VERSION 5.8 ;
BUSBITCHARS "[]" ;
DIVIDERCHAR "/" ;
UNITS
    DATABASE MICRONS 1000 ;
END UNITS

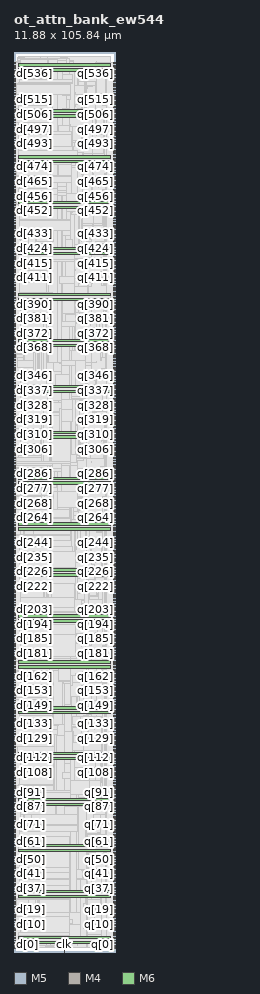
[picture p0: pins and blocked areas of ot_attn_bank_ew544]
MACRO ot_attn_bank_ew544
  FOREIGN ot_attn_bank_ew544 0 0 ;
  CLASS BLOCK ;
  SIZE 11.88 BY 105.84 ;
  PIN clk
    DIRECTION INPUT ;
    USE SIGNAL ;
    PORT
      LAYER M5 ;
        RECT  5.904 0 5.928 0.192 ;
    END
  END clk
  PIN d[0]
    DIRECTION INPUT ;
    USE SIGNAL ;
    PORT
      LAYER M4 ;
        RECT  0 0.384 0.192 0.408 ;
    END
  END d[0]
  PIN d[100]
    DIRECTION INPUT ;
    USE SIGNAL ;
    PORT
      LAYER M4 ;
        RECT  0 19.584 0.192 19.608 ;
    END
  END d[100]
  PIN d[101]
    DIRECTION INPUT ;
    USE SIGNAL ;
    PORT
      LAYER M4 ;
        RECT  0 19.776 0.192 19.8 ;
    END
  END d[101]
  PIN d[102]
    DIRECTION INPUT ;
    USE SIGNAL ;
    PORT
      LAYER M4 ;
        RECT  0 19.968 0.192 19.992 ;
    END
  END d[102]
  PIN d[103]
    DIRECTION INPUT ;
    USE SIGNAL ;
    PORT
      LAYER M4 ;
        RECT  0 20.16 0.192 20.184 ;
    END
  END d[103]
  PIN d[104]
    DIRECTION INPUT ;
    USE SIGNAL ;
    PORT
      LAYER M4 ;
        RECT  0 20.352 0.192 20.376 ;
    END
  END d[104]
  PIN d[105]
    DIRECTION INPUT ;
    USE SIGNAL ;
    PORT
      LAYER M4 ;
        RECT  0 20.544 0.192 20.568 ;
    END
  END d[105]
  PIN d[106]
    DIRECTION INPUT ;
    USE SIGNAL ;
    PORT
      LAYER M4 ;
        RECT  0 20.736 0.192 20.76 ;
    END
  END d[106]
  PIN d[107]
    DIRECTION INPUT ;
    USE SIGNAL ;
    PORT
      LAYER M4 ;
        RECT  0 20.928 0.192 20.952 ;
    END
  END d[107]
  PIN d[108]
    DIRECTION INPUT ;
    USE SIGNAL ;
    PORT
      LAYER M4 ;
        RECT  0 21.12 0.192 21.144 ;
    END
  END d[108]
  PIN d[109]
    DIRECTION INPUT ;
    USE SIGNAL ;
    PORT
      LAYER M4 ;
        RECT  0 21.312 0.192 21.336 ;
    END
  END d[109]
  PIN d[10]
    DIRECTION INPUT ;
    USE SIGNAL ;
    PORT
      LAYER M4 ;
        RECT  0 2.304 0.192 2.328 ;
    END
  END d[10]
  PIN d[110]
    DIRECTION INPUT ;
    USE SIGNAL ;
    PORT
      LAYER M4 ;
        RECT  0 21.504 0.192 21.528 ;
    END
  END d[110]
  PIN d[111]
    DIRECTION INPUT ;
    USE SIGNAL ;
    PORT
      LAYER M4 ;
        RECT  0 21.696 0.192 21.72 ;
    END
  END d[111]
  PIN d[112]
    DIRECTION INPUT ;
    USE SIGNAL ;
    PORT
      LAYER M4 ;
        RECT  0 21.888 0.192 21.912 ;
    END
  END d[112]
  PIN d[113]
    DIRECTION INPUT ;
    USE SIGNAL ;
    PORT
      LAYER M4 ;
        RECT  0 22.08 0.192 22.104 ;
    END
  END d[113]
  PIN d[114]
    DIRECTION INPUT ;
    USE SIGNAL ;
    PORT
      LAYER M4 ;
        RECT  0 22.272 0.192 22.296 ;
    END
  END d[114]
  PIN d[115]
    DIRECTION INPUT ;
    USE SIGNAL ;
    PORT
      LAYER M4 ;
        RECT  0 22.464 0.192 22.488 ;
    END
  END d[115]
  PIN d[116]
    DIRECTION INPUT ;
    USE SIGNAL ;
    PORT
      LAYER M4 ;
        RECT  0 22.656 0.192 22.68 ;
    END
  END d[116]
  PIN d[117]
    DIRECTION INPUT ;
    USE SIGNAL ;
    PORT
      LAYER M4 ;
        RECT  0 22.848 0.192 22.872 ;
    END
  END d[117]
  PIN d[118]
    DIRECTION INPUT ;
    USE SIGNAL ;
    PORT
      LAYER M4 ;
        RECT  0 23.04 0.192 23.064 ;
    END
  END d[118]
  PIN d[119]
    DIRECTION INPUT ;
    USE SIGNAL ;
    PORT
      LAYER M4 ;
        RECT  0 23.232 0.192 23.256 ;
    END
  END d[119]
  PIN d[11]
    DIRECTION INPUT ;
    USE SIGNAL ;
    PORT
      LAYER M4 ;
        RECT  0 2.496 0.192 2.52 ;
    END
  END d[11]
  PIN d[120]
    DIRECTION INPUT ;
    USE SIGNAL ;
    PORT
      LAYER M4 ;
        RECT  0 23.424 0.192 23.448 ;
    END
  END d[120]
  PIN d[121]
    DIRECTION INPUT ;
    USE SIGNAL ;
    PORT
      LAYER M4 ;
        RECT  0 23.616 0.192 23.64 ;
    END
  END d[121]
  PIN d[122]
    DIRECTION INPUT ;
    USE SIGNAL ;
    PORT
      LAYER M4 ;
        RECT  0 23.808 0.192 23.832 ;
    END
  END d[122]
  PIN d[123]
    DIRECTION INPUT ;
    USE SIGNAL ;
    PORT
      LAYER M4 ;
        RECT  0 24 0.192 24.024 ;
    END
  END d[123]
  PIN d[124]
    DIRECTION INPUT ;
    USE SIGNAL ;
    PORT
      LAYER M4 ;
        RECT  0 24.192 0.192 24.216 ;
    END
  END d[124]
  PIN d[125]
    DIRECTION INPUT ;
    USE SIGNAL ;
    PORT
      LAYER M4 ;
        RECT  0 24.384 0.192 24.408 ;
    END
  END d[125]
  PIN d[126]
    DIRECTION INPUT ;
    USE SIGNAL ;
    PORT
      LAYER M4 ;
        RECT  0 24.576 0.192 24.6 ;
    END
  END d[126]
  PIN d[127]
    DIRECTION INPUT ;
    USE SIGNAL ;
    PORT
      LAYER M4 ;
        RECT  0 24.768 0.192 24.792 ;
    END
  END d[127]
  PIN d[128]
    DIRECTION INPUT ;
    USE SIGNAL ;
    PORT
      LAYER M4 ;
        RECT  0 24.96 0.192 24.984 ;
    END
  END d[128]
  PIN d[129]
    DIRECTION INPUT ;
    USE SIGNAL ;
    PORT
      LAYER M4 ;
        RECT  0 25.152 0.192 25.176 ;
    END
  END d[129]
  PIN d[12]
    DIRECTION INPUT ;
    USE SIGNAL ;
    PORT
      LAYER M4 ;
        RECT  0 2.688 0.192 2.712 ;
    END
  END d[12]
  PIN d[130]
    DIRECTION INPUT ;
    USE SIGNAL ;
    PORT
      LAYER M4 ;
        RECT  0 25.344 0.192 25.368 ;
    END
  END d[130]
  PIN d[131]
    DIRECTION INPUT ;
    USE SIGNAL ;
    PORT
      LAYER M4 ;
        RECT  0 25.536 0.192 25.56 ;
    END
  END d[131]
  PIN d[132]
    DIRECTION INPUT ;
    USE SIGNAL ;
    PORT
      LAYER M4 ;
        RECT  0 25.728 0.192 25.752 ;
    END
  END d[132]
  PIN d[133]
    DIRECTION INPUT ;
    USE SIGNAL ;
    PORT
      LAYER M4 ;
        RECT  0 25.92 0.192 25.944 ;
    END
  END d[133]
  PIN d[134]
    DIRECTION INPUT ;
    USE SIGNAL ;
    PORT
      LAYER M4 ;
        RECT  0 26.112 0.192 26.136 ;
    END
  END d[134]
  PIN d[135]
    DIRECTION INPUT ;
    USE SIGNAL ;
    PORT
      LAYER M4 ;
        RECT  0 26.304 0.192 26.328 ;
    END
  END d[135]
  PIN d[136]
    DIRECTION INPUT ;
    USE SIGNAL ;
    PORT
      LAYER M4 ;
        RECT  0 26.496 0.192 26.52 ;
    END
  END d[136]
  PIN d[137]
    DIRECTION INPUT ;
    USE SIGNAL ;
    PORT
      LAYER M4 ;
        RECT  0 26.688 0.192 26.712 ;
    END
  END d[137]
  PIN d[138]
    DIRECTION INPUT ;
    USE SIGNAL ;
    PORT
      LAYER M4 ;
        RECT  0 26.88 0.192 26.904 ;
    END
  END d[138]
  PIN d[139]
    DIRECTION INPUT ;
    USE SIGNAL ;
    PORT
      LAYER M4 ;
        RECT  0 27.072 0.192 27.096 ;
    END
  END d[139]
  PIN d[13]
    DIRECTION INPUT ;
    USE SIGNAL ;
    PORT
      LAYER M4 ;
        RECT  0 2.88 0.192 2.904 ;
    END
  END d[13]
  PIN d[140]
    DIRECTION INPUT ;
    USE SIGNAL ;
    PORT
      LAYER M4 ;
        RECT  0 27.264 0.192 27.288 ;
    END
  END d[140]
  PIN d[141]
    DIRECTION INPUT ;
    USE SIGNAL ;
    PORT
      LAYER M4 ;
        RECT  0 27.456 0.192 27.48 ;
    END
  END d[141]
  PIN d[142]
    DIRECTION INPUT ;
    USE SIGNAL ;
    PORT
      LAYER M4 ;
        RECT  0 27.648 0.192 27.672 ;
    END
  END d[142]
  PIN d[143]
    DIRECTION INPUT ;
    USE SIGNAL ;
    PORT
      LAYER M4 ;
        RECT  0 27.84 0.192 27.864 ;
    END
  END d[143]
  PIN d[144]
    DIRECTION INPUT ;
    USE SIGNAL ;
    PORT
      LAYER M4 ;
        RECT  0 28.032 0.192 28.056 ;
    END
  END d[144]
  PIN d[145]
    DIRECTION INPUT ;
    USE SIGNAL ;
    PORT
      LAYER M4 ;
        RECT  0 28.224 0.192 28.248 ;
    END
  END d[145]
  PIN d[146]
    DIRECTION INPUT ;
    USE SIGNAL ;
    PORT
      LAYER M4 ;
        RECT  0 28.416 0.192 28.44 ;
    END
  END d[146]
  PIN d[147]
    DIRECTION INPUT ;
    USE SIGNAL ;
    PORT
      LAYER M4 ;
        RECT  0 28.608 0.192 28.632 ;
    END
  END d[147]
  PIN d[148]
    DIRECTION INPUT ;
    USE SIGNAL ;
    PORT
      LAYER M4 ;
        RECT  0 28.8 0.192 28.824 ;
    END
  END d[148]
  PIN d[149]
    DIRECTION INPUT ;
    USE SIGNAL ;
    PORT
      LAYER M4 ;
        RECT  0 28.992 0.192 29.016 ;
    END
  END d[149]
  PIN d[14]
    DIRECTION INPUT ;
    USE SIGNAL ;
    PORT
      LAYER M4 ;
        RECT  0 3.072 0.192 3.096 ;
    END
  END d[14]
  PIN d[150]
    DIRECTION INPUT ;
    USE SIGNAL ;
    PORT
      LAYER M4 ;
        RECT  0 29.184 0.192 29.208 ;
    END
  END d[150]
  PIN d[151]
    DIRECTION INPUT ;
    USE SIGNAL ;
    PORT
      LAYER M4 ;
        RECT  0 29.376 0.192 29.4 ;
    END
  END d[151]
  PIN d[152]
    DIRECTION INPUT ;
    USE SIGNAL ;
    PORT
      LAYER M4 ;
        RECT  0 29.568 0.192 29.592 ;
    END
  END d[152]
  PIN d[153]
    DIRECTION INPUT ;
    USE SIGNAL ;
    PORT
      LAYER M4 ;
        RECT  0 29.76 0.192 29.784 ;
    END
  END d[153]
  PIN d[154]
    DIRECTION INPUT ;
    USE SIGNAL ;
    PORT
      LAYER M4 ;
        RECT  0 29.952 0.192 29.976 ;
    END
  END d[154]
  PIN d[155]
    DIRECTION INPUT ;
    USE SIGNAL ;
    PORT
      LAYER M4 ;
        RECT  0 30.144 0.192 30.168 ;
    END
  END d[155]
  PIN d[156]
    DIRECTION INPUT ;
    USE SIGNAL ;
    PORT
      LAYER M4 ;
        RECT  0 30.336 0.192 30.36 ;
    END
  END d[156]
  PIN d[157]
    DIRECTION INPUT ;
    USE SIGNAL ;
    PORT
      LAYER M4 ;
        RECT  0 30.528 0.192 30.552 ;
    END
  END d[157]
  PIN d[158]
    DIRECTION INPUT ;
    USE SIGNAL ;
    PORT
      LAYER M4 ;
        RECT  0 30.72 0.192 30.744 ;
    END
  END d[158]
  PIN d[159]
    DIRECTION INPUT ;
    USE SIGNAL ;
    PORT
      LAYER M4 ;
        RECT  0 30.912 0.192 30.936 ;
    END
  END d[159]
  PIN d[15]
    DIRECTION INPUT ;
    USE SIGNAL ;
    PORT
      LAYER M4 ;
        RECT  0 3.264 0.192 3.288 ;
    END
  END d[15]
  PIN d[160]
    DIRECTION INPUT ;
    USE SIGNAL ;
    PORT
      LAYER M4 ;
        RECT  0 31.104 0.192 31.128 ;
    END
  END d[160]
  PIN d[161]
    DIRECTION INPUT ;
    USE SIGNAL ;
    PORT
      LAYER M4 ;
        RECT  0 31.296 0.192 31.32 ;
    END
  END d[161]
  PIN d[162]
    DIRECTION INPUT ;
    USE SIGNAL ;
    PORT
      LAYER M4 ;
        RECT  0 31.488 0.192 31.512 ;
    END
  END d[162]
  PIN d[163]
    DIRECTION INPUT ;
    USE SIGNAL ;
    PORT
      LAYER M4 ;
        RECT  0 31.68 0.192 31.704 ;
    END
  END d[163]
  PIN d[164]
    DIRECTION INPUT ;
    USE SIGNAL ;
    PORT
      LAYER M4 ;
        RECT  0 31.872 0.192 31.896 ;
    END
  END d[164]
  PIN d[165]
    DIRECTION INPUT ;
    USE SIGNAL ;
    PORT
      LAYER M4 ;
        RECT  0 32.064 0.192 32.088 ;
    END
  END d[165]
  PIN d[166]
    DIRECTION INPUT ;
    USE SIGNAL ;
    PORT
      LAYER M4 ;
        RECT  0 32.256 0.192 32.28 ;
    END
  END d[166]
  PIN d[167]
    DIRECTION INPUT ;
    USE SIGNAL ;
    PORT
      LAYER M4 ;
        RECT  0 32.448 0.192 32.472 ;
    END
  END d[167]
  PIN d[168]
    DIRECTION INPUT ;
    USE SIGNAL ;
    PORT
      LAYER M4 ;
        RECT  0 32.64 0.192 32.664 ;
    END
  END d[168]
  PIN d[169]
    DIRECTION INPUT ;
    USE SIGNAL ;
    PORT
      LAYER M4 ;
        RECT  0 32.832 0.192 32.856 ;
    END
  END d[169]
  PIN d[16]
    DIRECTION INPUT ;
    USE SIGNAL ;
    PORT
      LAYER M4 ;
        RECT  0 3.456 0.192 3.48 ;
    END
  END d[16]
  PIN d[170]
    DIRECTION INPUT ;
    USE SIGNAL ;
    PORT
      LAYER M4 ;
        RECT  0 33.024 0.192 33.048 ;
    END
  END d[170]
  PIN d[171]
    DIRECTION INPUT ;
    USE SIGNAL ;
    PORT
      LAYER M4 ;
        RECT  0 33.216 0.192 33.24 ;
    END
  END d[171]
  PIN d[172]
    DIRECTION INPUT ;
    USE SIGNAL ;
    PORT
      LAYER M4 ;
        RECT  0 33.408 0.192 33.432 ;
    END
  END d[172]
  PIN d[173]
    DIRECTION INPUT ;
    USE SIGNAL ;
    PORT
      LAYER M4 ;
        RECT  0 33.6 0.192 33.624 ;
    END
  END d[173]
  PIN d[174]
    DIRECTION INPUT ;
    USE SIGNAL ;
    PORT
      LAYER M4 ;
        RECT  0 33.792 0.192 33.816 ;
    END
  END d[174]
  PIN d[175]
    DIRECTION INPUT ;
    USE SIGNAL ;
    PORT
      LAYER M4 ;
        RECT  0 33.984 0.192 34.008 ;
    END
  END d[175]
  PIN d[176]
    DIRECTION INPUT ;
    USE SIGNAL ;
    PORT
      LAYER M4 ;
        RECT  0 34.176 0.192 34.2 ;
    END
  END d[176]
  PIN d[177]
    DIRECTION INPUT ;
    USE SIGNAL ;
    PORT
      LAYER M4 ;
        RECT  0 34.368 0.192 34.392 ;
    END
  END d[177]
  PIN d[178]
    DIRECTION INPUT ;
    USE SIGNAL ;
    PORT
      LAYER M4 ;
        RECT  0 34.56 0.192 34.584 ;
    END
  END d[178]
  PIN d[179]
    DIRECTION INPUT ;
    USE SIGNAL ;
    PORT
      LAYER M4 ;
        RECT  0 34.752 0.192 34.776 ;
    END
  END d[179]
  PIN d[17]
    DIRECTION INPUT ;
    USE SIGNAL ;
    PORT
      LAYER M4 ;
        RECT  0 3.648 0.192 3.672 ;
    END
  END d[17]
  PIN d[180]
    DIRECTION INPUT ;
    USE SIGNAL ;
    PORT
      LAYER M4 ;
        RECT  0 34.944 0.192 34.968 ;
    END
  END d[180]
  PIN d[181]
    DIRECTION INPUT ;
    USE SIGNAL ;
    PORT
      LAYER M4 ;
        RECT  0 35.136 0.192 35.16 ;
    END
  END d[181]
  PIN d[182]
    DIRECTION INPUT ;
    USE SIGNAL ;
    PORT
      LAYER M4 ;
        RECT  0 35.328 0.192 35.352 ;
    END
  END d[182]
  PIN d[183]
    DIRECTION INPUT ;
    USE SIGNAL ;
    PORT
      LAYER M4 ;
        RECT  0 35.52 0.192 35.544 ;
    END
  END d[183]
  PIN d[184]
    DIRECTION INPUT ;
    USE SIGNAL ;
    PORT
      LAYER M4 ;
        RECT  0 35.712 0.192 35.736 ;
    END
  END d[184]
  PIN d[185]
    DIRECTION INPUT ;
    USE SIGNAL ;
    PORT
      LAYER M4 ;
        RECT  0 35.904 0.192 35.928 ;
    END
  END d[185]
  PIN d[186]
    DIRECTION INPUT ;
    USE SIGNAL ;
    PORT
      LAYER M4 ;
        RECT  0 36.096 0.192 36.12 ;
    END
  END d[186]
  PIN d[187]
    DIRECTION INPUT ;
    USE SIGNAL ;
    PORT
      LAYER M4 ;
        RECT  0 36.288 0.192 36.312 ;
    END
  END d[187]
  PIN d[188]
    DIRECTION INPUT ;
    USE SIGNAL ;
    PORT
      LAYER M4 ;
        RECT  0 36.48 0.192 36.504 ;
    END
  END d[188]
  PIN d[189]
    DIRECTION INPUT ;
    USE SIGNAL ;
    PORT
      LAYER M4 ;
        RECT  0 36.672 0.192 36.696 ;
    END
  END d[189]
  PIN d[18]
    DIRECTION INPUT ;
    USE SIGNAL ;
    PORT
      LAYER M4 ;
        RECT  0 3.84 0.192 3.864 ;
    END
  END d[18]
  PIN d[190]
    DIRECTION INPUT ;
    USE SIGNAL ;
    PORT
      LAYER M4 ;
        RECT  0 36.864 0.192 36.888 ;
    END
  END d[190]
  PIN d[191]
    DIRECTION INPUT ;
    USE SIGNAL ;
    PORT
      LAYER M4 ;
        RECT  0 37.056 0.192 37.08 ;
    END
  END d[191]
  PIN d[192]
    DIRECTION INPUT ;
    USE SIGNAL ;
    PORT
      LAYER M4 ;
        RECT  0 37.248 0.192 37.272 ;
    END
  END d[192]
  PIN d[193]
    DIRECTION INPUT ;
    USE SIGNAL ;
    PORT
      LAYER M4 ;
        RECT  0 37.44 0.192 37.464 ;
    END
  END d[193]
  PIN d[194]
    DIRECTION INPUT ;
    USE SIGNAL ;
    PORT
      LAYER M4 ;
        RECT  0 37.632 0.192 37.656 ;
    END
  END d[194]
  PIN d[195]
    DIRECTION INPUT ;
    USE SIGNAL ;
    PORT
      LAYER M4 ;
        RECT  0 37.824 0.192 37.848 ;
    END
  END d[195]
  PIN d[196]
    DIRECTION INPUT ;
    USE SIGNAL ;
    PORT
      LAYER M4 ;
        RECT  0 38.016 0.192 38.04 ;
    END
  END d[196]
  PIN d[197]
    DIRECTION INPUT ;
    USE SIGNAL ;
    PORT
      LAYER M4 ;
        RECT  0 38.208 0.192 38.232 ;
    END
  END d[197]
  PIN d[198]
    DIRECTION INPUT ;
    USE SIGNAL ;
    PORT
      LAYER M4 ;
        RECT  0 38.4 0.192 38.424 ;
    END
  END d[198]
  PIN d[199]
    DIRECTION INPUT ;
    USE SIGNAL ;
    PORT
      LAYER M4 ;
        RECT  0 38.592 0.192 38.616 ;
    END
  END d[199]
  PIN d[19]
    DIRECTION INPUT ;
    USE SIGNAL ;
    PORT
      LAYER M4 ;
        RECT  0 4.032 0.192 4.056 ;
    END
  END d[19]
  PIN d[1]
    DIRECTION INPUT ;
    USE SIGNAL ;
    PORT
      LAYER M4 ;
        RECT  0 0.576 0.192 0.6 ;
    END
  END d[1]
  PIN d[200]
    DIRECTION INPUT ;
    USE SIGNAL ;
    PORT
      LAYER M4 ;
        RECT  0 38.784 0.192 38.808 ;
    END
  END d[200]
  PIN d[201]
    DIRECTION INPUT ;
    USE SIGNAL ;
    PORT
      LAYER M4 ;
        RECT  0 38.976 0.192 39 ;
    END
  END d[201]
  PIN d[202]
    DIRECTION INPUT ;
    USE SIGNAL ;
    PORT
      LAYER M4 ;
        RECT  0 39.168 0.192 39.192 ;
    END
  END d[202]
  PIN d[203]
    DIRECTION INPUT ;
    USE SIGNAL ;
    PORT
      LAYER M4 ;
        RECT  0 39.36 0.192 39.384 ;
    END
  END d[203]
  PIN d[204]
    DIRECTION INPUT ;
    USE SIGNAL ;
    PORT
      LAYER M4 ;
        RECT  0 39.552 0.192 39.576 ;
    END
  END d[204]
  PIN d[205]
    DIRECTION INPUT ;
    USE SIGNAL ;
    PORT
      LAYER M4 ;
        RECT  0 39.744 0.192 39.768 ;
    END
  END d[205]
  PIN d[206]
    DIRECTION INPUT ;
    USE SIGNAL ;
    PORT
      LAYER M4 ;
        RECT  0 39.936 0.192 39.96 ;
    END
  END d[206]
  PIN d[207]
    DIRECTION INPUT ;
    USE SIGNAL ;
    PORT
      LAYER M4 ;
        RECT  0 40.128 0.192 40.152 ;
    END
  END d[207]
  PIN d[208]
    DIRECTION INPUT ;
    USE SIGNAL ;
    PORT
      LAYER M4 ;
        RECT  0 40.32 0.192 40.344 ;
    END
  END d[208]
  PIN d[209]
    DIRECTION INPUT ;
    USE SIGNAL ;
    PORT
      LAYER M4 ;
        RECT  0 40.512 0.192 40.536 ;
    END
  END d[209]
  PIN d[20]
    DIRECTION INPUT ;
    USE SIGNAL ;
    PORT
      LAYER M4 ;
        RECT  0 4.224 0.192 4.248 ;
    END
  END d[20]
  PIN d[210]
    DIRECTION INPUT ;
    USE SIGNAL ;
    PORT
      LAYER M4 ;
        RECT  0 40.704 0.192 40.728 ;
    END
  END d[210]
  PIN d[211]
    DIRECTION INPUT ;
    USE SIGNAL ;
    PORT
      LAYER M4 ;
        RECT  0 40.896 0.192 40.92 ;
    END
  END d[211]
  PIN d[212]
    DIRECTION INPUT ;
    USE SIGNAL ;
    PORT
      LAYER M4 ;
        RECT  0 41.088 0.192 41.112 ;
    END
  END d[212]
  PIN d[213]
    DIRECTION INPUT ;
    USE SIGNAL ;
    PORT
      LAYER M4 ;
        RECT  0 41.28 0.192 41.304 ;
    END
  END d[213]
  PIN d[214]
    DIRECTION INPUT ;
    USE SIGNAL ;
    PORT
      LAYER M4 ;
        RECT  0 41.472 0.192 41.496 ;
    END
  END d[214]
  PIN d[215]
    DIRECTION INPUT ;
    USE SIGNAL ;
    PORT
      LAYER M4 ;
        RECT  0 41.664 0.192 41.688 ;
    END
  END d[215]
  PIN d[216]
    DIRECTION INPUT ;
    USE SIGNAL ;
    PORT
      LAYER M4 ;
        RECT  0 41.856 0.192 41.88 ;
    END
  END d[216]
  PIN d[217]
    DIRECTION INPUT ;
    USE SIGNAL ;
    PORT
      LAYER M4 ;
        RECT  0 42.048 0.192 42.072 ;
    END
  END d[217]
  PIN d[218]
    DIRECTION INPUT ;
    USE SIGNAL ;
    PORT
      LAYER M4 ;
        RECT  0 42.24 0.192 42.264 ;
    END
  END d[218]
  PIN d[219]
    DIRECTION INPUT ;
    USE SIGNAL ;
    PORT
      LAYER M4 ;
        RECT  0 42.432 0.192 42.456 ;
    END
  END d[219]
  PIN d[21]
    DIRECTION INPUT ;
    USE SIGNAL ;
    PORT
      LAYER M4 ;
        RECT  0 4.416 0.192 4.44 ;
    END
  END d[21]
  PIN d[220]
    DIRECTION INPUT ;
    USE SIGNAL ;
    PORT
      LAYER M4 ;
        RECT  0 42.624 0.192 42.648 ;
    END
  END d[220]
  PIN d[221]
    DIRECTION INPUT ;
    USE SIGNAL ;
    PORT
      LAYER M4 ;
        RECT  0 42.816 0.192 42.84 ;
    END
  END d[221]
  PIN d[222]
    DIRECTION INPUT ;
    USE SIGNAL ;
    PORT
      LAYER M4 ;
        RECT  0 43.008 0.192 43.032 ;
    END
  END d[222]
  PIN d[223]
    DIRECTION INPUT ;
    USE SIGNAL ;
    PORT
      LAYER M4 ;
        RECT  0 43.2 0.192 43.224 ;
    END
  END d[223]
  PIN d[224]
    DIRECTION INPUT ;
    USE SIGNAL ;
    PORT
      LAYER M4 ;
        RECT  0 43.392 0.192 43.416 ;
    END
  END d[224]
  PIN d[225]
    DIRECTION INPUT ;
    USE SIGNAL ;
    PORT
      LAYER M4 ;
        RECT  0 43.584 0.192 43.608 ;
    END
  END d[225]
  PIN d[226]
    DIRECTION INPUT ;
    USE SIGNAL ;
    PORT
      LAYER M4 ;
        RECT  0 43.776 0.192 43.8 ;
    END
  END d[226]
  PIN d[227]
    DIRECTION INPUT ;
    USE SIGNAL ;
    PORT
      LAYER M4 ;
        RECT  0 43.968 0.192 43.992 ;
    END
  END d[227]
  PIN d[228]
    DIRECTION INPUT ;
    USE SIGNAL ;
    PORT
      LAYER M4 ;
        RECT  0 44.16 0.192 44.184 ;
    END
  END d[228]
  PIN d[229]
    DIRECTION INPUT ;
    USE SIGNAL ;
    PORT
      LAYER M4 ;
        RECT  0 44.352 0.192 44.376 ;
    END
  END d[229]
  PIN d[22]
    DIRECTION INPUT ;
    USE SIGNAL ;
    PORT
      LAYER M4 ;
        RECT  0 4.608 0.192 4.632 ;
    END
  END d[22]
  PIN d[230]
    DIRECTION INPUT ;
    USE SIGNAL ;
    PORT
      LAYER M4 ;
        RECT  0 44.544 0.192 44.568 ;
    END
  END d[230]
  PIN d[231]
    DIRECTION INPUT ;
    USE SIGNAL ;
    PORT
      LAYER M4 ;
        RECT  0 44.736 0.192 44.76 ;
    END
  END d[231]
  PIN d[232]
    DIRECTION INPUT ;
    USE SIGNAL ;
    PORT
      LAYER M4 ;
        RECT  0 44.928 0.192 44.952 ;
    END
  END d[232]
  PIN d[233]
    DIRECTION INPUT ;
    USE SIGNAL ;
    PORT
      LAYER M4 ;
        RECT  0 45.12 0.192 45.144 ;
    END
  END d[233]
  PIN d[234]
    DIRECTION INPUT ;
    USE SIGNAL ;
    PORT
      LAYER M4 ;
        RECT  0 45.312 0.192 45.336 ;
    END
  END d[234]
  PIN d[235]
    DIRECTION INPUT ;
    USE SIGNAL ;
    PORT
      LAYER M4 ;
        RECT  0 45.504 0.192 45.528 ;
    END
  END d[235]
  PIN d[236]
    DIRECTION INPUT ;
    USE SIGNAL ;
    PORT
      LAYER M4 ;
        RECT  0 45.696 0.192 45.72 ;
    END
  END d[236]
  PIN d[237]
    DIRECTION INPUT ;
    USE SIGNAL ;
    PORT
      LAYER M4 ;
        RECT  0 45.888 0.192 45.912 ;
    END
  END d[237]
  PIN d[238]
    DIRECTION INPUT ;
    USE SIGNAL ;
    PORT
      LAYER M4 ;
        RECT  0 46.08 0.192 46.104 ;
    END
  END d[238]
  PIN d[239]
    DIRECTION INPUT ;
    USE SIGNAL ;
    PORT
      LAYER M4 ;
        RECT  0 46.272 0.192 46.296 ;
    END
  END d[239]
  PIN d[23]
    DIRECTION INPUT ;
    USE SIGNAL ;
    PORT
      LAYER M4 ;
        RECT  0 4.8 0.192 4.824 ;
    END
  END d[23]
  PIN d[240]
    DIRECTION INPUT ;
    USE SIGNAL ;
    PORT
      LAYER M4 ;
        RECT  0 46.464 0.192 46.488 ;
    END
  END d[240]
  PIN d[241]
    DIRECTION INPUT ;
    USE SIGNAL ;
    PORT
      LAYER M4 ;
        RECT  0 46.656 0.192 46.68 ;
    END
  END d[241]
  PIN d[242]
    DIRECTION INPUT ;
    USE SIGNAL ;
    PORT
      LAYER M4 ;
        RECT  0 46.848 0.192 46.872 ;
    END
  END d[242]
  PIN d[243]
    DIRECTION INPUT ;
    USE SIGNAL ;
    PORT
      LAYER M4 ;
        RECT  0 47.04 0.192 47.064 ;
    END
  END d[243]
  PIN d[244]
    DIRECTION INPUT ;
    USE SIGNAL ;
    PORT
      LAYER M4 ;
        RECT  0 47.232 0.192 47.256 ;
    END
  END d[244]
  PIN d[245]
    DIRECTION INPUT ;
    USE SIGNAL ;
    PORT
      LAYER M4 ;
        RECT  0 47.424 0.192 47.448 ;
    END
  END d[245]
  PIN d[246]
    DIRECTION INPUT ;
    USE SIGNAL ;
    PORT
      LAYER M4 ;
        RECT  0 47.616 0.192 47.64 ;
    END
  END d[246]
  PIN d[247]
    DIRECTION INPUT ;
    USE SIGNAL ;
    PORT
      LAYER M4 ;
        RECT  0 47.808 0.192 47.832 ;
    END
  END d[247]
  PIN d[248]
    DIRECTION INPUT ;
    USE SIGNAL ;
    PORT
      LAYER M4 ;
        RECT  0 48 0.192 48.024 ;
    END
  END d[248]
  PIN d[249]
    DIRECTION INPUT ;
    USE SIGNAL ;
    PORT
      LAYER M4 ;
        RECT  0 48.192 0.192 48.216 ;
    END
  END d[249]
  PIN d[24]
    DIRECTION INPUT ;
    USE SIGNAL ;
    PORT
      LAYER M4 ;
        RECT  0 4.992 0.192 5.016 ;
    END
  END d[24]
  PIN d[250]
    DIRECTION INPUT ;
    USE SIGNAL ;
    PORT
      LAYER M4 ;
        RECT  0 48.384 0.192 48.408 ;
    END
  END d[250]
  PIN d[251]
    DIRECTION INPUT ;
    USE SIGNAL ;
    PORT
      LAYER M4 ;
        RECT  0 48.576 0.192 48.6 ;
    END
  END d[251]
  PIN d[252]
    DIRECTION INPUT ;
    USE SIGNAL ;
    PORT
      LAYER M4 ;
        RECT  0 48.768 0.192 48.792 ;
    END
  END d[252]
  PIN d[253]
    DIRECTION INPUT ;
    USE SIGNAL ;
    PORT
      LAYER M4 ;
        RECT  0 48.96 0.192 48.984 ;
    END
  END d[253]
  PIN d[254]
    DIRECTION INPUT ;
    USE SIGNAL ;
    PORT
      LAYER M4 ;
        RECT  0 49.152 0.192 49.176 ;
    END
  END d[254]
  PIN d[255]
    DIRECTION INPUT ;
    USE SIGNAL ;
    PORT
      LAYER M4 ;
        RECT  0 49.344 0.192 49.368 ;
    END
  END d[255]
  PIN d[256]
    DIRECTION INPUT ;
    USE SIGNAL ;
    PORT
      LAYER M4 ;
        RECT  0 49.536 0.192 49.56 ;
    END
  END d[256]
  PIN d[257]
    DIRECTION INPUT ;
    USE SIGNAL ;
    PORT
      LAYER M4 ;
        RECT  0 49.728 0.192 49.752 ;
    END
  END d[257]
  PIN d[258]
    DIRECTION INPUT ;
    USE SIGNAL ;
    PORT
      LAYER M4 ;
        RECT  0 49.92 0.192 49.944 ;
    END
  END d[258]
  PIN d[259]
    DIRECTION INPUT ;
    USE SIGNAL ;
    PORT
      LAYER M4 ;
        RECT  0 50.112 0.192 50.136 ;
    END
  END d[259]
  PIN d[25]
    DIRECTION INPUT ;
    USE SIGNAL ;
    PORT
      LAYER M4 ;
        RECT  0 5.184 0.192 5.208 ;
    END
  END d[25]
  PIN d[260]
    DIRECTION INPUT ;
    USE SIGNAL ;
    PORT
      LAYER M4 ;
        RECT  0 50.304 0.192 50.328 ;
    END
  END d[260]
  PIN d[261]
    DIRECTION INPUT ;
    USE SIGNAL ;
    PORT
      LAYER M4 ;
        RECT  0 50.496 0.192 50.52 ;
    END
  END d[261]
  PIN d[262]
    DIRECTION INPUT ;
    USE SIGNAL ;
    PORT
      LAYER M4 ;
        RECT  0 50.688 0.192 50.712 ;
    END
  END d[262]
  PIN d[263]
    DIRECTION INPUT ;
    USE SIGNAL ;
    PORT
      LAYER M4 ;
        RECT  0 50.88 0.192 50.904 ;
    END
  END d[263]
  PIN d[264]
    DIRECTION INPUT ;
    USE SIGNAL ;
    PORT
      LAYER M4 ;
        RECT  0 51.072 0.192 51.096 ;
    END
  END d[264]
  PIN d[265]
    DIRECTION INPUT ;
    USE SIGNAL ;
    PORT
      LAYER M4 ;
        RECT  0 51.264 0.192 51.288 ;
    END
  END d[265]
  PIN d[266]
    DIRECTION INPUT ;
    USE SIGNAL ;
    PORT
      LAYER M4 ;
        RECT  0 51.456 0.192 51.48 ;
    END
  END d[266]
  PIN d[267]
    DIRECTION INPUT ;
    USE SIGNAL ;
    PORT
      LAYER M4 ;
        RECT  0 51.648 0.192 51.672 ;
    END
  END d[267]
  PIN d[268]
    DIRECTION INPUT ;
    USE SIGNAL ;
    PORT
      LAYER M4 ;
        RECT  0 51.84 0.192 51.864 ;
    END
  END d[268]
  PIN d[269]
    DIRECTION INPUT ;
    USE SIGNAL ;
    PORT
      LAYER M4 ;
        RECT  0 52.032 0.192 52.056 ;
    END
  END d[269]
  PIN d[26]
    DIRECTION INPUT ;
    USE SIGNAL ;
    PORT
      LAYER M4 ;
        RECT  0 5.376 0.192 5.4 ;
    END
  END d[26]
  PIN d[270]
    DIRECTION INPUT ;
    USE SIGNAL ;
    PORT
      LAYER M4 ;
        RECT  0 52.224 0.192 52.248 ;
    END
  END d[270]
  PIN d[271]
    DIRECTION INPUT ;
    USE SIGNAL ;
    PORT
      LAYER M4 ;
        RECT  0 52.416 0.192 52.44 ;
    END
  END d[271]
  PIN d[272]
    DIRECTION INPUT ;
    USE SIGNAL ;
    PORT
      LAYER M4 ;
        RECT  0 52.608 0.192 52.632 ;
    END
  END d[272]
  PIN d[273]
    DIRECTION INPUT ;
    USE SIGNAL ;
    PORT
      LAYER M4 ;
        RECT  0 52.8 0.192 52.824 ;
    END
  END d[273]
  PIN d[274]
    DIRECTION INPUT ;
    USE SIGNAL ;
    PORT
      LAYER M4 ;
        RECT  0 52.992 0.192 53.016 ;
    END
  END d[274]
  PIN d[275]
    DIRECTION INPUT ;
    USE SIGNAL ;
    PORT
      LAYER M4 ;
        RECT  0 53.184 0.192 53.208 ;
    END
  END d[275]
  PIN d[276]
    DIRECTION INPUT ;
    USE SIGNAL ;
    PORT
      LAYER M4 ;
        RECT  0 53.376 0.192 53.4 ;
    END
  END d[276]
  PIN d[277]
    DIRECTION INPUT ;
    USE SIGNAL ;
    PORT
      LAYER M4 ;
        RECT  0 53.568 0.192 53.592 ;
    END
  END d[277]
  PIN d[278]
    DIRECTION INPUT ;
    USE SIGNAL ;
    PORT
      LAYER M4 ;
        RECT  0 53.76 0.192 53.784 ;
    END
  END d[278]
  PIN d[279]
    DIRECTION INPUT ;
    USE SIGNAL ;
    PORT
      LAYER M4 ;
        RECT  0 53.952 0.192 53.976 ;
    END
  END d[279]
  PIN d[27]
    DIRECTION INPUT ;
    USE SIGNAL ;
    PORT
      LAYER M4 ;
        RECT  0 5.568 0.192 5.592 ;
    END
  END d[27]
  PIN d[280]
    DIRECTION INPUT ;
    USE SIGNAL ;
    PORT
      LAYER M4 ;
        RECT  0 54.144 0.192 54.168 ;
    END
  END d[280]
  PIN d[281]
    DIRECTION INPUT ;
    USE SIGNAL ;
    PORT
      LAYER M4 ;
        RECT  0 54.336 0.192 54.36 ;
    END
  END d[281]
  PIN d[282]
    DIRECTION INPUT ;
    USE SIGNAL ;
    PORT
      LAYER M4 ;
        RECT  0 54.528 0.192 54.552 ;
    END
  END d[282]
  PIN d[283]
    DIRECTION INPUT ;
    USE SIGNAL ;
    PORT
      LAYER M4 ;
        RECT  0 54.72 0.192 54.744 ;
    END
  END d[283]
  PIN d[284]
    DIRECTION INPUT ;
    USE SIGNAL ;
    PORT
      LAYER M4 ;
        RECT  0 54.912 0.192 54.936 ;
    END
  END d[284]
  PIN d[285]
    DIRECTION INPUT ;
    USE SIGNAL ;
    PORT
      LAYER M4 ;
        RECT  0 55.104 0.192 55.128 ;
    END
  END d[285]
  PIN d[286]
    DIRECTION INPUT ;
    USE SIGNAL ;
    PORT
      LAYER M4 ;
        RECT  0 55.296 0.192 55.32 ;
    END
  END d[286]
  PIN d[287]
    DIRECTION INPUT ;
    USE SIGNAL ;
    PORT
      LAYER M4 ;
        RECT  0 55.488 0.192 55.512 ;
    END
  END d[287]
  PIN d[288]
    DIRECTION INPUT ;
    USE SIGNAL ;
    PORT
      LAYER M4 ;
        RECT  0 55.68 0.192 55.704 ;
    END
  END d[288]
  PIN d[289]
    DIRECTION INPUT ;
    USE SIGNAL ;
    PORT
      LAYER M4 ;
        RECT  0 55.872 0.192 55.896 ;
    END
  END d[289]
  PIN d[28]
    DIRECTION INPUT ;
    USE SIGNAL ;
    PORT
      LAYER M4 ;
        RECT  0 5.76 0.192 5.784 ;
    END
  END d[28]
  PIN d[290]
    DIRECTION INPUT ;
    USE SIGNAL ;
    PORT
      LAYER M4 ;
        RECT  0 56.064 0.192 56.088 ;
    END
  END d[290]
  PIN d[291]
    DIRECTION INPUT ;
    USE SIGNAL ;
    PORT
      LAYER M4 ;
        RECT  0 56.256 0.192 56.28 ;
    END
  END d[291]
  PIN d[292]
    DIRECTION INPUT ;
    USE SIGNAL ;
    PORT
      LAYER M4 ;
        RECT  0 56.448 0.192 56.472 ;
    END
  END d[292]
  PIN d[293]
    DIRECTION INPUT ;
    USE SIGNAL ;
    PORT
      LAYER M4 ;
        RECT  0 56.64 0.192 56.664 ;
    END
  END d[293]
  PIN d[294]
    DIRECTION INPUT ;
    USE SIGNAL ;
    PORT
      LAYER M4 ;
        RECT  0 56.832 0.192 56.856 ;
    END
  END d[294]
  PIN d[295]
    DIRECTION INPUT ;
    USE SIGNAL ;
    PORT
      LAYER M4 ;
        RECT  0 57.024 0.192 57.048 ;
    END
  END d[295]
  PIN d[296]
    DIRECTION INPUT ;
    USE SIGNAL ;
    PORT
      LAYER M4 ;
        RECT  0 57.216 0.192 57.24 ;
    END
  END d[296]
  PIN d[297]
    DIRECTION INPUT ;
    USE SIGNAL ;
    PORT
      LAYER M4 ;
        RECT  0 57.408 0.192 57.432 ;
    END
  END d[297]
  PIN d[298]
    DIRECTION INPUT ;
    USE SIGNAL ;
    PORT
      LAYER M4 ;
        RECT  0 57.6 0.192 57.624 ;
    END
  END d[298]
  PIN d[299]
    DIRECTION INPUT ;
    USE SIGNAL ;
    PORT
      LAYER M4 ;
        RECT  0 57.792 0.192 57.816 ;
    END
  END d[299]
  PIN d[29]
    DIRECTION INPUT ;
    USE SIGNAL ;
    PORT
      LAYER M4 ;
        RECT  0 5.952 0.192 5.976 ;
    END
  END d[29]
  PIN d[2]
    DIRECTION INPUT ;
    USE SIGNAL ;
    PORT
      LAYER M4 ;
        RECT  0 0.768 0.192 0.792 ;
    END
  END d[2]
  PIN d[300]
    DIRECTION INPUT ;
    USE SIGNAL ;
    PORT
      LAYER M4 ;
        RECT  0 57.984 0.192 58.008 ;
    END
  END d[300]
  PIN d[301]
    DIRECTION INPUT ;
    USE SIGNAL ;
    PORT
      LAYER M4 ;
        RECT  0 58.176 0.192 58.2 ;
    END
  END d[301]
  PIN d[302]
    DIRECTION INPUT ;
    USE SIGNAL ;
    PORT
      LAYER M4 ;
        RECT  0 58.368 0.192 58.392 ;
    END
  END d[302]
  PIN d[303]
    DIRECTION INPUT ;
    USE SIGNAL ;
    PORT
      LAYER M4 ;
        RECT  0 58.56 0.192 58.584 ;
    END
  END d[303]
  PIN d[304]
    DIRECTION INPUT ;
    USE SIGNAL ;
    PORT
      LAYER M4 ;
        RECT  0 58.752 0.192 58.776 ;
    END
  END d[304]
  PIN d[305]
    DIRECTION INPUT ;
    USE SIGNAL ;
    PORT
      LAYER M4 ;
        RECT  0 58.944 0.192 58.968 ;
    END
  END d[305]
  PIN d[306]
    DIRECTION INPUT ;
    USE SIGNAL ;
    PORT
      LAYER M4 ;
        RECT  0 59.136 0.192 59.16 ;
    END
  END d[306]
  PIN d[307]
    DIRECTION INPUT ;
    USE SIGNAL ;
    PORT
      LAYER M4 ;
        RECT  0 59.328 0.192 59.352 ;
    END
  END d[307]
  PIN d[308]
    DIRECTION INPUT ;
    USE SIGNAL ;
    PORT
      LAYER M4 ;
        RECT  0 59.52 0.192 59.544 ;
    END
  END d[308]
  PIN d[309]
    DIRECTION INPUT ;
    USE SIGNAL ;
    PORT
      LAYER M4 ;
        RECT  0 59.712 0.192 59.736 ;
    END
  END d[309]
  PIN d[30]
    DIRECTION INPUT ;
    USE SIGNAL ;
    PORT
      LAYER M4 ;
        RECT  0 6.144 0.192 6.168 ;
    END
  END d[30]
  PIN d[310]
    DIRECTION INPUT ;
    USE SIGNAL ;
    PORT
      LAYER M4 ;
        RECT  0 59.904 0.192 59.928 ;
    END
  END d[310]
  PIN d[311]
    DIRECTION INPUT ;
    USE SIGNAL ;
    PORT
      LAYER M4 ;
        RECT  0 60.096 0.192 60.12 ;
    END
  END d[311]
  PIN d[312]
    DIRECTION INPUT ;
    USE SIGNAL ;
    PORT
      LAYER M4 ;
        RECT  0 60.288 0.192 60.312 ;
    END
  END d[312]
  PIN d[313]
    DIRECTION INPUT ;
    USE SIGNAL ;
    PORT
      LAYER M4 ;
        RECT  0 60.48 0.192 60.504 ;
    END
  END d[313]
  PIN d[314]
    DIRECTION INPUT ;
    USE SIGNAL ;
    PORT
      LAYER M4 ;
        RECT  0 60.672 0.192 60.696 ;
    END
  END d[314]
  PIN d[315]
    DIRECTION INPUT ;
    USE SIGNAL ;
    PORT
      LAYER M4 ;
        RECT  0 60.864 0.192 60.888 ;
    END
  END d[315]
  PIN d[316]
    DIRECTION INPUT ;
    USE SIGNAL ;
    PORT
      LAYER M4 ;
        RECT  0 61.056 0.192 61.08 ;
    END
  END d[316]
  PIN d[317]
    DIRECTION INPUT ;
    USE SIGNAL ;
    PORT
      LAYER M4 ;
        RECT  0 61.248 0.192 61.272 ;
    END
  END d[317]
  PIN d[318]
    DIRECTION INPUT ;
    USE SIGNAL ;
    PORT
      LAYER M4 ;
        RECT  0 61.44 0.192 61.464 ;
    END
  END d[318]
  PIN d[319]
    DIRECTION INPUT ;
    USE SIGNAL ;
    PORT
      LAYER M4 ;
        RECT  0 61.632 0.192 61.656 ;
    END
  END d[319]
  PIN d[31]
    DIRECTION INPUT ;
    USE SIGNAL ;
    PORT
      LAYER M4 ;
        RECT  0 6.336 0.192 6.36 ;
    END
  END d[31]
  PIN d[320]
    DIRECTION INPUT ;
    USE SIGNAL ;
    PORT
      LAYER M4 ;
        RECT  0 61.824 0.192 61.848 ;
    END
  END d[320]
  PIN d[321]
    DIRECTION INPUT ;
    USE SIGNAL ;
    PORT
      LAYER M4 ;
        RECT  0 62.016 0.192 62.04 ;
    END
  END d[321]
  PIN d[322]
    DIRECTION INPUT ;
    USE SIGNAL ;
    PORT
      LAYER M4 ;
        RECT  0 62.208 0.192 62.232 ;
    END
  END d[322]
  PIN d[323]
    DIRECTION INPUT ;
    USE SIGNAL ;
    PORT
      LAYER M4 ;
        RECT  0 62.4 0.192 62.424 ;
    END
  END d[323]
  PIN d[324]
    DIRECTION INPUT ;
    USE SIGNAL ;
    PORT
      LAYER M4 ;
        RECT  0 62.592 0.192 62.616 ;
    END
  END d[324]
  PIN d[325]
    DIRECTION INPUT ;
    USE SIGNAL ;
    PORT
      LAYER M4 ;
        RECT  0 62.784 0.192 62.808 ;
    END
  END d[325]
  PIN d[326]
    DIRECTION INPUT ;
    USE SIGNAL ;
    PORT
      LAYER M4 ;
        RECT  0 62.976 0.192 63 ;
    END
  END d[326]
  PIN d[327]
    DIRECTION INPUT ;
    USE SIGNAL ;
    PORT
      LAYER M4 ;
        RECT  0 63.168 0.192 63.192 ;
    END
  END d[327]
  PIN d[328]
    DIRECTION INPUT ;
    USE SIGNAL ;
    PORT
      LAYER M4 ;
        RECT  0 63.36 0.192 63.384 ;
    END
  END d[328]
  PIN d[329]
    DIRECTION INPUT ;
    USE SIGNAL ;
    PORT
      LAYER M4 ;
        RECT  0 63.552 0.192 63.576 ;
    END
  END d[329]
  PIN d[32]
    DIRECTION INPUT ;
    USE SIGNAL ;
    PORT
      LAYER M4 ;
        RECT  0 6.528 0.192 6.552 ;
    END
  END d[32]
  PIN d[330]
    DIRECTION INPUT ;
    USE SIGNAL ;
    PORT
      LAYER M4 ;
        RECT  0 63.744 0.192 63.768 ;
    END
  END d[330]
  PIN d[331]
    DIRECTION INPUT ;
    USE SIGNAL ;
    PORT
      LAYER M4 ;
        RECT  0 63.936 0.192 63.96 ;
    END
  END d[331]
  PIN d[332]
    DIRECTION INPUT ;
    USE SIGNAL ;
    PORT
      LAYER M4 ;
        RECT  0 64.128 0.192 64.152 ;
    END
  END d[332]
  PIN d[333]
    DIRECTION INPUT ;
    USE SIGNAL ;
    PORT
      LAYER M4 ;
        RECT  0 64.32 0.192 64.344 ;
    END
  END d[333]
  PIN d[334]
    DIRECTION INPUT ;
    USE SIGNAL ;
    PORT
      LAYER M4 ;
        RECT  0 64.512 0.192 64.536 ;
    END
  END d[334]
  PIN d[335]
    DIRECTION INPUT ;
    USE SIGNAL ;
    PORT
      LAYER M4 ;
        RECT  0 64.704 0.192 64.728 ;
    END
  END d[335]
  PIN d[336]
    DIRECTION INPUT ;
    USE SIGNAL ;
    PORT
      LAYER M4 ;
        RECT  0 64.896 0.192 64.92 ;
    END
  END d[336]
  PIN d[337]
    DIRECTION INPUT ;
    USE SIGNAL ;
    PORT
      LAYER M4 ;
        RECT  0 65.088 0.192 65.112 ;
    END
  END d[337]
  PIN d[338]
    DIRECTION INPUT ;
    USE SIGNAL ;
    PORT
      LAYER M4 ;
        RECT  0 65.28 0.192 65.304 ;
    END
  END d[338]
  PIN d[339]
    DIRECTION INPUT ;
    USE SIGNAL ;
    PORT
      LAYER M4 ;
        RECT  0 65.472 0.192 65.496 ;
    END
  END d[339]
  PIN d[33]
    DIRECTION INPUT ;
    USE SIGNAL ;
    PORT
      LAYER M4 ;
        RECT  0 6.72 0.192 6.744 ;
    END
  END d[33]
  PIN d[340]
    DIRECTION INPUT ;
    USE SIGNAL ;
    PORT
      LAYER M4 ;
        RECT  0 65.664 0.192 65.688 ;
    END
  END d[340]
  PIN d[341]
    DIRECTION INPUT ;
    USE SIGNAL ;
    PORT
      LAYER M4 ;
        RECT  0 65.856 0.192 65.88 ;
    END
  END d[341]
  PIN d[342]
    DIRECTION INPUT ;
    USE SIGNAL ;
    PORT
      LAYER M4 ;
        RECT  0 66.048 0.192 66.072 ;
    END
  END d[342]
  PIN d[343]
    DIRECTION INPUT ;
    USE SIGNAL ;
    PORT
      LAYER M4 ;
        RECT  0 66.24 0.192 66.264 ;
    END
  END d[343]
  PIN d[344]
    DIRECTION INPUT ;
    USE SIGNAL ;
    PORT
      LAYER M4 ;
        RECT  0 66.432 0.192 66.456 ;
    END
  END d[344]
  PIN d[345]
    DIRECTION INPUT ;
    USE SIGNAL ;
    PORT
      LAYER M4 ;
        RECT  0 66.624 0.192 66.648 ;
    END
  END d[345]
  PIN d[346]
    DIRECTION INPUT ;
    USE SIGNAL ;
    PORT
      LAYER M4 ;
        RECT  0 66.816 0.192 66.84 ;
    END
  END d[346]
  PIN d[347]
    DIRECTION INPUT ;
    USE SIGNAL ;
    PORT
      LAYER M4 ;
        RECT  0 67.008 0.192 67.032 ;
    END
  END d[347]
  PIN d[348]
    DIRECTION INPUT ;
    USE SIGNAL ;
    PORT
      LAYER M4 ;
        RECT  0 67.2 0.192 67.224 ;
    END
  END d[348]
  PIN d[349]
    DIRECTION INPUT ;
    USE SIGNAL ;
    PORT
      LAYER M4 ;
        RECT  0 67.392 0.192 67.416 ;
    END
  END d[349]
  PIN d[34]
    DIRECTION INPUT ;
    USE SIGNAL ;
    PORT
      LAYER M4 ;
        RECT  0 6.912 0.192 6.936 ;
    END
  END d[34]
  PIN d[350]
    DIRECTION INPUT ;
    USE SIGNAL ;
    PORT
      LAYER M4 ;
        RECT  0 67.584 0.192 67.608 ;
    END
  END d[350]
  PIN d[351]
    DIRECTION INPUT ;
    USE SIGNAL ;
    PORT
      LAYER M4 ;
        RECT  0 67.776 0.192 67.8 ;
    END
  END d[351]
  PIN d[352]
    DIRECTION INPUT ;
    USE SIGNAL ;
    PORT
      LAYER M4 ;
        RECT  0 67.968 0.192 67.992 ;
    END
  END d[352]
  PIN d[353]
    DIRECTION INPUT ;
    USE SIGNAL ;
    PORT
      LAYER M4 ;
        RECT  0 68.16 0.192 68.184 ;
    END
  END d[353]
  PIN d[354]
    DIRECTION INPUT ;
    USE SIGNAL ;
    PORT
      LAYER M4 ;
        RECT  0 68.352 0.192 68.376 ;
    END
  END d[354]
  PIN d[355]
    DIRECTION INPUT ;
    USE SIGNAL ;
    PORT
      LAYER M4 ;
        RECT  0 68.544 0.192 68.568 ;
    END
  END d[355]
  PIN d[356]
    DIRECTION INPUT ;
    USE SIGNAL ;
    PORT
      LAYER M4 ;
        RECT  0 68.736 0.192 68.76 ;
    END
  END d[356]
  PIN d[357]
    DIRECTION INPUT ;
    USE SIGNAL ;
    PORT
      LAYER M4 ;
        RECT  0 68.928 0.192 68.952 ;
    END
  END d[357]
  PIN d[358]
    DIRECTION INPUT ;
    USE SIGNAL ;
    PORT
      LAYER M4 ;
        RECT  0 69.12 0.192 69.144 ;
    END
  END d[358]
  PIN d[359]
    DIRECTION INPUT ;
    USE SIGNAL ;
    PORT
      LAYER M4 ;
        RECT  0 69.312 0.192 69.336 ;
    END
  END d[359]
  PIN d[35]
    DIRECTION INPUT ;
    USE SIGNAL ;
    PORT
      LAYER M4 ;
        RECT  0 7.104 0.192 7.128 ;
    END
  END d[35]
  PIN d[360]
    DIRECTION INPUT ;
    USE SIGNAL ;
    PORT
      LAYER M4 ;
        RECT  0 69.504 0.192 69.528 ;
    END
  END d[360]
  PIN d[361]
    DIRECTION INPUT ;
    USE SIGNAL ;
    PORT
      LAYER M4 ;
        RECT  0 69.696 0.192 69.72 ;
    END
  END d[361]
  PIN d[362]
    DIRECTION INPUT ;
    USE SIGNAL ;
    PORT
      LAYER M4 ;
        RECT  0 69.888 0.192 69.912 ;
    END
  END d[362]
  PIN d[363]
    DIRECTION INPUT ;
    USE SIGNAL ;
    PORT
      LAYER M4 ;
        RECT  0 70.08 0.192 70.104 ;
    END
  END d[363]
  PIN d[364]
    DIRECTION INPUT ;
    USE SIGNAL ;
    PORT
      LAYER M4 ;
        RECT  0 70.272 0.192 70.296 ;
    END
  END d[364]
  PIN d[365]
    DIRECTION INPUT ;
    USE SIGNAL ;
    PORT
      LAYER M4 ;
        RECT  0 70.464 0.192 70.488 ;
    END
  END d[365]
  PIN d[366]
    DIRECTION INPUT ;
    USE SIGNAL ;
    PORT
      LAYER M4 ;
        RECT  0 70.656 0.192 70.68 ;
    END
  END d[366]
  PIN d[367]
    DIRECTION INPUT ;
    USE SIGNAL ;
    PORT
      LAYER M4 ;
        RECT  0 70.848 0.192 70.872 ;
    END
  END d[367]
  PIN d[368]
    DIRECTION INPUT ;
    USE SIGNAL ;
    PORT
      LAYER M4 ;
        RECT  0 71.04 0.192 71.064 ;
    END
  END d[368]
  PIN d[369]
    DIRECTION INPUT ;
    USE SIGNAL ;
    PORT
      LAYER M4 ;
        RECT  0 71.232 0.192 71.256 ;
    END
  END d[369]
  PIN d[36]
    DIRECTION INPUT ;
    USE SIGNAL ;
    PORT
      LAYER M4 ;
        RECT  0 7.296 0.192 7.32 ;
    END
  END d[36]
  PIN d[370]
    DIRECTION INPUT ;
    USE SIGNAL ;
    PORT
      LAYER M4 ;
        RECT  0 71.424 0.192 71.448 ;
    END
  END d[370]
  PIN d[371]
    DIRECTION INPUT ;
    USE SIGNAL ;
    PORT
      LAYER M4 ;
        RECT  0 71.616 0.192 71.64 ;
    END
  END d[371]
  PIN d[372]
    DIRECTION INPUT ;
    USE SIGNAL ;
    PORT
      LAYER M4 ;
        RECT  0 71.808 0.192 71.832 ;
    END
  END d[372]
  PIN d[373]
    DIRECTION INPUT ;
    USE SIGNAL ;
    PORT
      LAYER M4 ;
        RECT  0 72 0.192 72.024 ;
    END
  END d[373]
  PIN d[374]
    DIRECTION INPUT ;
    USE SIGNAL ;
    PORT
      LAYER M4 ;
        RECT  0 72.192 0.192 72.216 ;
    END
  END d[374]
  PIN d[375]
    DIRECTION INPUT ;
    USE SIGNAL ;
    PORT
      LAYER M4 ;
        RECT  0 72.384 0.192 72.408 ;
    END
  END d[375]
  PIN d[376]
    DIRECTION INPUT ;
    USE SIGNAL ;
    PORT
      LAYER M4 ;
        RECT  0 72.576 0.192 72.6 ;
    END
  END d[376]
  PIN d[377]
    DIRECTION INPUT ;
    USE SIGNAL ;
    PORT
      LAYER M4 ;
        RECT  0 72.768 0.192 72.792 ;
    END
  END d[377]
  PIN d[378]
    DIRECTION INPUT ;
    USE SIGNAL ;
    PORT
      LAYER M4 ;
        RECT  0 72.96 0.192 72.984 ;
    END
  END d[378]
  PIN d[379]
    DIRECTION INPUT ;
    USE SIGNAL ;
    PORT
      LAYER M4 ;
        RECT  0 73.152 0.192 73.176 ;
    END
  END d[379]
  PIN d[37]
    DIRECTION INPUT ;
    USE SIGNAL ;
    PORT
      LAYER M4 ;
        RECT  0 7.488 0.192 7.512 ;
    END
  END d[37]
  PIN d[380]
    DIRECTION INPUT ;
    USE SIGNAL ;
    PORT
      LAYER M4 ;
        RECT  0 73.344 0.192 73.368 ;
    END
  END d[380]
  PIN d[381]
    DIRECTION INPUT ;
    USE SIGNAL ;
    PORT
      LAYER M4 ;
        RECT  0 73.536 0.192 73.56 ;
    END
  END d[381]
  PIN d[382]
    DIRECTION INPUT ;
    USE SIGNAL ;
    PORT
      LAYER M4 ;
        RECT  0 73.728 0.192 73.752 ;
    END
  END d[382]
  PIN d[383]
    DIRECTION INPUT ;
    USE SIGNAL ;
    PORT
      LAYER M4 ;
        RECT  0 73.92 0.192 73.944 ;
    END
  END d[383]
  PIN d[384]
    DIRECTION INPUT ;
    USE SIGNAL ;
    PORT
      LAYER M4 ;
        RECT  0 74.112 0.192 74.136 ;
    END
  END d[384]
  PIN d[385]
    DIRECTION INPUT ;
    USE SIGNAL ;
    PORT
      LAYER M4 ;
        RECT  0 74.304 0.192 74.328 ;
    END
  END d[385]
  PIN d[386]
    DIRECTION INPUT ;
    USE SIGNAL ;
    PORT
      LAYER M4 ;
        RECT  0 74.496 0.192 74.52 ;
    END
  END d[386]
  PIN d[387]
    DIRECTION INPUT ;
    USE SIGNAL ;
    PORT
      LAYER M4 ;
        RECT  0 74.688 0.192 74.712 ;
    END
  END d[387]
  PIN d[388]
    DIRECTION INPUT ;
    USE SIGNAL ;
    PORT
      LAYER M4 ;
        RECT  0 74.88 0.192 74.904 ;
    END
  END d[388]
  PIN d[389]
    DIRECTION INPUT ;
    USE SIGNAL ;
    PORT
      LAYER M4 ;
        RECT  0 75.072 0.192 75.096 ;
    END
  END d[389]
  PIN d[38]
    DIRECTION INPUT ;
    USE SIGNAL ;
    PORT
      LAYER M4 ;
        RECT  0 7.68 0.192 7.704 ;
    END
  END d[38]
  PIN d[390]
    DIRECTION INPUT ;
    USE SIGNAL ;
    PORT
      LAYER M4 ;
        RECT  0 75.264 0.192 75.288 ;
    END
  END d[390]
  PIN d[391]
    DIRECTION INPUT ;
    USE SIGNAL ;
    PORT
      LAYER M4 ;
        RECT  0 75.456 0.192 75.48 ;
    END
  END d[391]
  PIN d[392]
    DIRECTION INPUT ;
    USE SIGNAL ;
    PORT
      LAYER M4 ;
        RECT  0 75.648 0.192 75.672 ;
    END
  END d[392]
  PIN d[393]
    DIRECTION INPUT ;
    USE SIGNAL ;
    PORT
      LAYER M4 ;
        RECT  0 75.84 0.192 75.864 ;
    END
  END d[393]
  PIN d[394]
    DIRECTION INPUT ;
    USE SIGNAL ;
    PORT
      LAYER M4 ;
        RECT  0 76.032 0.192 76.056 ;
    END
  END d[394]
  PIN d[395]
    DIRECTION INPUT ;
    USE SIGNAL ;
    PORT
      LAYER M4 ;
        RECT  0 76.224 0.192 76.248 ;
    END
  END d[395]
  PIN d[396]
    DIRECTION INPUT ;
    USE SIGNAL ;
    PORT
      LAYER M4 ;
        RECT  0 76.416 0.192 76.44 ;
    END
  END d[396]
  PIN d[397]
    DIRECTION INPUT ;
    USE SIGNAL ;
    PORT
      LAYER M4 ;
        RECT  0 76.608 0.192 76.632 ;
    END
  END d[397]
  PIN d[398]
    DIRECTION INPUT ;
    USE SIGNAL ;
    PORT
      LAYER M4 ;
        RECT  0 76.8 0.192 76.824 ;
    END
  END d[398]
  PIN d[399]
    DIRECTION INPUT ;
    USE SIGNAL ;
    PORT
      LAYER M4 ;
        RECT  0 76.992 0.192 77.016 ;
    END
  END d[399]
  PIN d[39]
    DIRECTION INPUT ;
    USE SIGNAL ;
    PORT
      LAYER M4 ;
        RECT  0 7.872 0.192 7.896 ;
    END
  END d[39]
  PIN d[3]
    DIRECTION INPUT ;
    USE SIGNAL ;
    PORT
      LAYER M4 ;
        RECT  0 0.96 0.192 0.984 ;
    END
  END d[3]
  PIN d[400]
    DIRECTION INPUT ;
    USE SIGNAL ;
    PORT
      LAYER M4 ;
        RECT  0 77.184 0.192 77.208 ;
    END
  END d[400]
  PIN d[401]
    DIRECTION INPUT ;
    USE SIGNAL ;
    PORT
      LAYER M4 ;
        RECT  0 77.376 0.192 77.4 ;
    END
  END d[401]
  PIN d[402]
    DIRECTION INPUT ;
    USE SIGNAL ;
    PORT
      LAYER M4 ;
        RECT  0 77.568 0.192 77.592 ;
    END
  END d[402]
  PIN d[403]
    DIRECTION INPUT ;
    USE SIGNAL ;
    PORT
      LAYER M4 ;
        RECT  0 77.76 0.192 77.784 ;
    END
  END d[403]
  PIN d[404]
    DIRECTION INPUT ;
    USE SIGNAL ;
    PORT
      LAYER M4 ;
        RECT  0 77.952 0.192 77.976 ;
    END
  END d[404]
  PIN d[405]
    DIRECTION INPUT ;
    USE SIGNAL ;
    PORT
      LAYER M4 ;
        RECT  0 78.144 0.192 78.168 ;
    END
  END d[405]
  PIN d[406]
    DIRECTION INPUT ;
    USE SIGNAL ;
    PORT
      LAYER M4 ;
        RECT  0 78.336 0.192 78.36 ;
    END
  END d[406]
  PIN d[407]
    DIRECTION INPUT ;
    USE SIGNAL ;
    PORT
      LAYER M4 ;
        RECT  0 78.528 0.192 78.552 ;
    END
  END d[407]
  PIN d[408]
    DIRECTION INPUT ;
    USE SIGNAL ;
    PORT
      LAYER M4 ;
        RECT  0 78.72 0.192 78.744 ;
    END
  END d[408]
  PIN d[409]
    DIRECTION INPUT ;
    USE SIGNAL ;
    PORT
      LAYER M4 ;
        RECT  0 78.912 0.192 78.936 ;
    END
  END d[409]
  PIN d[40]
    DIRECTION INPUT ;
    USE SIGNAL ;
    PORT
      LAYER M4 ;
        RECT  0 8.064 0.192 8.088 ;
    END
  END d[40]
  PIN d[410]
    DIRECTION INPUT ;
    USE SIGNAL ;
    PORT
      LAYER M4 ;
        RECT  0 79.104 0.192 79.128 ;
    END
  END d[410]
  PIN d[411]
    DIRECTION INPUT ;
    USE SIGNAL ;
    PORT
      LAYER M4 ;
        RECT  0 79.296 0.192 79.32 ;
    END
  END d[411]
  PIN d[412]
    DIRECTION INPUT ;
    USE SIGNAL ;
    PORT
      LAYER M4 ;
        RECT  0 79.488 0.192 79.512 ;
    END
  END d[412]
  PIN d[413]
    DIRECTION INPUT ;
    USE SIGNAL ;
    PORT
      LAYER M4 ;
        RECT  0 79.68 0.192 79.704 ;
    END
  END d[413]
  PIN d[414]
    DIRECTION INPUT ;
    USE SIGNAL ;
    PORT
      LAYER M4 ;
        RECT  0 79.872 0.192 79.896 ;
    END
  END d[414]
  PIN d[415]
    DIRECTION INPUT ;
    USE SIGNAL ;
    PORT
      LAYER M4 ;
        RECT  0 80.064 0.192 80.088 ;
    END
  END d[415]
  PIN d[416]
    DIRECTION INPUT ;
    USE SIGNAL ;
    PORT
      LAYER M4 ;
        RECT  0 80.256 0.192 80.28 ;
    END
  END d[416]
  PIN d[417]
    DIRECTION INPUT ;
    USE SIGNAL ;
    PORT
      LAYER M4 ;
        RECT  0 80.448 0.192 80.472 ;
    END
  END d[417]
  PIN d[418]
    DIRECTION INPUT ;
    USE SIGNAL ;
    PORT
      LAYER M4 ;
        RECT  0 80.64 0.192 80.664 ;
    END
  END d[418]
  PIN d[419]
    DIRECTION INPUT ;
    USE SIGNAL ;
    PORT
      LAYER M4 ;
        RECT  0 80.832 0.192 80.856 ;
    END
  END d[419]
  PIN d[41]
    DIRECTION INPUT ;
    USE SIGNAL ;
    PORT
      LAYER M4 ;
        RECT  0 8.256 0.192 8.28 ;
    END
  END d[41]
  PIN d[420]
    DIRECTION INPUT ;
    USE SIGNAL ;
    PORT
      LAYER M4 ;
        RECT  0 81.024 0.192 81.048 ;
    END
  END d[420]
  PIN d[421]
    DIRECTION INPUT ;
    USE SIGNAL ;
    PORT
      LAYER M4 ;
        RECT  0 81.216 0.192 81.24 ;
    END
  END d[421]
  PIN d[422]
    DIRECTION INPUT ;
    USE SIGNAL ;
    PORT
      LAYER M4 ;
        RECT  0 81.408 0.192 81.432 ;
    END
  END d[422]
  PIN d[423]
    DIRECTION INPUT ;
    USE SIGNAL ;
    PORT
      LAYER M4 ;
        RECT  0 81.6 0.192 81.624 ;
    END
  END d[423]
  PIN d[424]
    DIRECTION INPUT ;
    USE SIGNAL ;
    PORT
      LAYER M4 ;
        RECT  0 81.792 0.192 81.816 ;
    END
  END d[424]
  PIN d[425]
    DIRECTION INPUT ;
    USE SIGNAL ;
    PORT
      LAYER M4 ;
        RECT  0 81.984 0.192 82.008 ;
    END
  END d[425]
  PIN d[426]
    DIRECTION INPUT ;
    USE SIGNAL ;
    PORT
      LAYER M4 ;
        RECT  0 82.176 0.192 82.2 ;
    END
  END d[426]
  PIN d[427]
    DIRECTION INPUT ;
    USE SIGNAL ;
    PORT
      LAYER M4 ;
        RECT  0 82.368 0.192 82.392 ;
    END
  END d[427]
  PIN d[428]
    DIRECTION INPUT ;
    USE SIGNAL ;
    PORT
      LAYER M4 ;
        RECT  0 82.56 0.192 82.584 ;
    END
  END d[428]
  PIN d[429]
    DIRECTION INPUT ;
    USE SIGNAL ;
    PORT
      LAYER M4 ;
        RECT  0 82.752 0.192 82.776 ;
    END
  END d[429]
  PIN d[42]
    DIRECTION INPUT ;
    USE SIGNAL ;
    PORT
      LAYER M4 ;
        RECT  0 8.448 0.192 8.472 ;
    END
  END d[42]
  PIN d[430]
    DIRECTION INPUT ;
    USE SIGNAL ;
    PORT
      LAYER M4 ;
        RECT  0 82.944 0.192 82.968 ;
    END
  END d[430]
  PIN d[431]
    DIRECTION INPUT ;
    USE SIGNAL ;
    PORT
      LAYER M4 ;
        RECT  0 83.136 0.192 83.16 ;
    END
  END d[431]
  PIN d[432]
    DIRECTION INPUT ;
    USE SIGNAL ;
    PORT
      LAYER M4 ;
        RECT  0 83.328 0.192 83.352 ;
    END
  END d[432]
  PIN d[433]
    DIRECTION INPUT ;
    USE SIGNAL ;
    PORT
      LAYER M4 ;
        RECT  0 83.52 0.192 83.544 ;
    END
  END d[433]
  PIN d[434]
    DIRECTION INPUT ;
    USE SIGNAL ;
    PORT
      LAYER M4 ;
        RECT  0 83.712 0.192 83.736 ;
    END
  END d[434]
  PIN d[435]
    DIRECTION INPUT ;
    USE SIGNAL ;
    PORT
      LAYER M4 ;
        RECT  0 83.904 0.192 83.928 ;
    END
  END d[435]
  PIN d[436]
    DIRECTION INPUT ;
    USE SIGNAL ;
    PORT
      LAYER M4 ;
        RECT  0 84.096 0.192 84.12 ;
    END
  END d[436]
  PIN d[437]
    DIRECTION INPUT ;
    USE SIGNAL ;
    PORT
      LAYER M4 ;
        RECT  0 84.288 0.192 84.312 ;
    END
  END d[437]
  PIN d[438]
    DIRECTION INPUT ;
    USE SIGNAL ;
    PORT
      LAYER M4 ;
        RECT  0 84.48 0.192 84.504 ;
    END
  END d[438]
  PIN d[439]
    DIRECTION INPUT ;
    USE SIGNAL ;
    PORT
      LAYER M4 ;
        RECT  0 84.672 0.192 84.696 ;
    END
  END d[439]
  PIN d[43]
    DIRECTION INPUT ;
    USE SIGNAL ;
    PORT
      LAYER M4 ;
        RECT  0 8.64 0.192 8.664 ;
    END
  END d[43]
  PIN d[440]
    DIRECTION INPUT ;
    USE SIGNAL ;
    PORT
      LAYER M4 ;
        RECT  0 84.864 0.192 84.888 ;
    END
  END d[440]
  PIN d[441]
    DIRECTION INPUT ;
    USE SIGNAL ;
    PORT
      LAYER M4 ;
        RECT  0 85.056 0.192 85.08 ;
    END
  END d[441]
  PIN d[442]
    DIRECTION INPUT ;
    USE SIGNAL ;
    PORT
      LAYER M4 ;
        RECT  0 85.248 0.192 85.272 ;
    END
  END d[442]
  PIN d[443]
    DIRECTION INPUT ;
    USE SIGNAL ;
    PORT
      LAYER M4 ;
        RECT  0 85.44 0.192 85.464 ;
    END
  END d[443]
  PIN d[444]
    DIRECTION INPUT ;
    USE SIGNAL ;
    PORT
      LAYER M4 ;
        RECT  0 85.632 0.192 85.656 ;
    END
  END d[444]
  PIN d[445]
    DIRECTION INPUT ;
    USE SIGNAL ;
    PORT
      LAYER M4 ;
        RECT  0 85.824 0.192 85.848 ;
    END
  END d[445]
  PIN d[446]
    DIRECTION INPUT ;
    USE SIGNAL ;
    PORT
      LAYER M4 ;
        RECT  0 86.016 0.192 86.04 ;
    END
  END d[446]
  PIN d[447]
    DIRECTION INPUT ;
    USE SIGNAL ;
    PORT
      LAYER M4 ;
        RECT  0 86.208 0.192 86.232 ;
    END
  END d[447]
  PIN d[448]
    DIRECTION INPUT ;
    USE SIGNAL ;
    PORT
      LAYER M4 ;
        RECT  0 86.4 0.192 86.424 ;
    END
  END d[448]
  PIN d[449]
    DIRECTION INPUT ;
    USE SIGNAL ;
    PORT
      LAYER M4 ;
        RECT  0 86.592 0.192 86.616 ;
    END
  END d[449]
  PIN d[44]
    DIRECTION INPUT ;
    USE SIGNAL ;
    PORT
      LAYER M4 ;
        RECT  0 8.832 0.192 8.856 ;
    END
  END d[44]
  PIN d[450]
    DIRECTION INPUT ;
    USE SIGNAL ;
    PORT
      LAYER M4 ;
        RECT  0 86.784 0.192 86.808 ;
    END
  END d[450]
  PIN d[451]
    DIRECTION INPUT ;
    USE SIGNAL ;
    PORT
      LAYER M4 ;
        RECT  0 86.976 0.192 87 ;
    END
  END d[451]
  PIN d[452]
    DIRECTION INPUT ;
    USE SIGNAL ;
    PORT
      LAYER M4 ;
        RECT  0 87.168 0.192 87.192 ;
    END
  END d[452]
  PIN d[453]
    DIRECTION INPUT ;
    USE SIGNAL ;
    PORT
      LAYER M4 ;
        RECT  0 87.36 0.192 87.384 ;
    END
  END d[453]
  PIN d[454]
    DIRECTION INPUT ;
    USE SIGNAL ;
    PORT
      LAYER M4 ;
        RECT  0 87.552 0.192 87.576 ;
    END
  END d[454]
  PIN d[455]
    DIRECTION INPUT ;
    USE SIGNAL ;
    PORT
      LAYER M4 ;
        RECT  0 87.744 0.192 87.768 ;
    END
  END d[455]
  PIN d[456]
    DIRECTION INPUT ;
    USE SIGNAL ;
    PORT
      LAYER M4 ;
        RECT  0 87.936 0.192 87.96 ;
    END
  END d[456]
  PIN d[457]
    DIRECTION INPUT ;
    USE SIGNAL ;
    PORT
      LAYER M4 ;
        RECT  0 88.128 0.192 88.152 ;
    END
  END d[457]
  PIN d[458]
    DIRECTION INPUT ;
    USE SIGNAL ;
    PORT
      LAYER M4 ;
        RECT  0 88.32 0.192 88.344 ;
    END
  END d[458]
  PIN d[459]
    DIRECTION INPUT ;
    USE SIGNAL ;
    PORT
      LAYER M4 ;
        RECT  0 88.512 0.192 88.536 ;
    END
  END d[459]
  PIN d[45]
    DIRECTION INPUT ;
    USE SIGNAL ;
    PORT
      LAYER M4 ;
        RECT  0 9.024 0.192 9.048 ;
    END
  END d[45]
  PIN d[460]
    DIRECTION INPUT ;
    USE SIGNAL ;
    PORT
      LAYER M4 ;
        RECT  0 88.704 0.192 88.728 ;
    END
  END d[460]
  PIN d[461]
    DIRECTION INPUT ;
    USE SIGNAL ;
    PORT
      LAYER M4 ;
        RECT  0 88.896 0.192 88.92 ;
    END
  END d[461]
  PIN d[462]
    DIRECTION INPUT ;
    USE SIGNAL ;
    PORT
      LAYER M4 ;
        RECT  0 89.088 0.192 89.112 ;
    END
  END d[462]
  PIN d[463]
    DIRECTION INPUT ;
    USE SIGNAL ;
    PORT
      LAYER M4 ;
        RECT  0 89.28 0.192 89.304 ;
    END
  END d[463]
  PIN d[464]
    DIRECTION INPUT ;
    USE SIGNAL ;
    PORT
      LAYER M4 ;
        RECT  0 89.472 0.192 89.496 ;
    END
  END d[464]
  PIN d[465]
    DIRECTION INPUT ;
    USE SIGNAL ;
    PORT
      LAYER M4 ;
        RECT  0 89.664 0.192 89.688 ;
    END
  END d[465]
  PIN d[466]
    DIRECTION INPUT ;
    USE SIGNAL ;
    PORT
      LAYER M4 ;
        RECT  0 89.856 0.192 89.88 ;
    END
  END d[466]
  PIN d[467]
    DIRECTION INPUT ;
    USE SIGNAL ;
    PORT
      LAYER M4 ;
        RECT  0 90.048 0.192 90.072 ;
    END
  END d[467]
  PIN d[468]
    DIRECTION INPUT ;
    USE SIGNAL ;
    PORT
      LAYER M4 ;
        RECT  0 90.24 0.192 90.264 ;
    END
  END d[468]
  PIN d[469]
    DIRECTION INPUT ;
    USE SIGNAL ;
    PORT
      LAYER M4 ;
        RECT  0 90.432 0.192 90.456 ;
    END
  END d[469]
  PIN d[46]
    DIRECTION INPUT ;
    USE SIGNAL ;
    PORT
      LAYER M4 ;
        RECT  0 9.216 0.192 9.24 ;
    END
  END d[46]
  PIN d[470]
    DIRECTION INPUT ;
    USE SIGNAL ;
    PORT
      LAYER M4 ;
        RECT  0 90.624 0.192 90.648 ;
    END
  END d[470]
  PIN d[471]
    DIRECTION INPUT ;
    USE SIGNAL ;
    PORT
      LAYER M4 ;
        RECT  0 90.816 0.192 90.84 ;
    END
  END d[471]
  PIN d[472]
    DIRECTION INPUT ;
    USE SIGNAL ;
    PORT
      LAYER M4 ;
        RECT  0 91.008 0.192 91.032 ;
    END
  END d[472]
  PIN d[473]
    DIRECTION INPUT ;
    USE SIGNAL ;
    PORT
      LAYER M4 ;
        RECT  0 91.2 0.192 91.224 ;
    END
  END d[473]
  PIN d[474]
    DIRECTION INPUT ;
    USE SIGNAL ;
    PORT
      LAYER M4 ;
        RECT  0 91.392 0.192 91.416 ;
    END
  END d[474]
  PIN d[475]
    DIRECTION INPUT ;
    USE SIGNAL ;
    PORT
      LAYER M4 ;
        RECT  0 91.584 0.192 91.608 ;
    END
  END d[475]
  PIN d[476]
    DIRECTION INPUT ;
    USE SIGNAL ;
    PORT
      LAYER M4 ;
        RECT  0 91.776 0.192 91.8 ;
    END
  END d[476]
  PIN d[477]
    DIRECTION INPUT ;
    USE SIGNAL ;
    PORT
      LAYER M4 ;
        RECT  0 91.968 0.192 91.992 ;
    END
  END d[477]
  PIN d[478]
    DIRECTION INPUT ;
    USE SIGNAL ;
    PORT
      LAYER M4 ;
        RECT  0 92.16 0.192 92.184 ;
    END
  END d[478]
  PIN d[479]
    DIRECTION INPUT ;
    USE SIGNAL ;
    PORT
      LAYER M4 ;
        RECT  0 92.352 0.192 92.376 ;
    END
  END d[479]
  PIN d[47]
    DIRECTION INPUT ;
    USE SIGNAL ;
    PORT
      LAYER M4 ;
        RECT  0 9.408 0.192 9.432 ;
    END
  END d[47]
  PIN d[480]
    DIRECTION INPUT ;
    USE SIGNAL ;
    PORT
      LAYER M4 ;
        RECT  0 92.544 0.192 92.568 ;
    END
  END d[480]
  PIN d[481]
    DIRECTION INPUT ;
    USE SIGNAL ;
    PORT
      LAYER M4 ;
        RECT  0 92.736 0.192 92.76 ;
    END
  END d[481]
  PIN d[482]
    DIRECTION INPUT ;
    USE SIGNAL ;
    PORT
      LAYER M4 ;
        RECT  0 92.928 0.192 92.952 ;
    END
  END d[482]
  PIN d[483]
    DIRECTION INPUT ;
    USE SIGNAL ;
    PORT
      LAYER M4 ;
        RECT  0 93.12 0.192 93.144 ;
    END
  END d[483]
  PIN d[484]
    DIRECTION INPUT ;
    USE SIGNAL ;
    PORT
      LAYER M4 ;
        RECT  0 93.312 0.192 93.336 ;
    END
  END d[484]
  PIN d[485]
    DIRECTION INPUT ;
    USE SIGNAL ;
    PORT
      LAYER M4 ;
        RECT  0 93.504 0.192 93.528 ;
    END
  END d[485]
  PIN d[486]
    DIRECTION INPUT ;
    USE SIGNAL ;
    PORT
      LAYER M4 ;
        RECT  0 93.696 0.192 93.72 ;
    END
  END d[486]
  PIN d[487]
    DIRECTION INPUT ;
    USE SIGNAL ;
    PORT
      LAYER M4 ;
        RECT  0 93.888 0.192 93.912 ;
    END
  END d[487]
  PIN d[488]
    DIRECTION INPUT ;
    USE SIGNAL ;
    PORT
      LAYER M4 ;
        RECT  0 94.08 0.192 94.104 ;
    END
  END d[488]
  PIN d[489]
    DIRECTION INPUT ;
    USE SIGNAL ;
    PORT
      LAYER M4 ;
        RECT  0 94.272 0.192 94.296 ;
    END
  END d[489]
  PIN d[48]
    DIRECTION INPUT ;
    USE SIGNAL ;
    PORT
      LAYER M4 ;
        RECT  0 9.6 0.192 9.624 ;
    END
  END d[48]
  PIN d[490]
    DIRECTION INPUT ;
    USE SIGNAL ;
    PORT
      LAYER M4 ;
        RECT  0 94.464 0.192 94.488 ;
    END
  END d[490]
  PIN d[491]
    DIRECTION INPUT ;
    USE SIGNAL ;
    PORT
      LAYER M4 ;
        RECT  0 94.656 0.192 94.68 ;
    END
  END d[491]
  PIN d[492]
    DIRECTION INPUT ;
    USE SIGNAL ;
    PORT
      LAYER M4 ;
        RECT  0 94.848 0.192 94.872 ;
    END
  END d[492]
  PIN d[493]
    DIRECTION INPUT ;
    USE SIGNAL ;
    PORT
      LAYER M4 ;
        RECT  0 95.04 0.192 95.064 ;
    END
  END d[493]
  PIN d[494]
    DIRECTION INPUT ;
    USE SIGNAL ;
    PORT
      LAYER M4 ;
        RECT  0 95.232 0.192 95.256 ;
    END
  END d[494]
  PIN d[495]
    DIRECTION INPUT ;
    USE SIGNAL ;
    PORT
      LAYER M4 ;
        RECT  0 95.424 0.192 95.448 ;
    END
  END d[495]
  PIN d[496]
    DIRECTION INPUT ;
    USE SIGNAL ;
    PORT
      LAYER M4 ;
        RECT  0 95.616 0.192 95.64 ;
    END
  END d[496]
  PIN d[497]
    DIRECTION INPUT ;
    USE SIGNAL ;
    PORT
      LAYER M4 ;
        RECT  0 95.808 0.192 95.832 ;
    END
  END d[497]
  PIN d[498]
    DIRECTION INPUT ;
    USE SIGNAL ;
    PORT
      LAYER M4 ;
        RECT  0 96 0.192 96.024 ;
    END
  END d[498]
  PIN d[499]
    DIRECTION INPUT ;
    USE SIGNAL ;
    PORT
      LAYER M4 ;
        RECT  0 96.192 0.192 96.216 ;
    END
  END d[499]
  PIN d[49]
    DIRECTION INPUT ;
    USE SIGNAL ;
    PORT
      LAYER M4 ;
        RECT  0 9.792 0.192 9.816 ;
    END
  END d[49]
  PIN d[4]
    DIRECTION INPUT ;
    USE SIGNAL ;
    PORT
      LAYER M4 ;
        RECT  0 1.152 0.192 1.176 ;
    END
  END d[4]
  PIN d[500]
    DIRECTION INPUT ;
    USE SIGNAL ;
    PORT
      LAYER M4 ;
        RECT  0 96.384 0.192 96.408 ;
    END
  END d[500]
  PIN d[501]
    DIRECTION INPUT ;
    USE SIGNAL ;
    PORT
      LAYER M4 ;
        RECT  0 96.576 0.192 96.6 ;
    END
  END d[501]
  PIN d[502]
    DIRECTION INPUT ;
    USE SIGNAL ;
    PORT
      LAYER M4 ;
        RECT  0 96.768 0.192 96.792 ;
    END
  END d[502]
  PIN d[503]
    DIRECTION INPUT ;
    USE SIGNAL ;
    PORT
      LAYER M4 ;
        RECT  0 96.96 0.192 96.984 ;
    END
  END d[503]
  PIN d[504]
    DIRECTION INPUT ;
    USE SIGNAL ;
    PORT
      LAYER M4 ;
        RECT  0 97.152 0.192 97.176 ;
    END
  END d[504]
  PIN d[505]
    DIRECTION INPUT ;
    USE SIGNAL ;
    PORT
      LAYER M4 ;
        RECT  0 97.344 0.192 97.368 ;
    END
  END d[505]
  PIN d[506]
    DIRECTION INPUT ;
    USE SIGNAL ;
    PORT
      LAYER M4 ;
        RECT  0 97.536 0.192 97.56 ;
    END
  END d[506]
  PIN d[507]
    DIRECTION INPUT ;
    USE SIGNAL ;
    PORT
      LAYER M4 ;
        RECT  0 97.728 0.192 97.752 ;
    END
  END d[507]
  PIN d[508]
    DIRECTION INPUT ;
    USE SIGNAL ;
    PORT
      LAYER M4 ;
        RECT  0 97.92 0.192 97.944 ;
    END
  END d[508]
  PIN d[509]
    DIRECTION INPUT ;
    USE SIGNAL ;
    PORT
      LAYER M4 ;
        RECT  0 98.112 0.192 98.136 ;
    END
  END d[509]
  PIN d[50]
    DIRECTION INPUT ;
    USE SIGNAL ;
    PORT
      LAYER M4 ;
        RECT  0 9.984 0.192 10.008 ;
    END
  END d[50]
  PIN d[510]
    DIRECTION INPUT ;
    USE SIGNAL ;
    PORT
      LAYER M4 ;
        RECT  0 98.304 0.192 98.328 ;
    END
  END d[510]
  PIN d[511]
    DIRECTION INPUT ;
    USE SIGNAL ;
    PORT
      LAYER M4 ;
        RECT  0 98.496 0.192 98.52 ;
    END
  END d[511]
  PIN d[512]
    DIRECTION INPUT ;
    USE SIGNAL ;
    PORT
      LAYER M4 ;
        RECT  0 98.688 0.192 98.712 ;
    END
  END d[512]
  PIN d[513]
    DIRECTION INPUT ;
    USE SIGNAL ;
    PORT
      LAYER M4 ;
        RECT  0 98.88 0.192 98.904 ;
    END
  END d[513]
  PIN d[514]
    DIRECTION INPUT ;
    USE SIGNAL ;
    PORT
      LAYER M4 ;
        RECT  0 99.072 0.192 99.096 ;
    END
  END d[514]
  PIN d[515]
    DIRECTION INPUT ;
    USE SIGNAL ;
    PORT
      LAYER M4 ;
        RECT  0 99.264 0.192 99.288 ;
    END
  END d[515]
  PIN d[516]
    DIRECTION INPUT ;
    USE SIGNAL ;
    PORT
      LAYER M4 ;
        RECT  0 99.456 0.192 99.48 ;
    END
  END d[516]
  PIN d[517]
    DIRECTION INPUT ;
    USE SIGNAL ;
    PORT
      LAYER M4 ;
        RECT  0 99.648 0.192 99.672 ;
    END
  END d[517]
  PIN d[518]
    DIRECTION INPUT ;
    USE SIGNAL ;
    PORT
      LAYER M4 ;
        RECT  0 99.84 0.192 99.864 ;
    END
  END d[518]
  PIN d[519]
    DIRECTION INPUT ;
    USE SIGNAL ;
    PORT
      LAYER M4 ;
        RECT  0 100.032 0.192 100.056 ;
    END
  END d[519]
  PIN d[51]
    DIRECTION INPUT ;
    USE SIGNAL ;
    PORT
      LAYER M4 ;
        RECT  0 10.176 0.192 10.2 ;
    END
  END d[51]
  PIN d[520]
    DIRECTION INPUT ;
    USE SIGNAL ;
    PORT
      LAYER M4 ;
        RECT  0 100.224 0.192 100.248 ;
    END
  END d[520]
  PIN d[521]
    DIRECTION INPUT ;
    USE SIGNAL ;
    PORT
      LAYER M4 ;
        RECT  0 100.416 0.192 100.44 ;
    END
  END d[521]
  PIN d[522]
    DIRECTION INPUT ;
    USE SIGNAL ;
    PORT
      LAYER M4 ;
        RECT  0 100.608 0.192 100.632 ;
    END
  END d[522]
  PIN d[523]
    DIRECTION INPUT ;
    USE SIGNAL ;
    PORT
      LAYER M4 ;
        RECT  0 100.8 0.192 100.824 ;
    END
  END d[523]
  PIN d[524]
    DIRECTION INPUT ;
    USE SIGNAL ;
    PORT
      LAYER M4 ;
        RECT  0 100.992 0.192 101.016 ;
    END
  END d[524]
  PIN d[525]
    DIRECTION INPUT ;
    USE SIGNAL ;
    PORT
      LAYER M4 ;
        RECT  0 101.184 0.192 101.208 ;
    END
  END d[525]
  PIN d[526]
    DIRECTION INPUT ;
    USE SIGNAL ;
    PORT
      LAYER M4 ;
        RECT  0 101.376 0.192 101.4 ;
    END
  END d[526]
  PIN d[527]
    DIRECTION INPUT ;
    USE SIGNAL ;
    PORT
      LAYER M4 ;
        RECT  0 101.568 0.192 101.592 ;
    END
  END d[527]
  PIN d[528]
    DIRECTION INPUT ;
    USE SIGNAL ;
    PORT
      LAYER M4 ;
        RECT  0 101.76 0.192 101.784 ;
    END
  END d[528]
  PIN d[529]
    DIRECTION INPUT ;
    USE SIGNAL ;
    PORT
      LAYER M4 ;
        RECT  0 101.952 0.192 101.976 ;
    END
  END d[529]
  PIN d[52]
    DIRECTION INPUT ;
    USE SIGNAL ;
    PORT
      LAYER M4 ;
        RECT  0 10.368 0.192 10.392 ;
    END
  END d[52]
  PIN d[530]
    DIRECTION INPUT ;
    USE SIGNAL ;
    PORT
      LAYER M4 ;
        RECT  0 102.144 0.192 102.168 ;
    END
  END d[530]
  PIN d[531]
    DIRECTION INPUT ;
    USE SIGNAL ;
    PORT
      LAYER M4 ;
        RECT  0 102.336 0.192 102.36 ;
    END
  END d[531]
  PIN d[532]
    DIRECTION INPUT ;
    USE SIGNAL ;
    PORT
      LAYER M4 ;
        RECT  0 102.528 0.192 102.552 ;
    END
  END d[532]
  PIN d[533]
    DIRECTION INPUT ;
    USE SIGNAL ;
    PORT
      LAYER M4 ;
        RECT  0 102.72 0.192 102.744 ;
    END
  END d[533]
  PIN d[534]
    DIRECTION INPUT ;
    USE SIGNAL ;
    PORT
      LAYER M4 ;
        RECT  0 102.912 0.192 102.936 ;
    END
  END d[534]
  PIN d[535]
    DIRECTION INPUT ;
    USE SIGNAL ;
    PORT
      LAYER M4 ;
        RECT  0 103.104 0.192 103.128 ;
    END
  END d[535]
  PIN d[536]
    DIRECTION INPUT ;
    USE SIGNAL ;
    PORT
      LAYER M4 ;
        RECT  0 103.296 0.192 103.32 ;
    END
  END d[536]
  PIN d[537]
    DIRECTION INPUT ;
    USE SIGNAL ;
    PORT
      LAYER M4 ;
        RECT  0 103.488 0.192 103.512 ;
    END
  END d[537]
  PIN d[538]
    DIRECTION INPUT ;
    USE SIGNAL ;
    PORT
      LAYER M4 ;
        RECT  0 103.68 0.192 103.704 ;
    END
  END d[538]
  PIN d[539]
    DIRECTION INPUT ;
    USE SIGNAL ;
    PORT
      LAYER M4 ;
        RECT  0 103.872 0.192 103.896 ;
    END
  END d[539]
  PIN d[53]
    DIRECTION INPUT ;
    USE SIGNAL ;
    PORT
      LAYER M4 ;
        RECT  0 10.56 0.192 10.584 ;
    END
  END d[53]
  PIN d[540]
    DIRECTION INPUT ;
    USE SIGNAL ;
    PORT
      LAYER M4 ;
        RECT  0 104.064 0.192 104.088 ;
    END
  END d[540]
  PIN d[541]
    DIRECTION INPUT ;
    USE SIGNAL ;
    PORT
      LAYER M4 ;
        RECT  0 104.256 0.192 104.28 ;
    END
  END d[541]
  PIN d[542]
    DIRECTION INPUT ;
    USE SIGNAL ;
    PORT
      LAYER M4 ;
        RECT  0 104.448 0.192 104.472 ;
    END
  END d[542]
  PIN d[543]
    DIRECTION INPUT ;
    USE SIGNAL ;
    PORT
      LAYER M4 ;
        RECT  0 104.64 0.192 104.664 ;
    END
  END d[543]
  PIN d[54]
    DIRECTION INPUT ;
    USE SIGNAL ;
    PORT
      LAYER M4 ;
        RECT  0 10.752 0.192 10.776 ;
    END
  END d[54]
  PIN d[55]
    DIRECTION INPUT ;
    USE SIGNAL ;
    PORT
      LAYER M4 ;
        RECT  0 10.944 0.192 10.968 ;
    END
  END d[55]
  PIN d[56]
    DIRECTION INPUT ;
    USE SIGNAL ;
    PORT
      LAYER M4 ;
        RECT  0 11.136 0.192 11.16 ;
    END
  END d[56]
  PIN d[57]
    DIRECTION INPUT ;
    USE SIGNAL ;
    PORT
      LAYER M4 ;
        RECT  0 11.328 0.192 11.352 ;
    END
  END d[57]
  PIN d[58]
    DIRECTION INPUT ;
    USE SIGNAL ;
    PORT
      LAYER M4 ;
        RECT  0 11.52 0.192 11.544 ;
    END
  END d[58]
  PIN d[59]
    DIRECTION INPUT ;
    USE SIGNAL ;
    PORT
      LAYER M4 ;
        RECT  0 11.712 0.192 11.736 ;
    END
  END d[59]
  PIN d[5]
    DIRECTION INPUT ;
    USE SIGNAL ;
    PORT
      LAYER M4 ;
        RECT  0 1.344 0.192 1.368 ;
    END
  END d[5]
  PIN d[60]
    DIRECTION INPUT ;
    USE SIGNAL ;
    PORT
      LAYER M4 ;
        RECT  0 11.904 0.192 11.928 ;
    END
  END d[60]
  PIN d[61]
    DIRECTION INPUT ;
    USE SIGNAL ;
    PORT
      LAYER M4 ;
        RECT  0 12.096 0.192 12.12 ;
    END
  END d[61]
  PIN d[62]
    DIRECTION INPUT ;
    USE SIGNAL ;
    PORT
      LAYER M4 ;
        RECT  0 12.288 0.192 12.312 ;
    END
  END d[62]
  PIN d[63]
    DIRECTION INPUT ;
    USE SIGNAL ;
    PORT
      LAYER M4 ;
        RECT  0 12.48 0.192 12.504 ;
    END
  END d[63]
  PIN d[64]
    DIRECTION INPUT ;
    USE SIGNAL ;
    PORT
      LAYER M4 ;
        RECT  0 12.672 0.192 12.696 ;
    END
  END d[64]
  PIN d[65]
    DIRECTION INPUT ;
    USE SIGNAL ;
    PORT
      LAYER M4 ;
        RECT  0 12.864 0.192 12.888 ;
    END
  END d[65]
  PIN d[66]
    DIRECTION INPUT ;
    USE SIGNAL ;
    PORT
      LAYER M4 ;
        RECT  0 13.056 0.192 13.08 ;
    END
  END d[66]
  PIN d[67]
    DIRECTION INPUT ;
    USE SIGNAL ;
    PORT
      LAYER M4 ;
        RECT  0 13.248 0.192 13.272 ;
    END
  END d[67]
  PIN d[68]
    DIRECTION INPUT ;
    USE SIGNAL ;
    PORT
      LAYER M4 ;
        RECT  0 13.44 0.192 13.464 ;
    END
  END d[68]
  PIN d[69]
    DIRECTION INPUT ;
    USE SIGNAL ;
    PORT
      LAYER M4 ;
        RECT  0 13.632 0.192 13.656 ;
    END
  END d[69]
  PIN d[6]
    DIRECTION INPUT ;
    USE SIGNAL ;
    PORT
      LAYER M4 ;
        RECT  0 1.536 0.192 1.56 ;
    END
  END d[6]
  PIN d[70]
    DIRECTION INPUT ;
    USE SIGNAL ;
    PORT
      LAYER M4 ;
        RECT  0 13.824 0.192 13.848 ;
    END
  END d[70]
  PIN d[71]
    DIRECTION INPUT ;
    USE SIGNAL ;
    PORT
      LAYER M4 ;
        RECT  0 14.016 0.192 14.04 ;
    END
  END d[71]
  PIN d[72]
    DIRECTION INPUT ;
    USE SIGNAL ;
    PORT
      LAYER M4 ;
        RECT  0 14.208 0.192 14.232 ;
    END
  END d[72]
  PIN d[73]
    DIRECTION INPUT ;
    USE SIGNAL ;
    PORT
      LAYER M4 ;
        RECT  0 14.4 0.192 14.424 ;
    END
  END d[73]
  PIN d[74]
    DIRECTION INPUT ;
    USE SIGNAL ;
    PORT
      LAYER M4 ;
        RECT  0 14.592 0.192 14.616 ;
    END
  END d[74]
  PIN d[75]
    DIRECTION INPUT ;
    USE SIGNAL ;
    PORT
      LAYER M4 ;
        RECT  0 14.784 0.192 14.808 ;
    END
  END d[75]
  PIN d[76]
    DIRECTION INPUT ;
    USE SIGNAL ;
    PORT
      LAYER M4 ;
        RECT  0 14.976 0.192 15 ;
    END
  END d[76]
  PIN d[77]
    DIRECTION INPUT ;
    USE SIGNAL ;
    PORT
      LAYER M4 ;
        RECT  0 15.168 0.192 15.192 ;
    END
  END d[77]
  PIN d[78]
    DIRECTION INPUT ;
    USE SIGNAL ;
    PORT
      LAYER M4 ;
        RECT  0 15.36 0.192 15.384 ;
    END
  END d[78]
  PIN d[79]
    DIRECTION INPUT ;
    USE SIGNAL ;
    PORT
      LAYER M4 ;
        RECT  0 15.552 0.192 15.576 ;
    END
  END d[79]
  PIN d[7]
    DIRECTION INPUT ;
    USE SIGNAL ;
    PORT
      LAYER M4 ;
        RECT  0 1.728 0.192 1.752 ;
    END
  END d[7]
  PIN d[80]
    DIRECTION INPUT ;
    USE SIGNAL ;
    PORT
      LAYER M4 ;
        RECT  0 15.744 0.192 15.768 ;
    END
  END d[80]
  PIN d[81]
    DIRECTION INPUT ;
    USE SIGNAL ;
    PORT
      LAYER M4 ;
        RECT  0 15.936 0.192 15.96 ;
    END
  END d[81]
  PIN d[82]
    DIRECTION INPUT ;
    USE SIGNAL ;
    PORT
      LAYER M4 ;
        RECT  0 16.128 0.192 16.152 ;
    END
  END d[82]
  PIN d[83]
    DIRECTION INPUT ;
    USE SIGNAL ;
    PORT
      LAYER M4 ;
        RECT  0 16.32 0.192 16.344 ;
    END
  END d[83]
  PIN d[84]
    DIRECTION INPUT ;
    USE SIGNAL ;
    PORT
      LAYER M4 ;
        RECT  0 16.512 0.192 16.536 ;
    END
  END d[84]
  PIN d[85]
    DIRECTION INPUT ;
    USE SIGNAL ;
    PORT
      LAYER M4 ;
        RECT  0 16.704 0.192 16.728 ;
    END
  END d[85]
  PIN d[86]
    DIRECTION INPUT ;
    USE SIGNAL ;
    PORT
      LAYER M4 ;
        RECT  0 16.896 0.192 16.92 ;
    END
  END d[86]
  PIN d[87]
    DIRECTION INPUT ;
    USE SIGNAL ;
    PORT
      LAYER M4 ;
        RECT  0 17.088 0.192 17.112 ;
    END
  END d[87]
  PIN d[88]
    DIRECTION INPUT ;
    USE SIGNAL ;
    PORT
      LAYER M4 ;
        RECT  0 17.28 0.192 17.304 ;
    END
  END d[88]
  PIN d[89]
    DIRECTION INPUT ;
    USE SIGNAL ;
    PORT
      LAYER M4 ;
        RECT  0 17.472 0.192 17.496 ;
    END
  END d[89]
  PIN d[8]
    DIRECTION INPUT ;
    USE SIGNAL ;
    PORT
      LAYER M4 ;
        RECT  0 1.92 0.192 1.944 ;
    END
  END d[8]
  PIN d[90]
    DIRECTION INPUT ;
    USE SIGNAL ;
    PORT
      LAYER M4 ;
        RECT  0 17.664 0.192 17.688 ;
    END
  END d[90]
  PIN d[91]
    DIRECTION INPUT ;
    USE SIGNAL ;
    PORT
      LAYER M4 ;
        RECT  0 17.856 0.192 17.88 ;
    END
  END d[91]
  PIN d[92]
    DIRECTION INPUT ;
    USE SIGNAL ;
    PORT
      LAYER M4 ;
        RECT  0 18.048 0.192 18.072 ;
    END
  END d[92]
  PIN d[93]
    DIRECTION INPUT ;
    USE SIGNAL ;
    PORT
      LAYER M4 ;
        RECT  0 18.24 0.192 18.264 ;
    END
  END d[93]
  PIN d[94]
    DIRECTION INPUT ;
    USE SIGNAL ;
    PORT
      LAYER M4 ;
        RECT  0 18.432 0.192 18.456 ;
    END
  END d[94]
  PIN d[95]
    DIRECTION INPUT ;
    USE SIGNAL ;
    PORT
      LAYER M4 ;
        RECT  0 18.624 0.192 18.648 ;
    END
  END d[95]
  PIN d[96]
    DIRECTION INPUT ;
    USE SIGNAL ;
    PORT
      LAYER M4 ;
        RECT  0 18.816 0.192 18.84 ;
    END
  END d[96]
  PIN d[97]
    DIRECTION INPUT ;
    USE SIGNAL ;
    PORT
      LAYER M4 ;
        RECT  0 19.008 0.192 19.032 ;
    END
  END d[97]
  PIN d[98]
    DIRECTION INPUT ;
    USE SIGNAL ;
    PORT
      LAYER M4 ;
        RECT  0 19.2 0.192 19.224 ;
    END
  END d[98]
  PIN d[99]
    DIRECTION INPUT ;
    USE SIGNAL ;
    PORT
      LAYER M4 ;
        RECT  0 19.392 0.192 19.416 ;
    END
  END d[99]
  PIN d[9]
    DIRECTION INPUT ;
    USE SIGNAL ;
    PORT
      LAYER M4 ;
        RECT  0 2.112 0.192 2.136 ;
    END
  END d[9]
  PIN q[0]
    DIRECTION OUTPUT ;
    USE SIGNAL ;
    PORT
      LAYER M4 ;
        RECT  11.688 0.384 11.88 0.408 ;
    END
  END q[0]
  PIN q[100]
    DIRECTION OUTPUT ;
    USE SIGNAL ;
    PORT
      LAYER M4 ;
        RECT  11.688 19.584 11.88 19.608 ;
    END
  END q[100]
  PIN q[101]
    DIRECTION OUTPUT ;
    USE SIGNAL ;
    PORT
      LAYER M4 ;
        RECT  11.688 19.776 11.88 19.8 ;
    END
  END q[101]
  PIN q[102]
    DIRECTION OUTPUT ;
    USE SIGNAL ;
    PORT
      LAYER M4 ;
        RECT  11.688 19.968 11.88 19.992 ;
    END
  END q[102]
  PIN q[103]
    DIRECTION OUTPUT ;
    USE SIGNAL ;
    PORT
      LAYER M4 ;
        RECT  11.688 20.16 11.88 20.184 ;
    END
  END q[103]
  PIN q[104]
    DIRECTION OUTPUT ;
    USE SIGNAL ;
    PORT
      LAYER M4 ;
        RECT  11.688 20.352 11.88 20.376 ;
    END
  END q[104]
  PIN q[105]
    DIRECTION OUTPUT ;
    USE SIGNAL ;
    PORT
      LAYER M4 ;
        RECT  11.688 20.544 11.88 20.568 ;
    END
  END q[105]
  PIN q[106]
    DIRECTION OUTPUT ;
    USE SIGNAL ;
    PORT
      LAYER M4 ;
        RECT  11.688 20.736 11.88 20.76 ;
    END
  END q[106]
  PIN q[107]
    DIRECTION OUTPUT ;
    USE SIGNAL ;
    PORT
      LAYER M4 ;
        RECT  11.688 20.928 11.88 20.952 ;
    END
  END q[107]
  PIN q[108]
    DIRECTION OUTPUT ;
    USE SIGNAL ;
    PORT
      LAYER M4 ;
        RECT  11.688 21.12 11.88 21.144 ;
    END
  END q[108]
  PIN q[109]
    DIRECTION OUTPUT ;
    USE SIGNAL ;
    PORT
      LAYER M4 ;
        RECT  11.688 21.312 11.88 21.336 ;
    END
  END q[109]
  PIN q[10]
    DIRECTION OUTPUT ;
    USE SIGNAL ;
    PORT
      LAYER M4 ;
        RECT  11.688 2.304 11.88 2.328 ;
    END
  END q[10]
  PIN q[110]
    DIRECTION OUTPUT ;
    USE SIGNAL ;
    PORT
      LAYER M4 ;
        RECT  11.688 21.504 11.88 21.528 ;
    END
  END q[110]
  PIN q[111]
    DIRECTION OUTPUT ;
    USE SIGNAL ;
    PORT
      LAYER M4 ;
        RECT  11.688 21.696 11.88 21.72 ;
    END
  END q[111]
  PIN q[112]
    DIRECTION OUTPUT ;
    USE SIGNAL ;
    PORT
      LAYER M4 ;
        RECT  11.688 21.888 11.88 21.912 ;
    END
  END q[112]
  PIN q[113]
    DIRECTION OUTPUT ;
    USE SIGNAL ;
    PORT
      LAYER M4 ;
        RECT  11.688 22.08 11.88 22.104 ;
    END
  END q[113]
  PIN q[114]
    DIRECTION OUTPUT ;
    USE SIGNAL ;
    PORT
      LAYER M4 ;
        RECT  11.688 22.272 11.88 22.296 ;
    END
  END q[114]
  PIN q[115]
    DIRECTION OUTPUT ;
    USE SIGNAL ;
    PORT
      LAYER M4 ;
        RECT  11.688 22.464 11.88 22.488 ;
    END
  END q[115]
  PIN q[116]
    DIRECTION OUTPUT ;
    USE SIGNAL ;
    PORT
      LAYER M4 ;
        RECT  11.688 22.656 11.88 22.68 ;
    END
  END q[116]
  PIN q[117]
    DIRECTION OUTPUT ;
    USE SIGNAL ;
    PORT
      LAYER M4 ;
        RECT  11.688 22.848 11.88 22.872 ;
    END
  END q[117]
  PIN q[118]
    DIRECTION OUTPUT ;
    USE SIGNAL ;
    PORT
      LAYER M4 ;
        RECT  11.688 23.04 11.88 23.064 ;
    END
  END q[118]
  PIN q[119]
    DIRECTION OUTPUT ;
    USE SIGNAL ;
    PORT
      LAYER M4 ;
        RECT  11.688 23.232 11.88 23.256 ;
    END
  END q[119]
  PIN q[11]
    DIRECTION OUTPUT ;
    USE SIGNAL ;
    PORT
      LAYER M4 ;
        RECT  11.688 2.496 11.88 2.52 ;
    END
  END q[11]
  PIN q[120]
    DIRECTION OUTPUT ;
    USE SIGNAL ;
    PORT
      LAYER M4 ;
        RECT  11.688 23.424 11.88 23.448 ;
    END
  END q[120]
  PIN q[121]
    DIRECTION OUTPUT ;
    USE SIGNAL ;
    PORT
      LAYER M4 ;
        RECT  11.688 23.616 11.88 23.64 ;
    END
  END q[121]
  PIN q[122]
    DIRECTION OUTPUT ;
    USE SIGNAL ;
    PORT
      LAYER M4 ;
        RECT  11.688 23.808 11.88 23.832 ;
    END
  END q[122]
  PIN q[123]
    DIRECTION OUTPUT ;
    USE SIGNAL ;
    PORT
      LAYER M4 ;
        RECT  11.688 24 11.88 24.024 ;
    END
  END q[123]
  PIN q[124]
    DIRECTION OUTPUT ;
    USE SIGNAL ;
    PORT
      LAYER M4 ;
        RECT  11.688 24.192 11.88 24.216 ;
    END
  END q[124]
  PIN q[125]
    DIRECTION OUTPUT ;
    USE SIGNAL ;
    PORT
      LAYER M4 ;
        RECT  11.688 24.384 11.88 24.408 ;
    END
  END q[125]
  PIN q[126]
    DIRECTION OUTPUT ;
    USE SIGNAL ;
    PORT
      LAYER M4 ;
        RECT  11.688 24.576 11.88 24.6 ;
    END
  END q[126]
  PIN q[127]
    DIRECTION OUTPUT ;
    USE SIGNAL ;
    PORT
      LAYER M4 ;
        RECT  11.688 24.768 11.88 24.792 ;
    END
  END q[127]
  PIN q[128]
    DIRECTION OUTPUT ;
    USE SIGNAL ;
    PORT
      LAYER M4 ;
        RECT  11.688 24.96 11.88 24.984 ;
    END
  END q[128]
  PIN q[129]
    DIRECTION OUTPUT ;
    USE SIGNAL ;
    PORT
      LAYER M4 ;
        RECT  11.688 25.152 11.88 25.176 ;
    END
  END q[129]
  PIN q[12]
    DIRECTION OUTPUT ;
    USE SIGNAL ;
    PORT
      LAYER M4 ;
        RECT  11.688 2.688 11.88 2.712 ;
    END
  END q[12]
  PIN q[130]
    DIRECTION OUTPUT ;
    USE SIGNAL ;
    PORT
      LAYER M4 ;
        RECT  11.688 25.344 11.88 25.368 ;
    END
  END q[130]
  PIN q[131]
    DIRECTION OUTPUT ;
    USE SIGNAL ;
    PORT
      LAYER M4 ;
        RECT  11.688 25.536 11.88 25.56 ;
    END
  END q[131]
  PIN q[132]
    DIRECTION OUTPUT ;
    USE SIGNAL ;
    PORT
      LAYER M4 ;
        RECT  11.688 25.728 11.88 25.752 ;
    END
  END q[132]
  PIN q[133]
    DIRECTION OUTPUT ;
    USE SIGNAL ;
    PORT
      LAYER M4 ;
        RECT  11.688 25.92 11.88 25.944 ;
    END
  END q[133]
  PIN q[134]
    DIRECTION OUTPUT ;
    USE SIGNAL ;
    PORT
      LAYER M4 ;
        RECT  11.688 26.112 11.88 26.136 ;
    END
  END q[134]
  PIN q[135]
    DIRECTION OUTPUT ;
    USE SIGNAL ;
    PORT
      LAYER M4 ;
        RECT  11.688 26.304 11.88 26.328 ;
    END
  END q[135]
  PIN q[136]
    DIRECTION OUTPUT ;
    USE SIGNAL ;
    PORT
      LAYER M4 ;
        RECT  11.688 26.496 11.88 26.52 ;
    END
  END q[136]
  PIN q[137]
    DIRECTION OUTPUT ;
    USE SIGNAL ;
    PORT
      LAYER M4 ;
        RECT  11.688 26.688 11.88 26.712 ;
    END
  END q[137]
  PIN q[138]
    DIRECTION OUTPUT ;
    USE SIGNAL ;
    PORT
      LAYER M4 ;
        RECT  11.688 26.88 11.88 26.904 ;
    END
  END q[138]
  PIN q[139]
    DIRECTION OUTPUT ;
    USE SIGNAL ;
    PORT
      LAYER M4 ;
        RECT  11.688 27.072 11.88 27.096 ;
    END
  END q[139]
  PIN q[13]
    DIRECTION OUTPUT ;
    USE SIGNAL ;
    PORT
      LAYER M4 ;
        RECT  11.688 2.88 11.88 2.904 ;
    END
  END q[13]
  PIN q[140]
    DIRECTION OUTPUT ;
    USE SIGNAL ;
    PORT
      LAYER M4 ;
        RECT  11.688 27.264 11.88 27.288 ;
    END
  END q[140]
  PIN q[141]
    DIRECTION OUTPUT ;
    USE SIGNAL ;
    PORT
      LAYER M4 ;
        RECT  11.688 27.456 11.88 27.48 ;
    END
  END q[141]
  PIN q[142]
    DIRECTION OUTPUT ;
    USE SIGNAL ;
    PORT
      LAYER M4 ;
        RECT  11.688 27.648 11.88 27.672 ;
    END
  END q[142]
  PIN q[143]
    DIRECTION OUTPUT ;
    USE SIGNAL ;
    PORT
      LAYER M4 ;
        RECT  11.688 27.84 11.88 27.864 ;
    END
  END q[143]
  PIN q[144]
    DIRECTION OUTPUT ;
    USE SIGNAL ;
    PORT
      LAYER M4 ;
        RECT  11.688 28.032 11.88 28.056 ;
    END
  END q[144]
  PIN q[145]
    DIRECTION OUTPUT ;
    USE SIGNAL ;
    PORT
      LAYER M4 ;
        RECT  11.688 28.224 11.88 28.248 ;
    END
  END q[145]
  PIN q[146]
    DIRECTION OUTPUT ;
    USE SIGNAL ;
    PORT
      LAYER M4 ;
        RECT  11.688 28.416 11.88 28.44 ;
    END
  END q[146]
  PIN q[147]
    DIRECTION OUTPUT ;
    USE SIGNAL ;
    PORT
      LAYER M4 ;
        RECT  11.688 28.608 11.88 28.632 ;
    END
  END q[147]
  PIN q[148]
    DIRECTION OUTPUT ;
    USE SIGNAL ;
    PORT
      LAYER M4 ;
        RECT  11.688 28.8 11.88 28.824 ;
    END
  END q[148]
  PIN q[149]
    DIRECTION OUTPUT ;
    USE SIGNAL ;
    PORT
      LAYER M4 ;
        RECT  11.688 28.992 11.88 29.016 ;
    END
  END q[149]
  PIN q[14]
    DIRECTION OUTPUT ;
    USE SIGNAL ;
    PORT
      LAYER M4 ;
        RECT  11.688 3.072 11.88 3.096 ;
    END
  END q[14]
  PIN q[150]
    DIRECTION OUTPUT ;
    USE SIGNAL ;
    PORT
      LAYER M4 ;
        RECT  11.688 29.184 11.88 29.208 ;
    END
  END q[150]
  PIN q[151]
    DIRECTION OUTPUT ;
    USE SIGNAL ;
    PORT
      LAYER M4 ;
        RECT  11.688 29.376 11.88 29.4 ;
    END
  END q[151]
  PIN q[152]
    DIRECTION OUTPUT ;
    USE SIGNAL ;
    PORT
      LAYER M4 ;
        RECT  11.688 29.568 11.88 29.592 ;
    END
  END q[152]
  PIN q[153]
    DIRECTION OUTPUT ;
    USE SIGNAL ;
    PORT
      LAYER M4 ;
        RECT  11.688 29.76 11.88 29.784 ;
    END
  END q[153]
  PIN q[154]
    DIRECTION OUTPUT ;
    USE SIGNAL ;
    PORT
      LAYER M4 ;
        RECT  11.688 29.952 11.88 29.976 ;
    END
  END q[154]
  PIN q[155]
    DIRECTION OUTPUT ;
    USE SIGNAL ;
    PORT
      LAYER M4 ;
        RECT  11.688 30.144 11.88 30.168 ;
    END
  END q[155]
  PIN q[156]
    DIRECTION OUTPUT ;
    USE SIGNAL ;
    PORT
      LAYER M4 ;
        RECT  11.688 30.336 11.88 30.36 ;
    END
  END q[156]
  PIN q[157]
    DIRECTION OUTPUT ;
    USE SIGNAL ;
    PORT
      LAYER M4 ;
        RECT  11.688 30.528 11.88 30.552 ;
    END
  END q[157]
  PIN q[158]
    DIRECTION OUTPUT ;
    USE SIGNAL ;
    PORT
      LAYER M4 ;
        RECT  11.688 30.72 11.88 30.744 ;
    END
  END q[158]
  PIN q[159]
    DIRECTION OUTPUT ;
    USE SIGNAL ;
    PORT
      LAYER M4 ;
        RECT  11.688 30.912 11.88 30.936 ;
    END
  END q[159]
  PIN q[15]
    DIRECTION OUTPUT ;
    USE SIGNAL ;
    PORT
      LAYER M4 ;
        RECT  11.688 3.264 11.88 3.288 ;
    END
  END q[15]
  PIN q[160]
    DIRECTION OUTPUT ;
    USE SIGNAL ;
    PORT
      LAYER M4 ;
        RECT  11.688 31.104 11.88 31.128 ;
    END
  END q[160]
  PIN q[161]
    DIRECTION OUTPUT ;
    USE SIGNAL ;
    PORT
      LAYER M4 ;
        RECT  11.688 31.296 11.88 31.32 ;
    END
  END q[161]
  PIN q[162]
    DIRECTION OUTPUT ;
    USE SIGNAL ;
    PORT
      LAYER M4 ;
        RECT  11.688 31.488 11.88 31.512 ;
    END
  END q[162]
  PIN q[163]
    DIRECTION OUTPUT ;
    USE SIGNAL ;
    PORT
      LAYER M4 ;
        RECT  11.688 31.68 11.88 31.704 ;
    END
  END q[163]
  PIN q[164]
    DIRECTION OUTPUT ;
    USE SIGNAL ;
    PORT
      LAYER M4 ;
        RECT  11.688 31.872 11.88 31.896 ;
    END
  END q[164]
  PIN q[165]
    DIRECTION OUTPUT ;
    USE SIGNAL ;
    PORT
      LAYER M4 ;
        RECT  11.688 32.064 11.88 32.088 ;
    END
  END q[165]
  PIN q[166]
    DIRECTION OUTPUT ;
    USE SIGNAL ;
    PORT
      LAYER M4 ;
        RECT  11.688 32.256 11.88 32.28 ;
    END
  END q[166]
  PIN q[167]
    DIRECTION OUTPUT ;
    USE SIGNAL ;
    PORT
      LAYER M4 ;
        RECT  11.688 32.448 11.88 32.472 ;
    END
  END q[167]
  PIN q[168]
    DIRECTION OUTPUT ;
    USE SIGNAL ;
    PORT
      LAYER M4 ;
        RECT  11.688 32.64 11.88 32.664 ;
    END
  END q[168]
  PIN q[169]
    DIRECTION OUTPUT ;
    USE SIGNAL ;
    PORT
      LAYER M4 ;
        RECT  11.688 32.832 11.88 32.856 ;
    END
  END q[169]
  PIN q[16]
    DIRECTION OUTPUT ;
    USE SIGNAL ;
    PORT
      LAYER M4 ;
        RECT  11.688 3.456 11.88 3.48 ;
    END
  END q[16]
  PIN q[170]
    DIRECTION OUTPUT ;
    USE SIGNAL ;
    PORT
      LAYER M4 ;
        RECT  11.688 33.024 11.88 33.048 ;
    END
  END q[170]
  PIN q[171]
    DIRECTION OUTPUT ;
    USE SIGNAL ;
    PORT
      LAYER M4 ;
        RECT  11.688 33.216 11.88 33.24 ;
    END
  END q[171]
  PIN q[172]
    DIRECTION OUTPUT ;
    USE SIGNAL ;
    PORT
      LAYER M4 ;
        RECT  11.688 33.408 11.88 33.432 ;
    END
  END q[172]
  PIN q[173]
    DIRECTION OUTPUT ;
    USE SIGNAL ;
    PORT
      LAYER M4 ;
        RECT  11.688 33.6 11.88 33.624 ;
    END
  END q[173]
  PIN q[174]
    DIRECTION OUTPUT ;
    USE SIGNAL ;
    PORT
      LAYER M4 ;
        RECT  11.688 33.792 11.88 33.816 ;
    END
  END q[174]
  PIN q[175]
    DIRECTION OUTPUT ;
    USE SIGNAL ;
    PORT
      LAYER M4 ;
        RECT  11.688 33.984 11.88 34.008 ;
    END
  END q[175]
  PIN q[176]
    DIRECTION OUTPUT ;
    USE SIGNAL ;
    PORT
      LAYER M4 ;
        RECT  11.688 34.176 11.88 34.2 ;
    END
  END q[176]
  PIN q[177]
    DIRECTION OUTPUT ;
    USE SIGNAL ;
    PORT
      LAYER M4 ;
        RECT  11.688 34.368 11.88 34.392 ;
    END
  END q[177]
  PIN q[178]
    DIRECTION OUTPUT ;
    USE SIGNAL ;
    PORT
      LAYER M4 ;
        RECT  11.688 34.56 11.88 34.584 ;
    END
  END q[178]
  PIN q[179]
    DIRECTION OUTPUT ;
    USE SIGNAL ;
    PORT
      LAYER M4 ;
        RECT  11.688 34.752 11.88 34.776 ;
    END
  END q[179]
  PIN q[17]
    DIRECTION OUTPUT ;
    USE SIGNAL ;
    PORT
      LAYER M4 ;
        RECT  11.688 3.648 11.88 3.672 ;
    END
  END q[17]
  PIN q[180]
    DIRECTION OUTPUT ;
    USE SIGNAL ;
    PORT
      LAYER M4 ;
        RECT  11.688 34.944 11.88 34.968 ;
    END
  END q[180]
  PIN q[181]
    DIRECTION OUTPUT ;
    USE SIGNAL ;
    PORT
      LAYER M4 ;
        RECT  11.688 35.136 11.88 35.16 ;
    END
  END q[181]
  PIN q[182]
    DIRECTION OUTPUT ;
    USE SIGNAL ;
    PORT
      LAYER M4 ;
        RECT  11.688 35.328 11.88 35.352 ;
    END
  END q[182]
  PIN q[183]
    DIRECTION OUTPUT ;
    USE SIGNAL ;
    PORT
      LAYER M4 ;
        RECT  11.688 35.52 11.88 35.544 ;
    END
  END q[183]
  PIN q[184]
    DIRECTION OUTPUT ;
    USE SIGNAL ;
    PORT
      LAYER M4 ;
        RECT  11.688 35.712 11.88 35.736 ;
    END
  END q[184]
  PIN q[185]
    DIRECTION OUTPUT ;
    USE SIGNAL ;
    PORT
      LAYER M4 ;
        RECT  11.688 35.904 11.88 35.928 ;
    END
  END q[185]
  PIN q[186]
    DIRECTION OUTPUT ;
    USE SIGNAL ;
    PORT
      LAYER M4 ;
        RECT  11.688 36.096 11.88 36.12 ;
    END
  END q[186]
  PIN q[187]
    DIRECTION OUTPUT ;
    USE SIGNAL ;
    PORT
      LAYER M4 ;
        RECT  11.688 36.288 11.88 36.312 ;
    END
  END q[187]
  PIN q[188]
    DIRECTION OUTPUT ;
    USE SIGNAL ;
    PORT
      LAYER M4 ;
        RECT  11.688 36.48 11.88 36.504 ;
    END
  END q[188]
  PIN q[189]
    DIRECTION OUTPUT ;
    USE SIGNAL ;
    PORT
      LAYER M4 ;
        RECT  11.688 36.672 11.88 36.696 ;
    END
  END q[189]
  PIN q[18]
    DIRECTION OUTPUT ;
    USE SIGNAL ;
    PORT
      LAYER M4 ;
        RECT  11.688 3.84 11.88 3.864 ;
    END
  END q[18]
  PIN q[190]
    DIRECTION OUTPUT ;
    USE SIGNAL ;
    PORT
      LAYER M4 ;
        RECT  11.688 36.864 11.88 36.888 ;
    END
  END q[190]
  PIN q[191]
    DIRECTION OUTPUT ;
    USE SIGNAL ;
    PORT
      LAYER M4 ;
        RECT  11.688 37.056 11.88 37.08 ;
    END
  END q[191]
  PIN q[192]
    DIRECTION OUTPUT ;
    USE SIGNAL ;
    PORT
      LAYER M4 ;
        RECT  11.688 37.248 11.88 37.272 ;
    END
  END q[192]
  PIN q[193]
    DIRECTION OUTPUT ;
    USE SIGNAL ;
    PORT
      LAYER M4 ;
        RECT  11.688 37.44 11.88 37.464 ;
    END
  END q[193]
  PIN q[194]
    DIRECTION OUTPUT ;
    USE SIGNAL ;
    PORT
      LAYER M4 ;
        RECT  11.688 37.632 11.88 37.656 ;
    END
  END q[194]
  PIN q[195]
    DIRECTION OUTPUT ;
    USE SIGNAL ;
    PORT
      LAYER M4 ;
        RECT  11.688 37.824 11.88 37.848 ;
    END
  END q[195]
  PIN q[196]
    DIRECTION OUTPUT ;
    USE SIGNAL ;
    PORT
      LAYER M4 ;
        RECT  11.688 38.016 11.88 38.04 ;
    END
  END q[196]
  PIN q[197]
    DIRECTION OUTPUT ;
    USE SIGNAL ;
    PORT
      LAYER M4 ;
        RECT  11.688 38.208 11.88 38.232 ;
    END
  END q[197]
  PIN q[198]
    DIRECTION OUTPUT ;
    USE SIGNAL ;
    PORT
      LAYER M4 ;
        RECT  11.688 38.4 11.88 38.424 ;
    END
  END q[198]
  PIN q[199]
    DIRECTION OUTPUT ;
    USE SIGNAL ;
    PORT
      LAYER M4 ;
        RECT  11.688 38.592 11.88 38.616 ;
    END
  END q[199]
  PIN q[19]
    DIRECTION OUTPUT ;
    USE SIGNAL ;
    PORT
      LAYER M4 ;
        RECT  11.688 4.032 11.88 4.056 ;
    END
  END q[19]
  PIN q[1]
    DIRECTION OUTPUT ;
    USE SIGNAL ;
    PORT
      LAYER M4 ;
        RECT  11.688 0.576 11.88 0.6 ;
    END
  END q[1]
  PIN q[200]
    DIRECTION OUTPUT ;
    USE SIGNAL ;
    PORT
      LAYER M4 ;
        RECT  11.688 38.784 11.88 38.808 ;
    END
  END q[200]
  PIN q[201]
    DIRECTION OUTPUT ;
    USE SIGNAL ;
    PORT
      LAYER M4 ;
        RECT  11.688 38.976 11.88 39 ;
    END
  END q[201]
  PIN q[202]
    DIRECTION OUTPUT ;
    USE SIGNAL ;
    PORT
      LAYER M4 ;
        RECT  11.688 39.168 11.88 39.192 ;
    END
  END q[202]
  PIN q[203]
    DIRECTION OUTPUT ;
    USE SIGNAL ;
    PORT
      LAYER M4 ;
        RECT  11.688 39.36 11.88 39.384 ;
    END
  END q[203]
  PIN q[204]
    DIRECTION OUTPUT ;
    USE SIGNAL ;
    PORT
      LAYER M4 ;
        RECT  11.688 39.552 11.88 39.576 ;
    END
  END q[204]
  PIN q[205]
    DIRECTION OUTPUT ;
    USE SIGNAL ;
    PORT
      LAYER M4 ;
        RECT  11.688 39.744 11.88 39.768 ;
    END
  END q[205]
  PIN q[206]
    DIRECTION OUTPUT ;
    USE SIGNAL ;
    PORT
      LAYER M4 ;
        RECT  11.688 39.936 11.88 39.96 ;
    END
  END q[206]
  PIN q[207]
    DIRECTION OUTPUT ;
    USE SIGNAL ;
    PORT
      LAYER M4 ;
        RECT  11.688 40.128 11.88 40.152 ;
    END
  END q[207]
  PIN q[208]
    DIRECTION OUTPUT ;
    USE SIGNAL ;
    PORT
      LAYER M4 ;
        RECT  11.688 40.32 11.88 40.344 ;
    END
  END q[208]
  PIN q[209]
    DIRECTION OUTPUT ;
    USE SIGNAL ;
    PORT
      LAYER M4 ;
        RECT  11.688 40.512 11.88 40.536 ;
    END
  END q[209]
  PIN q[20]
    DIRECTION OUTPUT ;
    USE SIGNAL ;
    PORT
      LAYER M4 ;
        RECT  11.688 4.224 11.88 4.248 ;
    END
  END q[20]
  PIN q[210]
    DIRECTION OUTPUT ;
    USE SIGNAL ;
    PORT
      LAYER M4 ;
        RECT  11.688 40.704 11.88 40.728 ;
    END
  END q[210]
  PIN q[211]
    DIRECTION OUTPUT ;
    USE SIGNAL ;
    PORT
      LAYER M4 ;
        RECT  11.688 40.896 11.88 40.92 ;
    END
  END q[211]
  PIN q[212]
    DIRECTION OUTPUT ;
    USE SIGNAL ;
    PORT
      LAYER M4 ;
        RECT  11.688 41.088 11.88 41.112 ;
    END
  END q[212]
  PIN q[213]
    DIRECTION OUTPUT ;
    USE SIGNAL ;
    PORT
      LAYER M4 ;
        RECT  11.688 41.28 11.88 41.304 ;
    END
  END q[213]
  PIN q[214]
    DIRECTION OUTPUT ;
    USE SIGNAL ;
    PORT
      LAYER M4 ;
        RECT  11.688 41.472 11.88 41.496 ;
    END
  END q[214]
  PIN q[215]
    DIRECTION OUTPUT ;
    USE SIGNAL ;
    PORT
      LAYER M4 ;
        RECT  11.688 41.664 11.88 41.688 ;
    END
  END q[215]
  PIN q[216]
    DIRECTION OUTPUT ;
    USE SIGNAL ;
    PORT
      LAYER M4 ;
        RECT  11.688 41.856 11.88 41.88 ;
    END
  END q[216]
  PIN q[217]
    DIRECTION OUTPUT ;
    USE SIGNAL ;
    PORT
      LAYER M4 ;
        RECT  11.688 42.048 11.88 42.072 ;
    END
  END q[217]
  PIN q[218]
    DIRECTION OUTPUT ;
    USE SIGNAL ;
    PORT
      LAYER M4 ;
        RECT  11.688 42.24 11.88 42.264 ;
    END
  END q[218]
  PIN q[219]
    DIRECTION OUTPUT ;
    USE SIGNAL ;
    PORT
      LAYER M4 ;
        RECT  11.688 42.432 11.88 42.456 ;
    END
  END q[219]
  PIN q[21]
    DIRECTION OUTPUT ;
    USE SIGNAL ;
    PORT
      LAYER M4 ;
        RECT  11.688 4.416 11.88 4.44 ;
    END
  END q[21]
  PIN q[220]
    DIRECTION OUTPUT ;
    USE SIGNAL ;
    PORT
      LAYER M4 ;
        RECT  11.688 42.624 11.88 42.648 ;
    END
  END q[220]
  PIN q[221]
    DIRECTION OUTPUT ;
    USE SIGNAL ;
    PORT
      LAYER M4 ;
        RECT  11.688 42.816 11.88 42.84 ;
    END
  END q[221]
  PIN q[222]
    DIRECTION OUTPUT ;
    USE SIGNAL ;
    PORT
      LAYER M4 ;
        RECT  11.688 43.008 11.88 43.032 ;
    END
  END q[222]
  PIN q[223]
    DIRECTION OUTPUT ;
    USE SIGNAL ;
    PORT
      LAYER M4 ;
        RECT  11.688 43.2 11.88 43.224 ;
    END
  END q[223]
  PIN q[224]
    DIRECTION OUTPUT ;
    USE SIGNAL ;
    PORT
      LAYER M4 ;
        RECT  11.688 43.392 11.88 43.416 ;
    END
  END q[224]
  PIN q[225]
    DIRECTION OUTPUT ;
    USE SIGNAL ;
    PORT
      LAYER M4 ;
        RECT  11.688 43.584 11.88 43.608 ;
    END
  END q[225]
  PIN q[226]
    DIRECTION OUTPUT ;
    USE SIGNAL ;
    PORT
      LAYER M4 ;
        RECT  11.688 43.776 11.88 43.8 ;
    END
  END q[226]
  PIN q[227]
    DIRECTION OUTPUT ;
    USE SIGNAL ;
    PORT
      LAYER M4 ;
        RECT  11.688 43.968 11.88 43.992 ;
    END
  END q[227]
  PIN q[228]
    DIRECTION OUTPUT ;
    USE SIGNAL ;
    PORT
      LAYER M4 ;
        RECT  11.688 44.16 11.88 44.184 ;
    END
  END q[228]
  PIN q[229]
    DIRECTION OUTPUT ;
    USE SIGNAL ;
    PORT
      LAYER M4 ;
        RECT  11.688 44.352 11.88 44.376 ;
    END
  END q[229]
  PIN q[22]
    DIRECTION OUTPUT ;
    USE SIGNAL ;
    PORT
      LAYER M4 ;
        RECT  11.688 4.608 11.88 4.632 ;
    END
  END q[22]
  PIN q[230]
    DIRECTION OUTPUT ;
    USE SIGNAL ;
    PORT
      LAYER M4 ;
        RECT  11.688 44.544 11.88 44.568 ;
    END
  END q[230]
  PIN q[231]
    DIRECTION OUTPUT ;
    USE SIGNAL ;
    PORT
      LAYER M4 ;
        RECT  11.688 44.736 11.88 44.76 ;
    END
  END q[231]
  PIN q[232]
    DIRECTION OUTPUT ;
    USE SIGNAL ;
    PORT
      LAYER M4 ;
        RECT  11.688 44.928 11.88 44.952 ;
    END
  END q[232]
  PIN q[233]
    DIRECTION OUTPUT ;
    USE SIGNAL ;
    PORT
      LAYER M4 ;
        RECT  11.688 45.12 11.88 45.144 ;
    END
  END q[233]
  PIN q[234]
    DIRECTION OUTPUT ;
    USE SIGNAL ;
    PORT
      LAYER M4 ;
        RECT  11.688 45.312 11.88 45.336 ;
    END
  END q[234]
  PIN q[235]
    DIRECTION OUTPUT ;
    USE SIGNAL ;
    PORT
      LAYER M4 ;
        RECT  11.688 45.504 11.88 45.528 ;
    END
  END q[235]
  PIN q[236]
    DIRECTION OUTPUT ;
    USE SIGNAL ;
    PORT
      LAYER M4 ;
        RECT  11.688 45.696 11.88 45.72 ;
    END
  END q[236]
  PIN q[237]
    DIRECTION OUTPUT ;
    USE SIGNAL ;
    PORT
      LAYER M4 ;
        RECT  11.688 45.888 11.88 45.912 ;
    END
  END q[237]
  PIN q[238]
    DIRECTION OUTPUT ;
    USE SIGNAL ;
    PORT
      LAYER M4 ;
        RECT  11.688 46.08 11.88 46.104 ;
    END
  END q[238]
  PIN q[239]
    DIRECTION OUTPUT ;
    USE SIGNAL ;
    PORT
      LAYER M4 ;
        RECT  11.688 46.272 11.88 46.296 ;
    END
  END q[239]
  PIN q[23]
    DIRECTION OUTPUT ;
    USE SIGNAL ;
    PORT
      LAYER M4 ;
        RECT  11.688 4.8 11.88 4.824 ;
    END
  END q[23]
  PIN q[240]
    DIRECTION OUTPUT ;
    USE SIGNAL ;
    PORT
      LAYER M4 ;
        RECT  11.688 46.464 11.88 46.488 ;
    END
  END q[240]
  PIN q[241]
    DIRECTION OUTPUT ;
    USE SIGNAL ;
    PORT
      LAYER M4 ;
        RECT  11.688 46.656 11.88 46.68 ;
    END
  END q[241]
  PIN q[242]
    DIRECTION OUTPUT ;
    USE SIGNAL ;
    PORT
      LAYER M4 ;
        RECT  11.688 46.848 11.88 46.872 ;
    END
  END q[242]
  PIN q[243]
    DIRECTION OUTPUT ;
    USE SIGNAL ;
    PORT
      LAYER M4 ;
        RECT  11.688 47.04 11.88 47.064 ;
    END
  END q[243]
  PIN q[244]
    DIRECTION OUTPUT ;
    USE SIGNAL ;
    PORT
      LAYER M4 ;
        RECT  11.688 47.232 11.88 47.256 ;
    END
  END q[244]
  PIN q[245]
    DIRECTION OUTPUT ;
    USE SIGNAL ;
    PORT
      LAYER M4 ;
        RECT  11.688 47.424 11.88 47.448 ;
    END
  END q[245]
  PIN q[246]
    DIRECTION OUTPUT ;
    USE SIGNAL ;
    PORT
      LAYER M4 ;
        RECT  11.688 47.616 11.88 47.64 ;
    END
  END q[246]
  PIN q[247]
    DIRECTION OUTPUT ;
    USE SIGNAL ;
    PORT
      LAYER M4 ;
        RECT  11.688 47.808 11.88 47.832 ;
    END
  END q[247]
  PIN q[248]
    DIRECTION OUTPUT ;
    USE SIGNAL ;
    PORT
      LAYER M4 ;
        RECT  11.688 48 11.88 48.024 ;
    END
  END q[248]
  PIN q[249]
    DIRECTION OUTPUT ;
    USE SIGNAL ;
    PORT
      LAYER M4 ;
        RECT  11.688 48.192 11.88 48.216 ;
    END
  END q[249]
  PIN q[24]
    DIRECTION OUTPUT ;
    USE SIGNAL ;
    PORT
      LAYER M4 ;
        RECT  11.688 4.992 11.88 5.016 ;
    END
  END q[24]
  PIN q[250]
    DIRECTION OUTPUT ;
    USE SIGNAL ;
    PORT
      LAYER M4 ;
        RECT  11.688 48.384 11.88 48.408 ;
    END
  END q[250]
  PIN q[251]
    DIRECTION OUTPUT ;
    USE SIGNAL ;
    PORT
      LAYER M4 ;
        RECT  11.688 48.576 11.88 48.6 ;
    END
  END q[251]
  PIN q[252]
    DIRECTION OUTPUT ;
    USE SIGNAL ;
    PORT
      LAYER M4 ;
        RECT  11.688 48.768 11.88 48.792 ;
    END
  END q[252]
  PIN q[253]
    DIRECTION OUTPUT ;
    USE SIGNAL ;
    PORT
      LAYER M4 ;
        RECT  11.688 48.96 11.88 48.984 ;
    END
  END q[253]
  PIN q[254]
    DIRECTION OUTPUT ;
    USE SIGNAL ;
    PORT
      LAYER M4 ;
        RECT  11.688 49.152 11.88 49.176 ;
    END
  END q[254]
  PIN q[255]
    DIRECTION OUTPUT ;
    USE SIGNAL ;
    PORT
      LAYER M4 ;
        RECT  11.688 49.344 11.88 49.368 ;
    END
  END q[255]
  PIN q[256]
    DIRECTION OUTPUT ;
    USE SIGNAL ;
    PORT
      LAYER M4 ;
        RECT  11.688 49.536 11.88 49.56 ;
    END
  END q[256]
  PIN q[257]
    DIRECTION OUTPUT ;
    USE SIGNAL ;
    PORT
      LAYER M4 ;
        RECT  11.688 49.728 11.88 49.752 ;
    END
  END q[257]
  PIN q[258]
    DIRECTION OUTPUT ;
    USE SIGNAL ;
    PORT
      LAYER M4 ;
        RECT  11.688 49.92 11.88 49.944 ;
    END
  END q[258]
  PIN q[259]
    DIRECTION OUTPUT ;
    USE SIGNAL ;
    PORT
      LAYER M4 ;
        RECT  11.688 50.112 11.88 50.136 ;
    END
  END q[259]
  PIN q[25]
    DIRECTION OUTPUT ;
    USE SIGNAL ;
    PORT
      LAYER M4 ;
        RECT  11.688 5.184 11.88 5.208 ;
    END
  END q[25]
  PIN q[260]
    DIRECTION OUTPUT ;
    USE SIGNAL ;
    PORT
      LAYER M4 ;
        RECT  11.688 50.304 11.88 50.328 ;
    END
  END q[260]
  PIN q[261]
    DIRECTION OUTPUT ;
    USE SIGNAL ;
    PORT
      LAYER M4 ;
        RECT  11.688 50.496 11.88 50.52 ;
    END
  END q[261]
  PIN q[262]
    DIRECTION OUTPUT ;
    USE SIGNAL ;
    PORT
      LAYER M4 ;
        RECT  11.688 50.688 11.88 50.712 ;
    END
  END q[262]
  PIN q[263]
    DIRECTION OUTPUT ;
    USE SIGNAL ;
    PORT
      LAYER M4 ;
        RECT  11.688 50.88 11.88 50.904 ;
    END
  END q[263]
  PIN q[264]
    DIRECTION OUTPUT ;
    USE SIGNAL ;
    PORT
      LAYER M4 ;
        RECT  11.688 51.072 11.88 51.096 ;
    END
  END q[264]
  PIN q[265]
    DIRECTION OUTPUT ;
    USE SIGNAL ;
    PORT
      LAYER M4 ;
        RECT  11.688 51.264 11.88 51.288 ;
    END
  END q[265]
  PIN q[266]
    DIRECTION OUTPUT ;
    USE SIGNAL ;
    PORT
      LAYER M4 ;
        RECT  11.688 51.456 11.88 51.48 ;
    END
  END q[266]
  PIN q[267]
    DIRECTION OUTPUT ;
    USE SIGNAL ;
    PORT
      LAYER M4 ;
        RECT  11.688 51.648 11.88 51.672 ;
    END
  END q[267]
  PIN q[268]
    DIRECTION OUTPUT ;
    USE SIGNAL ;
    PORT
      LAYER M4 ;
        RECT  11.688 51.84 11.88 51.864 ;
    END
  END q[268]
  PIN q[269]
    DIRECTION OUTPUT ;
    USE SIGNAL ;
    PORT
      LAYER M4 ;
        RECT  11.688 52.032 11.88 52.056 ;
    END
  END q[269]
  PIN q[26]
    DIRECTION OUTPUT ;
    USE SIGNAL ;
    PORT
      LAYER M4 ;
        RECT  11.688 5.376 11.88 5.4 ;
    END
  END q[26]
  PIN q[270]
    DIRECTION OUTPUT ;
    USE SIGNAL ;
    PORT
      LAYER M4 ;
        RECT  11.688 52.224 11.88 52.248 ;
    END
  END q[270]
  PIN q[271]
    DIRECTION OUTPUT ;
    USE SIGNAL ;
    PORT
      LAYER M4 ;
        RECT  11.688 52.416 11.88 52.44 ;
    END
  END q[271]
  PIN q[272]
    DIRECTION OUTPUT ;
    USE SIGNAL ;
    PORT
      LAYER M4 ;
        RECT  11.688 52.608 11.88 52.632 ;
    END
  END q[272]
  PIN q[273]
    DIRECTION OUTPUT ;
    USE SIGNAL ;
    PORT
      LAYER M4 ;
        RECT  11.688 52.8 11.88 52.824 ;
    END
  END q[273]
  PIN q[274]
    DIRECTION OUTPUT ;
    USE SIGNAL ;
    PORT
      LAYER M4 ;
        RECT  11.688 52.992 11.88 53.016 ;
    END
  END q[274]
  PIN q[275]
    DIRECTION OUTPUT ;
    USE SIGNAL ;
    PORT
      LAYER M4 ;
        RECT  11.688 53.184 11.88 53.208 ;
    END
  END q[275]
  PIN q[276]
    DIRECTION OUTPUT ;
    USE SIGNAL ;
    PORT
      LAYER M4 ;
        RECT  11.688 53.376 11.88 53.4 ;
    END
  END q[276]
  PIN q[277]
    DIRECTION OUTPUT ;
    USE SIGNAL ;
    PORT
      LAYER M4 ;
        RECT  11.688 53.568 11.88 53.592 ;
    END
  END q[277]
  PIN q[278]
    DIRECTION OUTPUT ;
    USE SIGNAL ;
    PORT
      LAYER M4 ;
        RECT  11.688 53.76 11.88 53.784 ;
    END
  END q[278]
  PIN q[279]
    DIRECTION OUTPUT ;
    USE SIGNAL ;
    PORT
      LAYER M4 ;
        RECT  11.688 53.952 11.88 53.976 ;
    END
  END q[279]
  PIN q[27]
    DIRECTION OUTPUT ;
    USE SIGNAL ;
    PORT
      LAYER M4 ;
        RECT  11.688 5.568 11.88 5.592 ;
    END
  END q[27]
  PIN q[280]
    DIRECTION OUTPUT ;
    USE SIGNAL ;
    PORT
      LAYER M4 ;
        RECT  11.688 54.144 11.88 54.168 ;
    END
  END q[280]
  PIN q[281]
    DIRECTION OUTPUT ;
    USE SIGNAL ;
    PORT
      LAYER M4 ;
        RECT  11.688 54.336 11.88 54.36 ;
    END
  END q[281]
  PIN q[282]
    DIRECTION OUTPUT ;
    USE SIGNAL ;
    PORT
      LAYER M4 ;
        RECT  11.688 54.528 11.88 54.552 ;
    END
  END q[282]
  PIN q[283]
    DIRECTION OUTPUT ;
    USE SIGNAL ;
    PORT
      LAYER M4 ;
        RECT  11.688 54.72 11.88 54.744 ;
    END
  END q[283]
  PIN q[284]
    DIRECTION OUTPUT ;
    USE SIGNAL ;
    PORT
      LAYER M4 ;
        RECT  11.688 54.912 11.88 54.936 ;
    END
  END q[284]
  PIN q[285]
    DIRECTION OUTPUT ;
    USE SIGNAL ;
    PORT
      LAYER M4 ;
        RECT  11.688 55.104 11.88 55.128 ;
    END
  END q[285]
  PIN q[286]
    DIRECTION OUTPUT ;
    USE SIGNAL ;
    PORT
      LAYER M4 ;
        RECT  11.688 55.296 11.88 55.32 ;
    END
  END q[286]
  PIN q[287]
    DIRECTION OUTPUT ;
    USE SIGNAL ;
    PORT
      LAYER M4 ;
        RECT  11.688 55.488 11.88 55.512 ;
    END
  END q[287]
  PIN q[288]
    DIRECTION OUTPUT ;
    USE SIGNAL ;
    PORT
      LAYER M4 ;
        RECT  11.688 55.68 11.88 55.704 ;
    END
  END q[288]
  PIN q[289]
    DIRECTION OUTPUT ;
    USE SIGNAL ;
    PORT
      LAYER M4 ;
        RECT  11.688 55.872 11.88 55.896 ;
    END
  END q[289]
  PIN q[28]
    DIRECTION OUTPUT ;
    USE SIGNAL ;
    PORT
      LAYER M4 ;
        RECT  11.688 5.76 11.88 5.784 ;
    END
  END q[28]
  PIN q[290]
    DIRECTION OUTPUT ;
    USE SIGNAL ;
    PORT
      LAYER M4 ;
        RECT  11.688 56.064 11.88 56.088 ;
    END
  END q[290]
  PIN q[291]
    DIRECTION OUTPUT ;
    USE SIGNAL ;
    PORT
      LAYER M4 ;
        RECT  11.688 56.256 11.88 56.28 ;
    END
  END q[291]
  PIN q[292]
    DIRECTION OUTPUT ;
    USE SIGNAL ;
    PORT
      LAYER M4 ;
        RECT  11.688 56.448 11.88 56.472 ;
    END
  END q[292]
  PIN q[293]
    DIRECTION OUTPUT ;
    USE SIGNAL ;
    PORT
      LAYER M4 ;
        RECT  11.688 56.64 11.88 56.664 ;
    END
  END q[293]
  PIN q[294]
    DIRECTION OUTPUT ;
    USE SIGNAL ;
    PORT
      LAYER M4 ;
        RECT  11.688 56.832 11.88 56.856 ;
    END
  END q[294]
  PIN q[295]
    DIRECTION OUTPUT ;
    USE SIGNAL ;
    PORT
      LAYER M4 ;
        RECT  11.688 57.024 11.88 57.048 ;
    END
  END q[295]
  PIN q[296]
    DIRECTION OUTPUT ;
    USE SIGNAL ;
    PORT
      LAYER M4 ;
        RECT  11.688 57.216 11.88 57.24 ;
    END
  END q[296]
  PIN q[297]
    DIRECTION OUTPUT ;
    USE SIGNAL ;
    PORT
      LAYER M4 ;
        RECT  11.688 57.408 11.88 57.432 ;
    END
  END q[297]
  PIN q[298]
    DIRECTION OUTPUT ;
    USE SIGNAL ;
    PORT
      LAYER M4 ;
        RECT  11.688 57.6 11.88 57.624 ;
    END
  END q[298]
  PIN q[299]
    DIRECTION OUTPUT ;
    USE SIGNAL ;
    PORT
      LAYER M4 ;
        RECT  11.688 57.792 11.88 57.816 ;
    END
  END q[299]
  PIN q[29]
    DIRECTION OUTPUT ;
    USE SIGNAL ;
    PORT
      LAYER M4 ;
        RECT  11.688 5.952 11.88 5.976 ;
    END
  END q[29]
  PIN q[2]
    DIRECTION OUTPUT ;
    USE SIGNAL ;
    PORT
      LAYER M4 ;
        RECT  11.688 0.768 11.88 0.792 ;
    END
  END q[2]
  PIN q[300]
    DIRECTION OUTPUT ;
    USE SIGNAL ;
    PORT
      LAYER M4 ;
        RECT  11.688 57.984 11.88 58.008 ;
    END
  END q[300]
  PIN q[301]
    DIRECTION OUTPUT ;
    USE SIGNAL ;
    PORT
      LAYER M4 ;
        RECT  11.688 58.176 11.88 58.2 ;
    END
  END q[301]
  PIN q[302]
    DIRECTION OUTPUT ;
    USE SIGNAL ;
    PORT
      LAYER M4 ;
        RECT  11.688 58.368 11.88 58.392 ;
    END
  END q[302]
  PIN q[303]
    DIRECTION OUTPUT ;
    USE SIGNAL ;
    PORT
      LAYER M4 ;
        RECT  11.688 58.56 11.88 58.584 ;
    END
  END q[303]
  PIN q[304]
    DIRECTION OUTPUT ;
    USE SIGNAL ;
    PORT
      LAYER M4 ;
        RECT  11.688 58.752 11.88 58.776 ;
    END
  END q[304]
  PIN q[305]
    DIRECTION OUTPUT ;
    USE SIGNAL ;
    PORT
      LAYER M4 ;
        RECT  11.688 58.944 11.88 58.968 ;
    END
  END q[305]
  PIN q[306]
    DIRECTION OUTPUT ;
    USE SIGNAL ;
    PORT
      LAYER M4 ;
        RECT  11.688 59.136 11.88 59.16 ;
    END
  END q[306]
  PIN q[307]
    DIRECTION OUTPUT ;
    USE SIGNAL ;
    PORT
      LAYER M4 ;
        RECT  11.688 59.328 11.88 59.352 ;
    END
  END q[307]
  PIN q[308]
    DIRECTION OUTPUT ;
    USE SIGNAL ;
    PORT
      LAYER M4 ;
        RECT  11.688 59.52 11.88 59.544 ;
    END
  END q[308]
  PIN q[309]
    DIRECTION OUTPUT ;
    USE SIGNAL ;
    PORT
      LAYER M4 ;
        RECT  11.688 59.712 11.88 59.736 ;
    END
  END q[309]
  PIN q[30]
    DIRECTION OUTPUT ;
    USE SIGNAL ;
    PORT
      LAYER M4 ;
        RECT  11.688 6.144 11.88 6.168 ;
    END
  END q[30]
  PIN q[310]
    DIRECTION OUTPUT ;
    USE SIGNAL ;
    PORT
      LAYER M4 ;
        RECT  11.688 59.904 11.88 59.928 ;
    END
  END q[310]
  PIN q[311]
    DIRECTION OUTPUT ;
    USE SIGNAL ;
    PORT
      LAYER M4 ;
        RECT  11.688 60.096 11.88 60.12 ;
    END
  END q[311]
  PIN q[312]
    DIRECTION OUTPUT ;
    USE SIGNAL ;
    PORT
      LAYER M4 ;
        RECT  11.688 60.288 11.88 60.312 ;
    END
  END q[312]
  PIN q[313]
    DIRECTION OUTPUT ;
    USE SIGNAL ;
    PORT
      LAYER M4 ;
        RECT  11.688 60.48 11.88 60.504 ;
    END
  END q[313]
  PIN q[314]
    DIRECTION OUTPUT ;
    USE SIGNAL ;
    PORT
      LAYER M4 ;
        RECT  11.688 60.672 11.88 60.696 ;
    END
  END q[314]
  PIN q[315]
    DIRECTION OUTPUT ;
    USE SIGNAL ;
    PORT
      LAYER M4 ;
        RECT  11.688 60.864 11.88 60.888 ;
    END
  END q[315]
  PIN q[316]
    DIRECTION OUTPUT ;
    USE SIGNAL ;
    PORT
      LAYER M4 ;
        RECT  11.688 61.056 11.88 61.08 ;
    END
  END q[316]
  PIN q[317]
    DIRECTION OUTPUT ;
    USE SIGNAL ;
    PORT
      LAYER M4 ;
        RECT  11.688 61.248 11.88 61.272 ;
    END
  END q[317]
  PIN q[318]
    DIRECTION OUTPUT ;
    USE SIGNAL ;
    PORT
      LAYER M4 ;
        RECT  11.688 61.44 11.88 61.464 ;
    END
  END q[318]
  PIN q[319]
    DIRECTION OUTPUT ;
    USE SIGNAL ;
    PORT
      LAYER M4 ;
        RECT  11.688 61.632 11.88 61.656 ;
    END
  END q[319]
  PIN q[31]
    DIRECTION OUTPUT ;
    USE SIGNAL ;
    PORT
      LAYER M4 ;
        RECT  11.688 6.336 11.88 6.36 ;
    END
  END q[31]
  PIN q[320]
    DIRECTION OUTPUT ;
    USE SIGNAL ;
    PORT
      LAYER M4 ;
        RECT  11.688 61.824 11.88 61.848 ;
    END
  END q[320]
  PIN q[321]
    DIRECTION OUTPUT ;
    USE SIGNAL ;
    PORT
      LAYER M4 ;
        RECT  11.688 62.016 11.88 62.04 ;
    END
  END q[321]
  PIN q[322]
    DIRECTION OUTPUT ;
    USE SIGNAL ;
    PORT
      LAYER M4 ;
        RECT  11.688 62.208 11.88 62.232 ;
    END
  END q[322]
  PIN q[323]
    DIRECTION OUTPUT ;
    USE SIGNAL ;
    PORT
      LAYER M4 ;
        RECT  11.688 62.4 11.88 62.424 ;
    END
  END q[323]
  PIN q[324]
    DIRECTION OUTPUT ;
    USE SIGNAL ;
    PORT
      LAYER M4 ;
        RECT  11.688 62.592 11.88 62.616 ;
    END
  END q[324]
  PIN q[325]
    DIRECTION OUTPUT ;
    USE SIGNAL ;
    PORT
      LAYER M4 ;
        RECT  11.688 62.784 11.88 62.808 ;
    END
  END q[325]
  PIN q[326]
    DIRECTION OUTPUT ;
    USE SIGNAL ;
    PORT
      LAYER M4 ;
        RECT  11.688 62.976 11.88 63 ;
    END
  END q[326]
  PIN q[327]
    DIRECTION OUTPUT ;
    USE SIGNAL ;
    PORT
      LAYER M4 ;
        RECT  11.688 63.168 11.88 63.192 ;
    END
  END q[327]
  PIN q[328]
    DIRECTION OUTPUT ;
    USE SIGNAL ;
    PORT
      LAYER M4 ;
        RECT  11.688 63.36 11.88 63.384 ;
    END
  END q[328]
  PIN q[329]
    DIRECTION OUTPUT ;
    USE SIGNAL ;
    PORT
      LAYER M4 ;
        RECT  11.688 63.552 11.88 63.576 ;
    END
  END q[329]
  PIN q[32]
    DIRECTION OUTPUT ;
    USE SIGNAL ;
    PORT
      LAYER M4 ;
        RECT  11.688 6.528 11.88 6.552 ;
    END
  END q[32]
  PIN q[330]
    DIRECTION OUTPUT ;
    USE SIGNAL ;
    PORT
      LAYER M4 ;
        RECT  11.688 63.744 11.88 63.768 ;
    END
  END q[330]
  PIN q[331]
    DIRECTION OUTPUT ;
    USE SIGNAL ;
    PORT
      LAYER M4 ;
        RECT  11.688 63.936 11.88 63.96 ;
    END
  END q[331]
  PIN q[332]
    DIRECTION OUTPUT ;
    USE SIGNAL ;
    PORT
      LAYER M4 ;
        RECT  11.688 64.128 11.88 64.152 ;
    END
  END q[332]
  PIN q[333]
    DIRECTION OUTPUT ;
    USE SIGNAL ;
    PORT
      LAYER M4 ;
        RECT  11.688 64.32 11.88 64.344 ;
    END
  END q[333]
  PIN q[334]
    DIRECTION OUTPUT ;
    USE SIGNAL ;
    PORT
      LAYER M4 ;
        RECT  11.688 64.512 11.88 64.536 ;
    END
  END q[334]
  PIN q[335]
    DIRECTION OUTPUT ;
    USE SIGNAL ;
    PORT
      LAYER M4 ;
        RECT  11.688 64.704 11.88 64.728 ;
    END
  END q[335]
  PIN q[336]
    DIRECTION OUTPUT ;
    USE SIGNAL ;
    PORT
      LAYER M4 ;
        RECT  11.688 64.896 11.88 64.92 ;
    END
  END q[336]
  PIN q[337]
    DIRECTION OUTPUT ;
    USE SIGNAL ;
    PORT
      LAYER M4 ;
        RECT  11.688 65.088 11.88 65.112 ;
    END
  END q[337]
  PIN q[338]
    DIRECTION OUTPUT ;
    USE SIGNAL ;
    PORT
      LAYER M4 ;
        RECT  11.688 65.28 11.88 65.304 ;
    END
  END q[338]
  PIN q[339]
    DIRECTION OUTPUT ;
    USE SIGNAL ;
    PORT
      LAYER M4 ;
        RECT  11.688 65.472 11.88 65.496 ;
    END
  END q[339]
  PIN q[33]
    DIRECTION OUTPUT ;
    USE SIGNAL ;
    PORT
      LAYER M4 ;
        RECT  11.688 6.72 11.88 6.744 ;
    END
  END q[33]
  PIN q[340]
    DIRECTION OUTPUT ;
    USE SIGNAL ;
    PORT
      LAYER M4 ;
        RECT  11.688 65.664 11.88 65.688 ;
    END
  END q[340]
  PIN q[341]
    DIRECTION OUTPUT ;
    USE SIGNAL ;
    PORT
      LAYER M4 ;
        RECT  11.688 65.856 11.88 65.88 ;
    END
  END q[341]
  PIN q[342]
    DIRECTION OUTPUT ;
    USE SIGNAL ;
    PORT
      LAYER M4 ;
        RECT  11.688 66.048 11.88 66.072 ;
    END
  END q[342]
  PIN q[343]
    DIRECTION OUTPUT ;
    USE SIGNAL ;
    PORT
      LAYER M4 ;
        RECT  11.688 66.24 11.88 66.264 ;
    END
  END q[343]
  PIN q[344]
    DIRECTION OUTPUT ;
    USE SIGNAL ;
    PORT
      LAYER M4 ;
        RECT  11.688 66.432 11.88 66.456 ;
    END
  END q[344]
  PIN q[345]
    DIRECTION OUTPUT ;
    USE SIGNAL ;
    PORT
      LAYER M4 ;
        RECT  11.688 66.624 11.88 66.648 ;
    END
  END q[345]
  PIN q[346]
    DIRECTION OUTPUT ;
    USE SIGNAL ;
    PORT
      LAYER M4 ;
        RECT  11.688 66.816 11.88 66.84 ;
    END
  END q[346]
  PIN q[347]
    DIRECTION OUTPUT ;
    USE SIGNAL ;
    PORT
      LAYER M4 ;
        RECT  11.688 67.008 11.88 67.032 ;
    END
  END q[347]
  PIN q[348]
    DIRECTION OUTPUT ;
    USE SIGNAL ;
    PORT
      LAYER M4 ;
        RECT  11.688 67.2 11.88 67.224 ;
    END
  END q[348]
  PIN q[349]
    DIRECTION OUTPUT ;
    USE SIGNAL ;
    PORT
      LAYER M4 ;
        RECT  11.688 67.392 11.88 67.416 ;
    END
  END q[349]
  PIN q[34]
    DIRECTION OUTPUT ;
    USE SIGNAL ;
    PORT
      LAYER M4 ;
        RECT  11.688 6.912 11.88 6.936 ;
    END
  END q[34]
  PIN q[350]
    DIRECTION OUTPUT ;
    USE SIGNAL ;
    PORT
      LAYER M4 ;
        RECT  11.688 67.584 11.88 67.608 ;
    END
  END q[350]
  PIN q[351]
    DIRECTION OUTPUT ;
    USE SIGNAL ;
    PORT
      LAYER M4 ;
        RECT  11.688 67.776 11.88 67.8 ;
    END
  END q[351]
  PIN q[352]
    DIRECTION OUTPUT ;
    USE SIGNAL ;
    PORT
      LAYER M4 ;
        RECT  11.688 67.968 11.88 67.992 ;
    END
  END q[352]
  PIN q[353]
    DIRECTION OUTPUT ;
    USE SIGNAL ;
    PORT
      LAYER M4 ;
        RECT  11.688 68.16 11.88 68.184 ;
    END
  END q[353]
  PIN q[354]
    DIRECTION OUTPUT ;
    USE SIGNAL ;
    PORT
      LAYER M4 ;
        RECT  11.688 68.352 11.88 68.376 ;
    END
  END q[354]
  PIN q[355]
    DIRECTION OUTPUT ;
    USE SIGNAL ;
    PORT
      LAYER M4 ;
        RECT  11.688 68.544 11.88 68.568 ;
    END
  END q[355]
  PIN q[356]
    DIRECTION OUTPUT ;
    USE SIGNAL ;
    PORT
      LAYER M4 ;
        RECT  11.688 68.736 11.88 68.76 ;
    END
  END q[356]
  PIN q[357]
    DIRECTION OUTPUT ;
    USE SIGNAL ;
    PORT
      LAYER M4 ;
        RECT  11.688 68.928 11.88 68.952 ;
    END
  END q[357]
  PIN q[358]
    DIRECTION OUTPUT ;
    USE SIGNAL ;
    PORT
      LAYER M4 ;
        RECT  11.688 69.12 11.88 69.144 ;
    END
  END q[358]
  PIN q[359]
    DIRECTION OUTPUT ;
    USE SIGNAL ;
    PORT
      LAYER M4 ;
        RECT  11.688 69.312 11.88 69.336 ;
    END
  END q[359]
  PIN q[35]
    DIRECTION OUTPUT ;
    USE SIGNAL ;
    PORT
      LAYER M4 ;
        RECT  11.688 7.104 11.88 7.128 ;
    END
  END q[35]
  PIN q[360]
    DIRECTION OUTPUT ;
    USE SIGNAL ;
    PORT
      LAYER M4 ;
        RECT  11.688 69.504 11.88 69.528 ;
    END
  END q[360]
  PIN q[361]
    DIRECTION OUTPUT ;
    USE SIGNAL ;
    PORT
      LAYER M4 ;
        RECT  11.688 69.696 11.88 69.72 ;
    END
  END q[361]
  PIN q[362]
    DIRECTION OUTPUT ;
    USE SIGNAL ;
    PORT
      LAYER M4 ;
        RECT  11.688 69.888 11.88 69.912 ;
    END
  END q[362]
  PIN q[363]
    DIRECTION OUTPUT ;
    USE SIGNAL ;
    PORT
      LAYER M4 ;
        RECT  11.688 70.08 11.88 70.104 ;
    END
  END q[363]
  PIN q[364]
    DIRECTION OUTPUT ;
    USE SIGNAL ;
    PORT
      LAYER M4 ;
        RECT  11.688 70.272 11.88 70.296 ;
    END
  END q[364]
  PIN q[365]
    DIRECTION OUTPUT ;
    USE SIGNAL ;
    PORT
      LAYER M4 ;
        RECT  11.688 70.464 11.88 70.488 ;
    END
  END q[365]
  PIN q[366]
    DIRECTION OUTPUT ;
    USE SIGNAL ;
    PORT
      LAYER M4 ;
        RECT  11.688 70.656 11.88 70.68 ;
    END
  END q[366]
  PIN q[367]
    DIRECTION OUTPUT ;
    USE SIGNAL ;
    PORT
      LAYER M4 ;
        RECT  11.688 70.848 11.88 70.872 ;
    END
  END q[367]
  PIN q[368]
    DIRECTION OUTPUT ;
    USE SIGNAL ;
    PORT
      LAYER M4 ;
        RECT  11.688 71.04 11.88 71.064 ;
    END
  END q[368]
  PIN q[369]
    DIRECTION OUTPUT ;
    USE SIGNAL ;
    PORT
      LAYER M4 ;
        RECT  11.688 71.232 11.88 71.256 ;
    END
  END q[369]
  PIN q[36]
    DIRECTION OUTPUT ;
    USE SIGNAL ;
    PORT
      LAYER M4 ;
        RECT  11.688 7.296 11.88 7.32 ;
    END
  END q[36]
  PIN q[370]
    DIRECTION OUTPUT ;
    USE SIGNAL ;
    PORT
      LAYER M4 ;
        RECT  11.688 71.424 11.88 71.448 ;
    END
  END q[370]
  PIN q[371]
    DIRECTION OUTPUT ;
    USE SIGNAL ;
    PORT
      LAYER M4 ;
        RECT  11.688 71.616 11.88 71.64 ;
    END
  END q[371]
  PIN q[372]
    DIRECTION OUTPUT ;
    USE SIGNAL ;
    PORT
      LAYER M4 ;
        RECT  11.688 71.808 11.88 71.832 ;
    END
  END q[372]
  PIN q[373]
    DIRECTION OUTPUT ;
    USE SIGNAL ;
    PORT
      LAYER M4 ;
        RECT  11.688 72 11.88 72.024 ;
    END
  END q[373]
  PIN q[374]
    DIRECTION OUTPUT ;
    USE SIGNAL ;
    PORT
      LAYER M4 ;
        RECT  11.688 72.192 11.88 72.216 ;
    END
  END q[374]
  PIN q[375]
    DIRECTION OUTPUT ;
    USE SIGNAL ;
    PORT
      LAYER M4 ;
        RECT  11.688 72.384 11.88 72.408 ;
    END
  END q[375]
  PIN q[376]
    DIRECTION OUTPUT ;
    USE SIGNAL ;
    PORT
      LAYER M4 ;
        RECT  11.688 72.576 11.88 72.6 ;
    END
  END q[376]
  PIN q[377]
    DIRECTION OUTPUT ;
    USE SIGNAL ;
    PORT
      LAYER M4 ;
        RECT  11.688 72.768 11.88 72.792 ;
    END
  END q[377]
  PIN q[378]
    DIRECTION OUTPUT ;
    USE SIGNAL ;
    PORT
      LAYER M4 ;
        RECT  11.688 72.96 11.88 72.984 ;
    END
  END q[378]
  PIN q[379]
    DIRECTION OUTPUT ;
    USE SIGNAL ;
    PORT
      LAYER M4 ;
        RECT  11.688 73.152 11.88 73.176 ;
    END
  END q[379]
  PIN q[37]
    DIRECTION OUTPUT ;
    USE SIGNAL ;
    PORT
      LAYER M4 ;
        RECT  11.688 7.488 11.88 7.512 ;
    END
  END q[37]
  PIN q[380]
    DIRECTION OUTPUT ;
    USE SIGNAL ;
    PORT
      LAYER M4 ;
        RECT  11.688 73.344 11.88 73.368 ;
    END
  END q[380]
  PIN q[381]
    DIRECTION OUTPUT ;
    USE SIGNAL ;
    PORT
      LAYER M4 ;
        RECT  11.688 73.536 11.88 73.56 ;
    END
  END q[381]
  PIN q[382]
    DIRECTION OUTPUT ;
    USE SIGNAL ;
    PORT
      LAYER M4 ;
        RECT  11.688 73.728 11.88 73.752 ;
    END
  END q[382]
  PIN q[383]
    DIRECTION OUTPUT ;
    USE SIGNAL ;
    PORT
      LAYER M4 ;
        RECT  11.688 73.92 11.88 73.944 ;
    END
  END q[383]
  PIN q[384]
    DIRECTION OUTPUT ;
    USE SIGNAL ;
    PORT
      LAYER M4 ;
        RECT  11.688 74.112 11.88 74.136 ;
    END
  END q[384]
  PIN q[385]
    DIRECTION OUTPUT ;
    USE SIGNAL ;
    PORT
      LAYER M4 ;
        RECT  11.688 74.304 11.88 74.328 ;
    END
  END q[385]
  PIN q[386]
    DIRECTION OUTPUT ;
    USE SIGNAL ;
    PORT
      LAYER M4 ;
        RECT  11.688 74.496 11.88 74.52 ;
    END
  END q[386]
  PIN q[387]
    DIRECTION OUTPUT ;
    USE SIGNAL ;
    PORT
      LAYER M4 ;
        RECT  11.688 74.688 11.88 74.712 ;
    END
  END q[387]
  PIN q[388]
    DIRECTION OUTPUT ;
    USE SIGNAL ;
    PORT
      LAYER M4 ;
        RECT  11.688 74.88 11.88 74.904 ;
    END
  END q[388]
  PIN q[389]
    DIRECTION OUTPUT ;
    USE SIGNAL ;
    PORT
      LAYER M4 ;
        RECT  11.688 75.072 11.88 75.096 ;
    END
  END q[389]
  PIN q[38]
    DIRECTION OUTPUT ;
    USE SIGNAL ;
    PORT
      LAYER M4 ;
        RECT  11.688 7.68 11.88 7.704 ;
    END
  END q[38]
  PIN q[390]
    DIRECTION OUTPUT ;
    USE SIGNAL ;
    PORT
      LAYER M4 ;
        RECT  11.688 75.264 11.88 75.288 ;
    END
  END q[390]
  PIN q[391]
    DIRECTION OUTPUT ;
    USE SIGNAL ;
    PORT
      LAYER M4 ;
        RECT  11.688 75.456 11.88 75.48 ;
    END
  END q[391]
  PIN q[392]
    DIRECTION OUTPUT ;
    USE SIGNAL ;
    PORT
      LAYER M4 ;
        RECT  11.688 75.648 11.88 75.672 ;
    END
  END q[392]
  PIN q[393]
    DIRECTION OUTPUT ;
    USE SIGNAL ;
    PORT
      LAYER M4 ;
        RECT  11.688 75.84 11.88 75.864 ;
    END
  END q[393]
  PIN q[394]
    DIRECTION OUTPUT ;
    USE SIGNAL ;
    PORT
      LAYER M4 ;
        RECT  11.688 76.032 11.88 76.056 ;
    END
  END q[394]
  PIN q[395]
    DIRECTION OUTPUT ;
    USE SIGNAL ;
    PORT
      LAYER M4 ;
        RECT  11.688 76.224 11.88 76.248 ;
    END
  END q[395]
  PIN q[396]
    DIRECTION OUTPUT ;
    USE SIGNAL ;
    PORT
      LAYER M4 ;
        RECT  11.688 76.416 11.88 76.44 ;
    END
  END q[396]
  PIN q[397]
    DIRECTION OUTPUT ;
    USE SIGNAL ;
    PORT
      LAYER M4 ;
        RECT  11.688 76.608 11.88 76.632 ;
    END
  END q[397]
  PIN q[398]
    DIRECTION OUTPUT ;
    USE SIGNAL ;
    PORT
      LAYER M4 ;
        RECT  11.688 76.8 11.88 76.824 ;
    END
  END q[398]
  PIN q[399]
    DIRECTION OUTPUT ;
    USE SIGNAL ;
    PORT
      LAYER M4 ;
        RECT  11.688 76.992 11.88 77.016 ;
    END
  END q[399]
  PIN q[39]
    DIRECTION OUTPUT ;
    USE SIGNAL ;
    PORT
      LAYER M4 ;
        RECT  11.688 7.872 11.88 7.896 ;
    END
  END q[39]
  PIN q[3]
    DIRECTION OUTPUT ;
    USE SIGNAL ;
    PORT
      LAYER M4 ;
        RECT  11.688 0.96 11.88 0.984 ;
    END
  END q[3]
  PIN q[400]
    DIRECTION OUTPUT ;
    USE SIGNAL ;
    PORT
      LAYER M4 ;
        RECT  11.688 77.184 11.88 77.208 ;
    END
  END q[400]
  PIN q[401]
    DIRECTION OUTPUT ;
    USE SIGNAL ;
    PORT
      LAYER M4 ;
        RECT  11.688 77.376 11.88 77.4 ;
    END
  END q[401]
  PIN q[402]
    DIRECTION OUTPUT ;
    USE SIGNAL ;
    PORT
      LAYER M4 ;
        RECT  11.688 77.568 11.88 77.592 ;
    END
  END q[402]
  PIN q[403]
    DIRECTION OUTPUT ;
    USE SIGNAL ;
    PORT
      LAYER M4 ;
        RECT  11.688 77.76 11.88 77.784 ;
    END
  END q[403]
  PIN q[404]
    DIRECTION OUTPUT ;
    USE SIGNAL ;
    PORT
      LAYER M4 ;
        RECT  11.688 77.952 11.88 77.976 ;
    END
  END q[404]
  PIN q[405]
    DIRECTION OUTPUT ;
    USE SIGNAL ;
    PORT
      LAYER M4 ;
        RECT  11.688 78.144 11.88 78.168 ;
    END
  END q[405]
  PIN q[406]
    DIRECTION OUTPUT ;
    USE SIGNAL ;
    PORT
      LAYER M4 ;
        RECT  11.688 78.336 11.88 78.36 ;
    END
  END q[406]
  PIN q[407]
    DIRECTION OUTPUT ;
    USE SIGNAL ;
    PORT
      LAYER M4 ;
        RECT  11.688 78.528 11.88 78.552 ;
    END
  END q[407]
  PIN q[408]
    DIRECTION OUTPUT ;
    USE SIGNAL ;
    PORT
      LAYER M4 ;
        RECT  11.688 78.72 11.88 78.744 ;
    END
  END q[408]
  PIN q[409]
    DIRECTION OUTPUT ;
    USE SIGNAL ;
    PORT
      LAYER M4 ;
        RECT  11.688 78.912 11.88 78.936 ;
    END
  END q[409]
  PIN q[40]
    DIRECTION OUTPUT ;
    USE SIGNAL ;
    PORT
      LAYER M4 ;
        RECT  11.688 8.064 11.88 8.088 ;
    END
  END q[40]
  PIN q[410]
    DIRECTION OUTPUT ;
    USE SIGNAL ;
    PORT
      LAYER M4 ;
        RECT  11.688 79.104 11.88 79.128 ;
    END
  END q[410]
  PIN q[411]
    DIRECTION OUTPUT ;
    USE SIGNAL ;
    PORT
      LAYER M4 ;
        RECT  11.688 79.296 11.88 79.32 ;
    END
  END q[411]
  PIN q[412]
    DIRECTION OUTPUT ;
    USE SIGNAL ;
    PORT
      LAYER M4 ;
        RECT  11.688 79.488 11.88 79.512 ;
    END
  END q[412]
  PIN q[413]
    DIRECTION OUTPUT ;
    USE SIGNAL ;
    PORT
      LAYER M4 ;
        RECT  11.688 79.68 11.88 79.704 ;
    END
  END q[413]
  PIN q[414]
    DIRECTION OUTPUT ;
    USE SIGNAL ;
    PORT
      LAYER M4 ;
        RECT  11.688 79.872 11.88 79.896 ;
    END
  END q[414]
  PIN q[415]
    DIRECTION OUTPUT ;
    USE SIGNAL ;
    PORT
      LAYER M4 ;
        RECT  11.688 80.064 11.88 80.088 ;
    END
  END q[415]
  PIN q[416]
    DIRECTION OUTPUT ;
    USE SIGNAL ;
    PORT
      LAYER M4 ;
        RECT  11.688 80.256 11.88 80.28 ;
    END
  END q[416]
  PIN q[417]
    DIRECTION OUTPUT ;
    USE SIGNAL ;
    PORT
      LAYER M4 ;
        RECT  11.688 80.448 11.88 80.472 ;
    END
  END q[417]
  PIN q[418]
    DIRECTION OUTPUT ;
    USE SIGNAL ;
    PORT
      LAYER M4 ;
        RECT  11.688 80.64 11.88 80.664 ;
    END
  END q[418]
  PIN q[419]
    DIRECTION OUTPUT ;
    USE SIGNAL ;
    PORT
      LAYER M4 ;
        RECT  11.688 80.832 11.88 80.856 ;
    END
  END q[419]
  PIN q[41]
    DIRECTION OUTPUT ;
    USE SIGNAL ;
    PORT
      LAYER M4 ;
        RECT  11.688 8.256 11.88 8.28 ;
    END
  END q[41]
  PIN q[420]
    DIRECTION OUTPUT ;
    USE SIGNAL ;
    PORT
      LAYER M4 ;
        RECT  11.688 81.024 11.88 81.048 ;
    END
  END q[420]
  PIN q[421]
    DIRECTION OUTPUT ;
    USE SIGNAL ;
    PORT
      LAYER M4 ;
        RECT  11.688 81.216 11.88 81.24 ;
    END
  END q[421]
  PIN q[422]
    DIRECTION OUTPUT ;
    USE SIGNAL ;
    PORT
      LAYER M4 ;
        RECT  11.688 81.408 11.88 81.432 ;
    END
  END q[422]
  PIN q[423]
    DIRECTION OUTPUT ;
    USE SIGNAL ;
    PORT
      LAYER M4 ;
        RECT  11.688 81.6 11.88 81.624 ;
    END
  END q[423]
  PIN q[424]
    DIRECTION OUTPUT ;
    USE SIGNAL ;
    PORT
      LAYER M4 ;
        RECT  11.688 81.792 11.88 81.816 ;
    END
  END q[424]
  PIN q[425]
    DIRECTION OUTPUT ;
    USE SIGNAL ;
    PORT
      LAYER M4 ;
        RECT  11.688 81.984 11.88 82.008 ;
    END
  END q[425]
  PIN q[426]
    DIRECTION OUTPUT ;
    USE SIGNAL ;
    PORT
      LAYER M4 ;
        RECT  11.688 82.176 11.88 82.2 ;
    END
  END q[426]
  PIN q[427]
    DIRECTION OUTPUT ;
    USE SIGNAL ;
    PORT
      LAYER M4 ;
        RECT  11.688 82.368 11.88 82.392 ;
    END
  END q[427]
  PIN q[428]
    DIRECTION OUTPUT ;
    USE SIGNAL ;
    PORT
      LAYER M4 ;
        RECT  11.688 82.56 11.88 82.584 ;
    END
  END q[428]
  PIN q[429]
    DIRECTION OUTPUT ;
    USE SIGNAL ;
    PORT
      LAYER M4 ;
        RECT  11.688 82.752 11.88 82.776 ;
    END
  END q[429]
  PIN q[42]
    DIRECTION OUTPUT ;
    USE SIGNAL ;
    PORT
      LAYER M4 ;
        RECT  11.688 8.448 11.88 8.472 ;
    END
  END q[42]
  PIN q[430]
    DIRECTION OUTPUT ;
    USE SIGNAL ;
    PORT
      LAYER M4 ;
        RECT  11.688 82.944 11.88 82.968 ;
    END
  END q[430]
  PIN q[431]
    DIRECTION OUTPUT ;
    USE SIGNAL ;
    PORT
      LAYER M4 ;
        RECT  11.688 83.136 11.88 83.16 ;
    END
  END q[431]
  PIN q[432]
    DIRECTION OUTPUT ;
    USE SIGNAL ;
    PORT
      LAYER M4 ;
        RECT  11.688 83.328 11.88 83.352 ;
    END
  END q[432]
  PIN q[433]
    DIRECTION OUTPUT ;
    USE SIGNAL ;
    PORT
      LAYER M4 ;
        RECT  11.688 83.52 11.88 83.544 ;
    END
  END q[433]
  PIN q[434]
    DIRECTION OUTPUT ;
    USE SIGNAL ;
    PORT
      LAYER M4 ;
        RECT  11.688 83.712 11.88 83.736 ;
    END
  END q[434]
  PIN q[435]
    DIRECTION OUTPUT ;
    USE SIGNAL ;
    PORT
      LAYER M4 ;
        RECT  11.688 83.904 11.88 83.928 ;
    END
  END q[435]
  PIN q[436]
    DIRECTION OUTPUT ;
    USE SIGNAL ;
    PORT
      LAYER M4 ;
        RECT  11.688 84.096 11.88 84.12 ;
    END
  END q[436]
  PIN q[437]
    DIRECTION OUTPUT ;
    USE SIGNAL ;
    PORT
      LAYER M4 ;
        RECT  11.688 84.288 11.88 84.312 ;
    END
  END q[437]
  PIN q[438]
    DIRECTION OUTPUT ;
    USE SIGNAL ;
    PORT
      LAYER M4 ;
        RECT  11.688 84.48 11.88 84.504 ;
    END
  END q[438]
  PIN q[439]
    DIRECTION OUTPUT ;
    USE SIGNAL ;
    PORT
      LAYER M4 ;
        RECT  11.688 84.672 11.88 84.696 ;
    END
  END q[439]
  PIN q[43]
    DIRECTION OUTPUT ;
    USE SIGNAL ;
    PORT
      LAYER M4 ;
        RECT  11.688 8.64 11.88 8.664 ;
    END
  END q[43]
  PIN q[440]
    DIRECTION OUTPUT ;
    USE SIGNAL ;
    PORT
      LAYER M4 ;
        RECT  11.688 84.864 11.88 84.888 ;
    END
  END q[440]
  PIN q[441]
    DIRECTION OUTPUT ;
    USE SIGNAL ;
    PORT
      LAYER M4 ;
        RECT  11.688 85.056 11.88 85.08 ;
    END
  END q[441]
  PIN q[442]
    DIRECTION OUTPUT ;
    USE SIGNAL ;
    PORT
      LAYER M4 ;
        RECT  11.688 85.248 11.88 85.272 ;
    END
  END q[442]
  PIN q[443]
    DIRECTION OUTPUT ;
    USE SIGNAL ;
    PORT
      LAYER M4 ;
        RECT  11.688 85.44 11.88 85.464 ;
    END
  END q[443]
  PIN q[444]
    DIRECTION OUTPUT ;
    USE SIGNAL ;
    PORT
      LAYER M4 ;
        RECT  11.688 85.632 11.88 85.656 ;
    END
  END q[444]
  PIN q[445]
    DIRECTION OUTPUT ;
    USE SIGNAL ;
    PORT
      LAYER M4 ;
        RECT  11.688 85.824 11.88 85.848 ;
    END
  END q[445]
  PIN q[446]
    DIRECTION OUTPUT ;
    USE SIGNAL ;
    PORT
      LAYER M4 ;
        RECT  11.688 86.016 11.88 86.04 ;
    END
  END q[446]
  PIN q[447]
    DIRECTION OUTPUT ;
    USE SIGNAL ;
    PORT
      LAYER M4 ;
        RECT  11.688 86.208 11.88 86.232 ;
    END
  END q[447]
  PIN q[448]
    DIRECTION OUTPUT ;
    USE SIGNAL ;
    PORT
      LAYER M4 ;
        RECT  11.688 86.4 11.88 86.424 ;
    END
  END q[448]
  PIN q[449]
    DIRECTION OUTPUT ;
    USE SIGNAL ;
    PORT
      LAYER M4 ;
        RECT  11.688 86.592 11.88 86.616 ;
    END
  END q[449]
  PIN q[44]
    DIRECTION OUTPUT ;
    USE SIGNAL ;
    PORT
      LAYER M4 ;
        RECT  11.688 8.832 11.88 8.856 ;
    END
  END q[44]
  PIN q[450]
    DIRECTION OUTPUT ;
    USE SIGNAL ;
    PORT
      LAYER M4 ;
        RECT  11.688 86.784 11.88 86.808 ;
    END
  END q[450]
  PIN q[451]
    DIRECTION OUTPUT ;
    USE SIGNAL ;
    PORT
      LAYER M4 ;
        RECT  11.688 86.976 11.88 87 ;
    END
  END q[451]
  PIN q[452]
    DIRECTION OUTPUT ;
    USE SIGNAL ;
    PORT
      LAYER M4 ;
        RECT  11.688 87.168 11.88 87.192 ;
    END
  END q[452]
  PIN q[453]
    DIRECTION OUTPUT ;
    USE SIGNAL ;
    PORT
      LAYER M4 ;
        RECT  11.688 87.36 11.88 87.384 ;
    END
  END q[453]
  PIN q[454]
    DIRECTION OUTPUT ;
    USE SIGNAL ;
    PORT
      LAYER M4 ;
        RECT  11.688 87.552 11.88 87.576 ;
    END
  END q[454]
  PIN q[455]
    DIRECTION OUTPUT ;
    USE SIGNAL ;
    PORT
      LAYER M4 ;
        RECT  11.688 87.744 11.88 87.768 ;
    END
  END q[455]
  PIN q[456]
    DIRECTION OUTPUT ;
    USE SIGNAL ;
    PORT
      LAYER M4 ;
        RECT  11.688 87.936 11.88 87.96 ;
    END
  END q[456]
  PIN q[457]
    DIRECTION OUTPUT ;
    USE SIGNAL ;
    PORT
      LAYER M4 ;
        RECT  11.688 88.128 11.88 88.152 ;
    END
  END q[457]
  PIN q[458]
    DIRECTION OUTPUT ;
    USE SIGNAL ;
    PORT
      LAYER M4 ;
        RECT  11.688 88.32 11.88 88.344 ;
    END
  END q[458]
  PIN q[459]
    DIRECTION OUTPUT ;
    USE SIGNAL ;
    PORT
      LAYER M4 ;
        RECT  11.688 88.512 11.88 88.536 ;
    END
  END q[459]
  PIN q[45]
    DIRECTION OUTPUT ;
    USE SIGNAL ;
    PORT
      LAYER M4 ;
        RECT  11.688 9.024 11.88 9.048 ;
    END
  END q[45]
  PIN q[460]
    DIRECTION OUTPUT ;
    USE SIGNAL ;
    PORT
      LAYER M4 ;
        RECT  11.688 88.704 11.88 88.728 ;
    END
  END q[460]
  PIN q[461]
    DIRECTION OUTPUT ;
    USE SIGNAL ;
    PORT
      LAYER M4 ;
        RECT  11.688 88.896 11.88 88.92 ;
    END
  END q[461]
  PIN q[462]
    DIRECTION OUTPUT ;
    USE SIGNAL ;
    PORT
      LAYER M4 ;
        RECT  11.688 89.088 11.88 89.112 ;
    END
  END q[462]
  PIN q[463]
    DIRECTION OUTPUT ;
    USE SIGNAL ;
    PORT
      LAYER M4 ;
        RECT  11.688 89.28 11.88 89.304 ;
    END
  END q[463]
  PIN q[464]
    DIRECTION OUTPUT ;
    USE SIGNAL ;
    PORT
      LAYER M4 ;
        RECT  11.688 89.472 11.88 89.496 ;
    END
  END q[464]
  PIN q[465]
    DIRECTION OUTPUT ;
    USE SIGNAL ;
    PORT
      LAYER M4 ;
        RECT  11.688 89.664 11.88 89.688 ;
    END
  END q[465]
  PIN q[466]
    DIRECTION OUTPUT ;
    USE SIGNAL ;
    PORT
      LAYER M4 ;
        RECT  11.688 89.856 11.88 89.88 ;
    END
  END q[466]
  PIN q[467]
    DIRECTION OUTPUT ;
    USE SIGNAL ;
    PORT
      LAYER M4 ;
        RECT  11.688 90.048 11.88 90.072 ;
    END
  END q[467]
  PIN q[468]
    DIRECTION OUTPUT ;
    USE SIGNAL ;
    PORT
      LAYER M4 ;
        RECT  11.688 90.24 11.88 90.264 ;
    END
  END q[468]
  PIN q[469]
    DIRECTION OUTPUT ;
    USE SIGNAL ;
    PORT
      LAYER M4 ;
        RECT  11.688 90.432 11.88 90.456 ;
    END
  END q[469]
  PIN q[46]
    DIRECTION OUTPUT ;
    USE SIGNAL ;
    PORT
      LAYER M4 ;
        RECT  11.688 9.216 11.88 9.24 ;
    END
  END q[46]
  PIN q[470]
    DIRECTION OUTPUT ;
    USE SIGNAL ;
    PORT
      LAYER M4 ;
        RECT  11.688 90.624 11.88 90.648 ;
    END
  END q[470]
  PIN q[471]
    DIRECTION OUTPUT ;
    USE SIGNAL ;
    PORT
      LAYER M4 ;
        RECT  11.688 90.816 11.88 90.84 ;
    END
  END q[471]
  PIN q[472]
    DIRECTION OUTPUT ;
    USE SIGNAL ;
    PORT
      LAYER M4 ;
        RECT  11.688 91.008 11.88 91.032 ;
    END
  END q[472]
  PIN q[473]
    DIRECTION OUTPUT ;
    USE SIGNAL ;
    PORT
      LAYER M4 ;
        RECT  11.688 91.2 11.88 91.224 ;
    END
  END q[473]
  PIN q[474]
    DIRECTION OUTPUT ;
    USE SIGNAL ;
    PORT
      LAYER M4 ;
        RECT  11.688 91.392 11.88 91.416 ;
    END
  END q[474]
  PIN q[475]
    DIRECTION OUTPUT ;
    USE SIGNAL ;
    PORT
      LAYER M4 ;
        RECT  11.688 91.584 11.88 91.608 ;
    END
  END q[475]
  PIN q[476]
    DIRECTION OUTPUT ;
    USE SIGNAL ;
    PORT
      LAYER M4 ;
        RECT  11.688 91.776 11.88 91.8 ;
    END
  END q[476]
  PIN q[477]
    DIRECTION OUTPUT ;
    USE SIGNAL ;
    PORT
      LAYER M4 ;
        RECT  11.688 91.968 11.88 91.992 ;
    END
  END q[477]
  PIN q[478]
    DIRECTION OUTPUT ;
    USE SIGNAL ;
    PORT
      LAYER M4 ;
        RECT  11.688 92.16 11.88 92.184 ;
    END
  END q[478]
  PIN q[479]
    DIRECTION OUTPUT ;
    USE SIGNAL ;
    PORT
      LAYER M4 ;
        RECT  11.688 92.352 11.88 92.376 ;
    END
  END q[479]
  PIN q[47]
    DIRECTION OUTPUT ;
    USE SIGNAL ;
    PORT
      LAYER M4 ;
        RECT  11.688 9.408 11.88 9.432 ;
    END
  END q[47]
  PIN q[480]
    DIRECTION OUTPUT ;
    USE SIGNAL ;
    PORT
      LAYER M4 ;
        RECT  11.688 92.544 11.88 92.568 ;
    END
  END q[480]
  PIN q[481]
    DIRECTION OUTPUT ;
    USE SIGNAL ;
    PORT
      LAYER M4 ;
        RECT  11.688 92.736 11.88 92.76 ;
    END
  END q[481]
  PIN q[482]
    DIRECTION OUTPUT ;
    USE SIGNAL ;
    PORT
      LAYER M4 ;
        RECT  11.688 92.928 11.88 92.952 ;
    END
  END q[482]
  PIN q[483]
    DIRECTION OUTPUT ;
    USE SIGNAL ;
    PORT
      LAYER M4 ;
        RECT  11.688 93.12 11.88 93.144 ;
    END
  END q[483]
  PIN q[484]
    DIRECTION OUTPUT ;
    USE SIGNAL ;
    PORT
      LAYER M4 ;
        RECT  11.688 93.312 11.88 93.336 ;
    END
  END q[484]
  PIN q[485]
    DIRECTION OUTPUT ;
    USE SIGNAL ;
    PORT
      LAYER M4 ;
        RECT  11.688 93.504 11.88 93.528 ;
    END
  END q[485]
  PIN q[486]
    DIRECTION OUTPUT ;
    USE SIGNAL ;
    PORT
      LAYER M4 ;
        RECT  11.688 93.696 11.88 93.72 ;
    END
  END q[486]
  PIN q[487]
    DIRECTION OUTPUT ;
    USE SIGNAL ;
    PORT
      LAYER M4 ;
        RECT  11.688 93.888 11.88 93.912 ;
    END
  END q[487]
  PIN q[488]
    DIRECTION OUTPUT ;
    USE SIGNAL ;
    PORT
      LAYER M4 ;
        RECT  11.688 94.08 11.88 94.104 ;
    END
  END q[488]
  PIN q[489]
    DIRECTION OUTPUT ;
    USE SIGNAL ;
    PORT
      LAYER M4 ;
        RECT  11.688 94.272 11.88 94.296 ;
    END
  END q[489]
  PIN q[48]
    DIRECTION OUTPUT ;
    USE SIGNAL ;
    PORT
      LAYER M4 ;
        RECT  11.688 9.6 11.88 9.624 ;
    END
  END q[48]
  PIN q[490]
    DIRECTION OUTPUT ;
    USE SIGNAL ;
    PORT
      LAYER M4 ;
        RECT  11.688 94.464 11.88 94.488 ;
    END
  END q[490]
  PIN q[491]
    DIRECTION OUTPUT ;
    USE SIGNAL ;
    PORT
      LAYER M4 ;
        RECT  11.688 94.656 11.88 94.68 ;
    END
  END q[491]
  PIN q[492]
    DIRECTION OUTPUT ;
    USE SIGNAL ;
    PORT
      LAYER M4 ;
        RECT  11.688 94.848 11.88 94.872 ;
    END
  END q[492]
  PIN q[493]
    DIRECTION OUTPUT ;
    USE SIGNAL ;
    PORT
      LAYER M4 ;
        RECT  11.688 95.04 11.88 95.064 ;
    END
  END q[493]
  PIN q[494]
    DIRECTION OUTPUT ;
    USE SIGNAL ;
    PORT
      LAYER M4 ;
        RECT  11.688 95.232 11.88 95.256 ;
    END
  END q[494]
  PIN q[495]
    DIRECTION OUTPUT ;
    USE SIGNAL ;
    PORT
      LAYER M4 ;
        RECT  11.688 95.424 11.88 95.448 ;
    END
  END q[495]
  PIN q[496]
    DIRECTION OUTPUT ;
    USE SIGNAL ;
    PORT
      LAYER M4 ;
        RECT  11.688 95.616 11.88 95.64 ;
    END
  END q[496]
  PIN q[497]
    DIRECTION OUTPUT ;
    USE SIGNAL ;
    PORT
      LAYER M4 ;
        RECT  11.688 95.808 11.88 95.832 ;
    END
  END q[497]
  PIN q[498]
    DIRECTION OUTPUT ;
    USE SIGNAL ;
    PORT
      LAYER M4 ;
        RECT  11.688 96 11.88 96.024 ;
    END
  END q[498]
  PIN q[499]
    DIRECTION OUTPUT ;
    USE SIGNAL ;
    PORT
      LAYER M4 ;
        RECT  11.688 96.192 11.88 96.216 ;
    END
  END q[499]
  PIN q[49]
    DIRECTION OUTPUT ;
    USE SIGNAL ;
    PORT
      LAYER M4 ;
        RECT  11.688 9.792 11.88 9.816 ;
    END
  END q[49]
  PIN q[4]
    DIRECTION OUTPUT ;
    USE SIGNAL ;
    PORT
      LAYER M4 ;
        RECT  11.688 1.152 11.88 1.176 ;
    END
  END q[4]
  PIN q[500]
    DIRECTION OUTPUT ;
    USE SIGNAL ;
    PORT
      LAYER M4 ;
        RECT  11.688 96.384 11.88 96.408 ;
    END
  END q[500]
  PIN q[501]
    DIRECTION OUTPUT ;
    USE SIGNAL ;
    PORT
      LAYER M4 ;
        RECT  11.688 96.576 11.88 96.6 ;
    END
  END q[501]
  PIN q[502]
    DIRECTION OUTPUT ;
    USE SIGNAL ;
    PORT
      LAYER M4 ;
        RECT  11.688 96.768 11.88 96.792 ;
    END
  END q[502]
  PIN q[503]
    DIRECTION OUTPUT ;
    USE SIGNAL ;
    PORT
      LAYER M4 ;
        RECT  11.688 96.96 11.88 96.984 ;
    END
  END q[503]
  PIN q[504]
    DIRECTION OUTPUT ;
    USE SIGNAL ;
    PORT
      LAYER M4 ;
        RECT  11.688 97.152 11.88 97.176 ;
    END
  END q[504]
  PIN q[505]
    DIRECTION OUTPUT ;
    USE SIGNAL ;
    PORT
      LAYER M4 ;
        RECT  11.688 97.344 11.88 97.368 ;
    END
  END q[505]
  PIN q[506]
    DIRECTION OUTPUT ;
    USE SIGNAL ;
    PORT
      LAYER M4 ;
        RECT  11.688 97.536 11.88 97.56 ;
    END
  END q[506]
  PIN q[507]
    DIRECTION OUTPUT ;
    USE SIGNAL ;
    PORT
      LAYER M4 ;
        RECT  11.688 97.728 11.88 97.752 ;
    END
  END q[507]
  PIN q[508]
    DIRECTION OUTPUT ;
    USE SIGNAL ;
    PORT
      LAYER M4 ;
        RECT  11.688 97.92 11.88 97.944 ;
    END
  END q[508]
  PIN q[509]
    DIRECTION OUTPUT ;
    USE SIGNAL ;
    PORT
      LAYER M4 ;
        RECT  11.688 98.112 11.88 98.136 ;
    END
  END q[509]
  PIN q[50]
    DIRECTION OUTPUT ;
    USE SIGNAL ;
    PORT
      LAYER M4 ;
        RECT  11.688 9.984 11.88 10.008 ;
    END
  END q[50]
  PIN q[510]
    DIRECTION OUTPUT ;
    USE SIGNAL ;
    PORT
      LAYER M4 ;
        RECT  11.688 98.304 11.88 98.328 ;
    END
  END q[510]
  PIN q[511]
    DIRECTION OUTPUT ;
    USE SIGNAL ;
    PORT
      LAYER M4 ;
        RECT  11.688 98.496 11.88 98.52 ;
    END
  END q[511]
  PIN q[512]
    DIRECTION OUTPUT ;
    USE SIGNAL ;
    PORT
      LAYER M4 ;
        RECT  11.688 98.688 11.88 98.712 ;
    END
  END q[512]
  PIN q[513]
    DIRECTION OUTPUT ;
    USE SIGNAL ;
    PORT
      LAYER M4 ;
        RECT  11.688 98.88 11.88 98.904 ;
    END
  END q[513]
  PIN q[514]
    DIRECTION OUTPUT ;
    USE SIGNAL ;
    PORT
      LAYER M4 ;
        RECT  11.688 99.072 11.88 99.096 ;
    END
  END q[514]
  PIN q[515]
    DIRECTION OUTPUT ;
    USE SIGNAL ;
    PORT
      LAYER M4 ;
        RECT  11.688 99.264 11.88 99.288 ;
    END
  END q[515]
  PIN q[516]
    DIRECTION OUTPUT ;
    USE SIGNAL ;
    PORT
      LAYER M4 ;
        RECT  11.688 99.456 11.88 99.48 ;
    END
  END q[516]
  PIN q[517]
    DIRECTION OUTPUT ;
    USE SIGNAL ;
    PORT
      LAYER M4 ;
        RECT  11.688 99.648 11.88 99.672 ;
    END
  END q[517]
  PIN q[518]
    DIRECTION OUTPUT ;
    USE SIGNAL ;
    PORT
      LAYER M4 ;
        RECT  11.688 99.84 11.88 99.864 ;
    END
  END q[518]
  PIN q[519]
    DIRECTION OUTPUT ;
    USE SIGNAL ;
    PORT
      LAYER M4 ;
        RECT  11.688 100.032 11.88 100.056 ;
    END
  END q[519]
  PIN q[51]
    DIRECTION OUTPUT ;
    USE SIGNAL ;
    PORT
      LAYER M4 ;
        RECT  11.688 10.176 11.88 10.2 ;
    END
  END q[51]
  PIN q[520]
    DIRECTION OUTPUT ;
    USE SIGNAL ;
    PORT
      LAYER M4 ;
        RECT  11.688 100.224 11.88 100.248 ;
    END
  END q[520]
  PIN q[521]
    DIRECTION OUTPUT ;
    USE SIGNAL ;
    PORT
      LAYER M4 ;
        RECT  11.688 100.416 11.88 100.44 ;
    END
  END q[521]
  PIN q[522]
    DIRECTION OUTPUT ;
    USE SIGNAL ;
    PORT
      LAYER M4 ;
        RECT  11.688 100.608 11.88 100.632 ;
    END
  END q[522]
  PIN q[523]
    DIRECTION OUTPUT ;
    USE SIGNAL ;
    PORT
      LAYER M4 ;
        RECT  11.688 100.8 11.88 100.824 ;
    END
  END q[523]
  PIN q[524]
    DIRECTION OUTPUT ;
    USE SIGNAL ;
    PORT
      LAYER M4 ;
        RECT  11.688 100.992 11.88 101.016 ;
    END
  END q[524]
  PIN q[525]
    DIRECTION OUTPUT ;
    USE SIGNAL ;
    PORT
      LAYER M4 ;
        RECT  11.688 101.184 11.88 101.208 ;
    END
  END q[525]
  PIN q[526]
    DIRECTION OUTPUT ;
    USE SIGNAL ;
    PORT
      LAYER M4 ;
        RECT  11.688 101.376 11.88 101.4 ;
    END
  END q[526]
  PIN q[527]
    DIRECTION OUTPUT ;
    USE SIGNAL ;
    PORT
      LAYER M4 ;
        RECT  11.688 101.568 11.88 101.592 ;
    END
  END q[527]
  PIN q[528]
    DIRECTION OUTPUT ;
    USE SIGNAL ;
    PORT
      LAYER M4 ;
        RECT  11.688 101.76 11.88 101.784 ;
    END
  END q[528]
  PIN q[529]
    DIRECTION OUTPUT ;
    USE SIGNAL ;
    PORT
      LAYER M4 ;
        RECT  11.688 101.952 11.88 101.976 ;
    END
  END q[529]
  PIN q[52]
    DIRECTION OUTPUT ;
    USE SIGNAL ;
    PORT
      LAYER M4 ;
        RECT  11.688 10.368 11.88 10.392 ;
    END
  END q[52]
  PIN q[530]
    DIRECTION OUTPUT ;
    USE SIGNAL ;
    PORT
      LAYER M4 ;
        RECT  11.688 102.144 11.88 102.168 ;
    END
  END q[530]
  PIN q[531]
    DIRECTION OUTPUT ;
    USE SIGNAL ;
    PORT
      LAYER M4 ;
        RECT  11.688 102.336 11.88 102.36 ;
    END
  END q[531]
  PIN q[532]
    DIRECTION OUTPUT ;
    USE SIGNAL ;
    PORT
      LAYER M4 ;
        RECT  11.688 102.528 11.88 102.552 ;
    END
  END q[532]
  PIN q[533]
    DIRECTION OUTPUT ;
    USE SIGNAL ;
    PORT
      LAYER M4 ;
        RECT  11.688 102.72 11.88 102.744 ;
    END
  END q[533]
  PIN q[534]
    DIRECTION OUTPUT ;
    USE SIGNAL ;
    PORT
      LAYER M4 ;
        RECT  11.688 102.912 11.88 102.936 ;
    END
  END q[534]
  PIN q[535]
    DIRECTION OUTPUT ;
    USE SIGNAL ;
    PORT
      LAYER M4 ;
        RECT  11.688 103.104 11.88 103.128 ;
    END
  END q[535]
  PIN q[536]
    DIRECTION OUTPUT ;
    USE SIGNAL ;
    PORT
      LAYER M4 ;
        RECT  11.688 103.296 11.88 103.32 ;
    END
  END q[536]
  PIN q[537]
    DIRECTION OUTPUT ;
    USE SIGNAL ;
    PORT
      LAYER M4 ;
        RECT  11.688 103.488 11.88 103.512 ;
    END
  END q[537]
  PIN q[538]
    DIRECTION OUTPUT ;
    USE SIGNAL ;
    PORT
      LAYER M4 ;
        RECT  11.688 103.68 11.88 103.704 ;
    END
  END q[538]
  PIN q[539]
    DIRECTION OUTPUT ;
    USE SIGNAL ;
    PORT
      LAYER M4 ;
        RECT  11.688 103.872 11.88 103.896 ;
    END
  END q[539]
  PIN q[53]
    DIRECTION OUTPUT ;
    USE SIGNAL ;
    PORT
      LAYER M4 ;
        RECT  11.688 10.56 11.88 10.584 ;
    END
  END q[53]
  PIN q[540]
    DIRECTION OUTPUT ;
    USE SIGNAL ;
    PORT
      LAYER M4 ;
        RECT  11.688 104.064 11.88 104.088 ;
    END
  END q[540]
  PIN q[541]
    DIRECTION OUTPUT ;
    USE SIGNAL ;
    PORT
      LAYER M4 ;
        RECT  11.688 104.256 11.88 104.28 ;
    END
  END q[541]
  PIN q[542]
    DIRECTION OUTPUT ;
    USE SIGNAL ;
    PORT
      LAYER M4 ;
        RECT  11.688 104.448 11.88 104.472 ;
    END
  END q[542]
  PIN q[543]
    DIRECTION OUTPUT ;
    USE SIGNAL ;
    PORT
      LAYER M4 ;
        RECT  11.688 104.64 11.88 104.664 ;
    END
  END q[543]
  PIN q[54]
    DIRECTION OUTPUT ;
    USE SIGNAL ;
    PORT
      LAYER M4 ;
        RECT  11.688 10.752 11.88 10.776 ;
    END
  END q[54]
  PIN q[55]
    DIRECTION OUTPUT ;
    USE SIGNAL ;
    PORT
      LAYER M4 ;
        RECT  11.688 10.944 11.88 10.968 ;
    END
  END q[55]
  PIN q[56]
    DIRECTION OUTPUT ;
    USE SIGNAL ;
    PORT
      LAYER M4 ;
        RECT  11.688 11.136 11.88 11.16 ;
    END
  END q[56]
  PIN q[57]
    DIRECTION OUTPUT ;
    USE SIGNAL ;
    PORT
      LAYER M4 ;
        RECT  11.688 11.328 11.88 11.352 ;
    END
  END q[57]
  PIN q[58]
    DIRECTION OUTPUT ;
    USE SIGNAL ;
    PORT
      LAYER M4 ;
        RECT  11.688 11.52 11.88 11.544 ;
    END
  END q[58]
  PIN q[59]
    DIRECTION OUTPUT ;
    USE SIGNAL ;
    PORT
      LAYER M4 ;
        RECT  11.688 11.712 11.88 11.736 ;
    END
  END q[59]
  PIN q[5]
    DIRECTION OUTPUT ;
    USE SIGNAL ;
    PORT
      LAYER M4 ;
        RECT  11.688 1.344 11.88 1.368 ;
    END
  END q[5]
  PIN q[60]
    DIRECTION OUTPUT ;
    USE SIGNAL ;
    PORT
      LAYER M4 ;
        RECT  11.688 11.904 11.88 11.928 ;
    END
  END q[60]
  PIN q[61]
    DIRECTION OUTPUT ;
    USE SIGNAL ;
    PORT
      LAYER M4 ;
        RECT  11.688 12.096 11.88 12.12 ;
    END
  END q[61]
  PIN q[62]
    DIRECTION OUTPUT ;
    USE SIGNAL ;
    PORT
      LAYER M4 ;
        RECT  11.688 12.288 11.88 12.312 ;
    END
  END q[62]
  PIN q[63]
    DIRECTION OUTPUT ;
    USE SIGNAL ;
    PORT
      LAYER M4 ;
        RECT  11.688 12.48 11.88 12.504 ;
    END
  END q[63]
  PIN q[64]
    DIRECTION OUTPUT ;
    USE SIGNAL ;
    PORT
      LAYER M4 ;
        RECT  11.688 12.672 11.88 12.696 ;
    END
  END q[64]
  PIN q[65]
    DIRECTION OUTPUT ;
    USE SIGNAL ;
    PORT
      LAYER M4 ;
        RECT  11.688 12.864 11.88 12.888 ;
    END
  END q[65]
  PIN q[66]
    DIRECTION OUTPUT ;
    USE SIGNAL ;
    PORT
      LAYER M4 ;
        RECT  11.688 13.056 11.88 13.08 ;
    END
  END q[66]
  PIN q[67]
    DIRECTION OUTPUT ;
    USE SIGNAL ;
    PORT
      LAYER M4 ;
        RECT  11.688 13.248 11.88 13.272 ;
    END
  END q[67]
  PIN q[68]
    DIRECTION OUTPUT ;
    USE SIGNAL ;
    PORT
      LAYER M4 ;
        RECT  11.688 13.44 11.88 13.464 ;
    END
  END q[68]
  PIN q[69]
    DIRECTION OUTPUT ;
    USE SIGNAL ;
    PORT
      LAYER M4 ;
        RECT  11.688 13.632 11.88 13.656 ;
    END
  END q[69]
  PIN q[6]
    DIRECTION OUTPUT ;
    USE SIGNAL ;
    PORT
      LAYER M4 ;
        RECT  11.688 1.536 11.88 1.56 ;
    END
  END q[6]
  PIN q[70]
    DIRECTION OUTPUT ;
    USE SIGNAL ;
    PORT
      LAYER M4 ;
        RECT  11.688 13.824 11.88 13.848 ;
    END
  END q[70]
  PIN q[71]
    DIRECTION OUTPUT ;
    USE SIGNAL ;
    PORT
      LAYER M4 ;
        RECT  11.688 14.016 11.88 14.04 ;
    END
  END q[71]
  PIN q[72]
    DIRECTION OUTPUT ;
    USE SIGNAL ;
    PORT
      LAYER M4 ;
        RECT  11.688 14.208 11.88 14.232 ;
    END
  END q[72]
  PIN q[73]
    DIRECTION OUTPUT ;
    USE SIGNAL ;
    PORT
      LAYER M4 ;
        RECT  11.688 14.4 11.88 14.424 ;
    END
  END q[73]
  PIN q[74]
    DIRECTION OUTPUT ;
    USE SIGNAL ;
    PORT
      LAYER M4 ;
        RECT  11.688 14.592 11.88 14.616 ;
    END
  END q[74]
  PIN q[75]
    DIRECTION OUTPUT ;
    USE SIGNAL ;
    PORT
      LAYER M4 ;
        RECT  11.688 14.784 11.88 14.808 ;
    END
  END q[75]
  PIN q[76]
    DIRECTION OUTPUT ;
    USE SIGNAL ;
    PORT
      LAYER M4 ;
        RECT  11.688 14.976 11.88 15 ;
    END
  END q[76]
  PIN q[77]
    DIRECTION OUTPUT ;
    USE SIGNAL ;
    PORT
      LAYER M4 ;
        RECT  11.688 15.168 11.88 15.192 ;
    END
  END q[77]
  PIN q[78]
    DIRECTION OUTPUT ;
    USE SIGNAL ;
    PORT
      LAYER M4 ;
        RECT  11.688 15.36 11.88 15.384 ;
    END
  END q[78]
  PIN q[79]
    DIRECTION OUTPUT ;
    USE SIGNAL ;
    PORT
      LAYER M4 ;
        RECT  11.688 15.552 11.88 15.576 ;
    END
  END q[79]
  PIN q[7]
    DIRECTION OUTPUT ;
    USE SIGNAL ;
    PORT
      LAYER M4 ;
        RECT  11.688 1.728 11.88 1.752 ;
    END
  END q[7]
  PIN q[80]
    DIRECTION OUTPUT ;
    USE SIGNAL ;
    PORT
      LAYER M4 ;
        RECT  11.688 15.744 11.88 15.768 ;
    END
  END q[80]
  PIN q[81]
    DIRECTION OUTPUT ;
    USE SIGNAL ;
    PORT
      LAYER M4 ;
        RECT  11.688 15.936 11.88 15.96 ;
    END
  END q[81]
  PIN q[82]
    DIRECTION OUTPUT ;
    USE SIGNAL ;
    PORT
      LAYER M4 ;
        RECT  11.688 16.128 11.88 16.152 ;
    END
  END q[82]
  PIN q[83]
    DIRECTION OUTPUT ;
    USE SIGNAL ;
    PORT
      LAYER M4 ;
        RECT  11.688 16.32 11.88 16.344 ;
    END
  END q[83]
  PIN q[84]
    DIRECTION OUTPUT ;
    USE SIGNAL ;
    PORT
      LAYER M4 ;
        RECT  11.688 16.512 11.88 16.536 ;
    END
  END q[84]
  PIN q[85]
    DIRECTION OUTPUT ;
    USE SIGNAL ;
    PORT
      LAYER M4 ;
        RECT  11.688 16.704 11.88 16.728 ;
    END
  END q[85]
  PIN q[86]
    DIRECTION OUTPUT ;
    USE SIGNAL ;
    PORT
      LAYER M4 ;
        RECT  11.688 16.896 11.88 16.92 ;
    END
  END q[86]
  PIN q[87]
    DIRECTION OUTPUT ;
    USE SIGNAL ;
    PORT
      LAYER M4 ;
        RECT  11.688 17.088 11.88 17.112 ;
    END
  END q[87]
  PIN q[88]
    DIRECTION OUTPUT ;
    USE SIGNAL ;
    PORT
      LAYER M4 ;
        RECT  11.688 17.28 11.88 17.304 ;
    END
  END q[88]
  PIN q[89]
    DIRECTION OUTPUT ;
    USE SIGNAL ;
    PORT
      LAYER M4 ;
        RECT  11.688 17.472 11.88 17.496 ;
    END
  END q[89]
  PIN q[8]
    DIRECTION OUTPUT ;
    USE SIGNAL ;
    PORT
      LAYER M4 ;
        RECT  11.688 1.92 11.88 1.944 ;
    END
  END q[8]
  PIN q[90]
    DIRECTION OUTPUT ;
    USE SIGNAL ;
    PORT
      LAYER M4 ;
        RECT  11.688 17.664 11.88 17.688 ;
    END
  END q[90]
  PIN q[91]
    DIRECTION OUTPUT ;
    USE SIGNAL ;
    PORT
      LAYER M4 ;
        RECT  11.688 17.856 11.88 17.88 ;
    END
  END q[91]
  PIN q[92]
    DIRECTION OUTPUT ;
    USE SIGNAL ;
    PORT
      LAYER M4 ;
        RECT  11.688 18.048 11.88 18.072 ;
    END
  END q[92]
  PIN q[93]
    DIRECTION OUTPUT ;
    USE SIGNAL ;
    PORT
      LAYER M4 ;
        RECT  11.688 18.24 11.88 18.264 ;
    END
  END q[93]
  PIN q[94]
    DIRECTION OUTPUT ;
    USE SIGNAL ;
    PORT
      LAYER M4 ;
        RECT  11.688 18.432 11.88 18.456 ;
    END
  END q[94]
  PIN q[95]
    DIRECTION OUTPUT ;
    USE SIGNAL ;
    PORT
      LAYER M4 ;
        RECT  11.688 18.624 11.88 18.648 ;
    END
  END q[95]
  PIN q[96]
    DIRECTION OUTPUT ;
    USE SIGNAL ;
    PORT
      LAYER M4 ;
        RECT  11.688 18.816 11.88 18.84 ;
    END
  END q[96]
  PIN q[97]
    DIRECTION OUTPUT ;
    USE SIGNAL ;
    PORT
      LAYER M4 ;
        RECT  11.688 19.008 11.88 19.032 ;
    END
  END q[97]
  PIN q[98]
    DIRECTION OUTPUT ;
    USE SIGNAL ;
    PORT
      LAYER M4 ;
        RECT  11.688 19.2 11.88 19.224 ;
    END
  END q[98]
  PIN q[99]
    DIRECTION OUTPUT ;
    USE SIGNAL ;
    PORT
      LAYER M4 ;
        RECT  11.688 19.392 11.88 19.416 ;
    END
  END q[99]
  PIN q[9]
    DIRECTION OUTPUT ;
    USE SIGNAL ;
    PORT
      LAYER M4 ;
        RECT  11.688 2.112 11.88 2.136 ;
    END
  END q[9]
  PIN VDD
    DIRECTION INOUT ;
    USE POWER ;
    PORT
      LAYER M6 ;
        RECT  0.54 104.172 11.34 104.46 ;
        RECT  0.54 98.772 11.34 99.06 ;
        RECT  0.54 93.372 11.34 93.66 ;
        RECT  0.54 87.972 11.34 88.26 ;
        RECT  0.54 82.572 11.34 82.86 ;
        RECT  0.54 77.172 11.34 77.46 ;
        RECT  0.54 71.772 11.34 72.06 ;
        RECT  0.54 66.372 11.34 66.66 ;
        RECT  0.54 60.972 11.34 61.26 ;
        RECT  0.54 55.572 11.34 55.86 ;
        RECT  0.54 50.172 11.34 50.46 ;
        RECT  0.54 44.772 11.34 45.06 ;
        RECT  0.54 39.372 11.34 39.66 ;
        RECT  0.54 33.972 11.34 34.26 ;
        RECT  0.54 28.572 11.34 28.86 ;
        RECT  0.54 23.172 11.34 23.46 ;
        RECT  0.54 17.772 11.34 18.06 ;
        RECT  0.54 12.372 11.34 12.66 ;
        RECT  0.54 6.972 11.34 7.26 ;
        RECT  0.54 1.572 11.34 1.86 ;
    END
  END VDD
  PIN VSS
    DIRECTION INOUT ;
    USE GROUND ;
    PORT
      LAYER M6 ;
        RECT  0.54 103.596 11.34 103.884 ;
        RECT  0.54 98.196 11.34 98.484 ;
        RECT  0.54 92.796 11.34 93.084 ;
        RECT  0.54 87.396 11.34 87.684 ;
        RECT  0.54 81.996 11.34 82.284 ;
        RECT  0.54 76.596 11.34 76.884 ;
        RECT  0.54 71.196 11.34 71.484 ;
        RECT  0.54 65.796 11.34 66.084 ;
        RECT  0.54 60.396 11.34 60.684 ;
        RECT  0.54 54.996 11.34 55.284 ;
        RECT  0.54 49.596 11.34 49.884 ;
        RECT  0.54 44.196 11.34 44.484 ;
        RECT  0.54 38.796 11.34 39.084 ;
        RECT  0.54 33.396 11.34 33.684 ;
        RECT  0.54 27.996 11.34 28.284 ;
        RECT  0.54 22.596 11.34 22.884 ;
        RECT  0.54 17.196 11.34 17.484 ;
        RECT  0.54 11.796 11.34 12.084 ;
        RECT  0.54 6.396 11.34 6.684 ;
        RECT  0.54 0.996 11.34 1.284 ;
    END
  END VSS
  OBS
    LAYER RVTN ;
     RECT  0.54 0.54 11.34 0.675 ;
     RECT  0.54 0.945 11.34 1.215 ;
     RECT  0.54 1.485 11.34 1.755 ;
     RECT  0.54 2.025 11.34 2.295 ;
     RECT  0.54 2.565 11.34 2.835 ;
     RECT  0.54 3.105 11.34 3.375 ;
     RECT  0.54 3.645 11.34 3.915 ;
     RECT  0.54 4.185 11.34 4.455 ;
     RECT  0.54 4.725 11.34 4.995 ;
     RECT  0.54 5.265 11.34 5.535 ;
     RECT  0.54 5.805 11.34 6.075 ;
     RECT  0.54 6.345 11.34 6.615 ;
     RECT  0.54 6.885 11.34 7.155 ;
     RECT  0.54 7.425 11.34 7.695 ;
     RECT  0.54 7.965 11.34 8.235 ;
     RECT  0.54 8.505 11.34 8.775 ;
     RECT  0.54 9.045 11.34 9.315 ;
     RECT  0.54 9.585 11.34 9.855 ;
     RECT  0.54 10.125 11.34 10.395 ;
     RECT  0.54 10.665 11.34 10.935 ;
     RECT  0.54 11.205 11.34 11.475 ;
     RECT  0.54 11.745 11.34 12.015 ;
     RECT  0.54 12.285 11.34 12.555 ;
     RECT  0.54 12.825 11.34 13.095 ;
     RECT  0.54 13.365 11.34 13.635 ;
     RECT  0.54 13.905 11.34 14.175 ;
     RECT  0.54 14.445 11.34 14.715 ;
     RECT  0.54 14.985 11.34 15.255 ;
     RECT  0.54 15.525 11.34 15.795 ;
     RECT  0.54 16.065 11.34 16.335 ;
     RECT  0.54 16.605 11.34 16.875 ;
     RECT  0.54 17.145 11.34 17.415 ;
     RECT  0.54 17.685 11.34 17.955 ;
     RECT  0.54 18.225 11.34 18.495 ;
     RECT  0.54 18.765 11.34 19.035 ;
     RECT  0.54 19.305 11.34 19.575 ;
     RECT  0.54 19.845 11.34 20.115 ;
     RECT  0.54 20.385 11.34 20.655 ;
     RECT  0.54 20.925 11.34 21.195 ;
     RECT  0.54 21.465 11.34 21.735 ;
     RECT  0.54 22.005 11.34 22.275 ;
     RECT  0.54 22.545 11.34 22.815 ;
     RECT  0.54 23.085 11.34 23.355 ;
     RECT  0.54 23.625 11.34 23.895 ;
     RECT  0.54 24.165 11.34 24.435 ;
     RECT  0.54 24.705 11.34 24.975 ;
     RECT  0.54 25.245 11.34 25.515 ;
     RECT  0.54 25.785 11.34 26.055 ;
     RECT  0.54 26.325 11.34 26.595 ;
     RECT  0.54 26.865 11.34 27.135 ;
     RECT  0.54 27.405 11.34 27.675 ;
     RECT  0.54 27.945 11.34 28.215 ;
     RECT  0.54 28.485 11.34 28.755 ;
     RECT  0.54 29.025 11.34 29.295 ;
     RECT  0.54 29.565 11.34 29.835 ;
     RECT  0.54 30.105 11.34 30.375 ;
     RECT  0.54 30.645 11.34 30.915 ;
     RECT  0.54 31.185 11.34 31.455 ;
     RECT  0.54 31.725 11.34 31.995 ;
     RECT  0.54 32.265 11.34 32.535 ;
     RECT  0.54 32.805 11.34 33.075 ;
     RECT  0.54 33.345 11.34 33.615 ;
     RECT  0.54 33.885 11.34 34.155 ;
     RECT  0.54 34.425 11.34 34.695 ;
     RECT  0.54 34.965 11.34 35.235 ;
     RECT  0.54 35.505 11.34 35.775 ;
     RECT  0.54 36.045 11.34 36.315 ;
     RECT  0.54 36.585 11.34 36.855 ;
     RECT  0.54 37.125 11.34 37.395 ;
     RECT  0.54 37.665 11.34 37.935 ;
     RECT  0.54 38.205 11.34 38.475 ;
     RECT  0.54 38.745 11.34 39.015 ;
     RECT  0.54 39.285 11.34 39.555 ;
     RECT  0.54 39.825 11.34 40.095 ;
     RECT  0.54 40.365 11.34 40.635 ;
     RECT  0.54 40.905 11.34 41.175 ;
     RECT  0.54 41.445 11.34 41.715 ;
     RECT  0.54 41.985 11.34 42.255 ;
     RECT  0.54 42.525 11.34 42.795 ;
     RECT  0.54 43.065 11.34 43.335 ;
     RECT  0.54 43.605 11.34 43.875 ;
     RECT  0.54 44.145 11.34 44.415 ;
     RECT  0.54 44.685 11.34 44.955 ;
     RECT  0.54 45.225 11.34 45.495 ;
     RECT  0.54 45.765 11.34 46.035 ;
     RECT  0.54 46.305 11.34 46.575 ;
     RECT  0.54 46.845 11.34 47.115 ;
     RECT  0.54 47.385 11.34 47.655 ;
     RECT  0.54 47.925 11.34 48.195 ;
     RECT  0.54 48.465 11.34 48.735 ;
     RECT  0.54 49.005 11.34 49.275 ;
     RECT  0.54 49.545 11.34 49.815 ;
     RECT  0.54 50.085 11.34 50.355 ;
     RECT  0.54 50.625 11.34 50.895 ;
     RECT  0.54 51.165 11.34 51.435 ;
     RECT  0.54 51.705 11.34 51.975 ;
     RECT  0.54 52.245 11.34 52.515 ;
     RECT  0.54 52.785 11.34 53.055 ;
     RECT  0.54 53.325 11.34 53.595 ;
     RECT  0.54 53.865 11.34 54.135 ;
     RECT  0.54 54.405 11.34 54.675 ;
     RECT  0.54 54.945 11.34 55.215 ;
     RECT  0.54 55.485 11.34 55.755 ;
     RECT  0.54 56.025 11.34 56.295 ;
     RECT  0.54 56.565 11.34 56.835 ;
     RECT  0.54 57.105 11.34 57.375 ;
     RECT  0.54 57.645 11.34 57.915 ;
     RECT  0.54 58.185 11.34 58.455 ;
     RECT  0.54 58.725 11.34 58.995 ;
     RECT  0.54 59.265 11.34 59.535 ;
     RECT  0.54 59.805 11.34 60.075 ;
     RECT  0.54 60.345 11.34 60.615 ;
     RECT  0.54 60.885 11.34 61.155 ;
     RECT  0.54 61.425 11.34 61.695 ;
     RECT  0.54 61.965 11.34 62.235 ;
     RECT  0.54 62.505 11.34 62.775 ;
     RECT  0.54 63.045 11.34 63.315 ;
     RECT  0.54 63.585 11.34 63.855 ;
     RECT  0.54 64.125 11.34 64.395 ;
     RECT  0.54 64.665 11.34 64.935 ;
     RECT  0.54 65.205 11.34 65.475 ;
     RECT  0.54 65.745 11.34 66.015 ;
     RECT  0.54 66.285 11.34 66.555 ;
     RECT  0.54 66.825 11.34 67.095 ;
     RECT  0.54 67.365 11.34 67.635 ;
     RECT  0.54 67.905 11.34 68.175 ;
     RECT  0.54 68.445 11.34 68.715 ;
     RECT  0.54 68.985 11.34 69.255 ;
     RECT  0.54 69.525 11.34 69.795 ;
     RECT  0.54 70.065 11.34 70.335 ;
     RECT  0.54 70.605 11.34 70.875 ;
     RECT  0.54 71.145 11.34 71.415 ;
     RECT  0.54 71.685 11.34 71.955 ;
     RECT  0.54 72.225 11.34 72.495 ;
     RECT  0.54 72.765 11.34 73.035 ;
     RECT  0.54 73.305 11.34 73.575 ;
     RECT  0.54 73.845 11.34 74.115 ;
     RECT  0.54 74.385 11.34 74.655 ;
     RECT  0.54 74.925 11.34 75.195 ;
     RECT  0.54 75.465 11.34 75.735 ;
     RECT  0.54 76.005 11.34 76.275 ;
     RECT  0.54 76.545 11.34 76.815 ;
     RECT  0.54 77.085 11.34 77.355 ;
     RECT  0.54 77.625 11.34 77.895 ;
     RECT  0.54 78.165 11.34 78.435 ;
     RECT  0.54 78.705 11.34 78.975 ;
     RECT  0.54 79.245 11.34 79.515 ;
     RECT  0.54 79.785 11.34 80.055 ;
     RECT  0.54 80.325 11.34 80.595 ;
     RECT  0.54 80.865 11.34 81.135 ;
     RECT  0.54 81.405 11.34 81.675 ;
     RECT  0.54 81.945 11.34 82.215 ;
     RECT  0.54 82.485 11.34 82.755 ;
     RECT  0.54 83.025 11.34 83.295 ;
     RECT  0.54 83.565 11.34 83.835 ;
     RECT  0.54 84.105 11.34 84.375 ;
     RECT  0.54 84.645 11.34 84.915 ;
     RECT  0.54 85.185 11.34 85.455 ;
     RECT  0.54 85.725 11.34 85.995 ;
     RECT  0.54 86.265 11.34 86.535 ;
     RECT  0.54 86.805 11.34 87.075 ;
     RECT  0.54 87.345 11.34 87.615 ;
     RECT  0.54 87.885 11.34 88.155 ;
     RECT  0.54 88.425 11.34 88.695 ;
     RECT  0.54 88.965 11.34 89.235 ;
     RECT  0.54 89.505 11.34 89.775 ;
     RECT  0.54 90.045 11.34 90.315 ;
     RECT  0.54 90.585 11.34 90.855 ;
     RECT  0.54 91.125 11.34 91.395 ;
     RECT  0.54 91.665 11.34 91.935 ;
     RECT  0.54 92.205 11.34 92.475 ;
     RECT  0.54 92.745 11.34 93.015 ;
     RECT  0.54 93.285 11.34 93.555 ;
     RECT  0.54 93.825 11.34 94.095 ;
     RECT  0.54 94.365 11.34 94.635 ;
     RECT  0.54 94.905 11.34 95.175 ;
     RECT  0.54 95.445 11.34 95.715 ;
     RECT  0.54 95.985 11.34 96.255 ;
     RECT  0.54 96.525 11.34 96.795 ;
     RECT  0.54 97.065 11.34 97.335 ;
     RECT  0.54 97.605 11.34 97.875 ;
     RECT  0.54 98.145 11.34 98.415 ;
     RECT  0.54 98.685 11.34 98.955 ;
     RECT  0.54 99.225 11.34 99.495 ;
     RECT  0.54 99.765 11.34 100.035 ;
     RECT  0.54 100.305 11.34 100.575 ;
     RECT  0.54 100.845 11.34 101.115 ;
     RECT  0.54 101.385 11.34 101.655 ;
     RECT  0.54 101.925 11.34 102.195 ;
     RECT  0.54 102.465 11.34 102.735 ;
     RECT  0.54 103.005 11.34 103.275 ;
     RECT  0.54 103.545 11.34 103.815 ;
     RECT  0.54 104.085 11.34 104.355 ;
     RECT  0.54 104.625 11.34 104.895 ;
     RECT  0.54 105.165 11.34 105.3 ;
    LAYER RVTP ;
     RECT  0.54 0.675 11.34 0.945 ;
     RECT  0.54 1.215 11.34 1.485 ;
     RECT  0.54 1.755 11.34 2.025 ;
     RECT  0.54 2.295 11.34 2.565 ;
     RECT  0.54 2.835 11.34 3.105 ;
     RECT  0.54 3.375 11.34 3.645 ;
     RECT  0.54 3.915 11.34 4.185 ;
     RECT  0.54 4.455 11.34 4.725 ;
     RECT  0.54 4.995 11.34 5.265 ;
     RECT  0.54 5.535 11.34 5.805 ;
     RECT  0.54 6.075 11.34 6.345 ;
     RECT  0.54 6.615 11.34 6.885 ;
     RECT  0.54 7.155 11.34 7.425 ;
     RECT  0.54 7.695 11.34 7.965 ;
     RECT  0.54 8.235 11.34 8.505 ;
     RECT  0.54 8.775 11.34 9.045 ;
     RECT  0.54 9.315 11.34 9.585 ;
     RECT  0.54 9.855 11.34 10.125 ;
     RECT  0.54 10.395 11.34 10.665 ;
     RECT  0.54 10.935 11.34 11.205 ;
     RECT  0.54 11.475 11.34 11.745 ;
     RECT  0.54 12.015 11.34 12.285 ;
     RECT  0.54 12.555 11.34 12.825 ;
     RECT  0.54 13.095 11.34 13.365 ;
     RECT  0.54 13.635 11.34 13.905 ;
     RECT  0.54 14.175 11.34 14.445 ;
     RECT  0.54 14.715 11.34 14.985 ;
     RECT  0.54 15.255 11.34 15.525 ;
     RECT  0.54 15.795 11.34 16.065 ;
     RECT  0.54 16.335 11.34 16.605 ;
     RECT  0.54 16.875 11.34 17.145 ;
     RECT  0.54 17.415 11.34 17.685 ;
     RECT  0.54 17.955 11.34 18.225 ;
     RECT  0.54 18.495 11.34 18.765 ;
     RECT  0.54 19.035 11.34 19.305 ;
     RECT  0.54 19.575 11.34 19.845 ;
     RECT  0.54 20.115 11.34 20.385 ;
     RECT  0.54 20.655 11.34 20.925 ;
     RECT  0.54 21.195 11.34 21.465 ;
     RECT  0.54 21.735 11.34 22.005 ;
     RECT  0.54 22.275 11.34 22.545 ;
     RECT  0.54 22.815 11.34 23.085 ;
     RECT  0.54 23.355 11.34 23.625 ;
     RECT  0.54 23.895 11.34 24.165 ;
     RECT  0.54 24.435 11.34 24.705 ;
     RECT  0.54 24.975 11.34 25.245 ;
     RECT  0.54 25.515 11.34 25.785 ;
     RECT  0.54 26.055 11.34 26.325 ;
     RECT  0.54 26.595 11.34 26.865 ;
     RECT  0.54 27.135 11.34 27.405 ;
     RECT  0.54 27.675 11.34 27.945 ;
     RECT  0.54 28.215 11.34 28.485 ;
     RECT  0.54 28.755 11.34 29.025 ;
     RECT  0.54 29.295 11.34 29.565 ;
     RECT  0.54 29.835 11.34 30.105 ;
     RECT  0.54 30.375 11.34 30.645 ;
     RECT  0.54 30.915 11.34 31.185 ;
     RECT  0.54 31.455 11.34 31.725 ;
     RECT  0.54 31.995 11.34 32.265 ;
     RECT  0.54 32.535 11.34 32.805 ;
     RECT  0.54 33.075 11.34 33.345 ;
     RECT  0.54 33.615 11.34 33.885 ;
     RECT  0.54 34.155 11.34 34.425 ;
     RECT  0.54 34.695 11.34 34.965 ;
     RECT  0.54 35.235 11.34 35.505 ;
     RECT  0.54 35.775 11.34 36.045 ;
     RECT  0.54 36.315 11.34 36.585 ;
     RECT  0.54 36.855 11.34 37.125 ;
     RECT  0.54 37.395 11.34 37.665 ;
     RECT  0.54 37.935 11.34 38.205 ;
     RECT  0.54 38.475 11.34 38.745 ;
     RECT  0.54 39.015 11.34 39.285 ;
     RECT  0.54 39.555 11.34 39.825 ;
     RECT  0.54 40.095 11.34 40.365 ;
     RECT  0.54 40.635 11.34 40.905 ;
     RECT  0.54 41.175 11.34 41.445 ;
     RECT  0.54 41.715 11.34 41.985 ;
     RECT  0.54 42.255 11.34 42.525 ;
     RECT  0.54 42.795 11.34 43.065 ;
     RECT  0.54 43.335 11.34 43.605 ;
     RECT  0.54 43.875 11.34 44.145 ;
     RECT  0.54 44.415 11.34 44.685 ;
     RECT  0.54 44.955 11.34 45.225 ;
     RECT  0.54 45.495 11.34 45.765 ;
     RECT  0.54 46.035 11.34 46.305 ;
     RECT  0.54 46.575 11.34 46.845 ;
     RECT  0.54 47.115 11.34 47.385 ;
     RECT  0.54 47.655 11.34 47.925 ;
     RECT  0.54 48.195 11.34 48.465 ;
     RECT  0.54 48.735 11.34 49.005 ;
     RECT  0.54 49.275 11.34 49.545 ;
     RECT  0.54 49.815 11.34 50.085 ;
     RECT  0.54 50.355 11.34 50.625 ;
     RECT  0.54 50.895 11.34 51.165 ;
     RECT  0.54 51.435 11.34 51.705 ;
     RECT  0.54 51.975 11.34 52.245 ;
     RECT  0.54 52.515 11.34 52.785 ;
     RECT  0.54 53.055 11.34 53.325 ;
     RECT  0.54 53.595 11.34 53.865 ;
     RECT  0.54 54.135 11.34 54.405 ;
     RECT  0.54 54.675 11.34 54.945 ;
     RECT  0.54 55.215 11.34 55.485 ;
     RECT  0.54 55.755 11.34 56.025 ;
     RECT  0.54 56.295 11.34 56.565 ;
     RECT  0.54 56.835 11.34 57.105 ;
     RECT  0.54 57.375 11.34 57.645 ;
     RECT  0.54 57.915 11.34 58.185 ;
     RECT  0.54 58.455 11.34 58.725 ;
     RECT  0.54 58.995 11.34 59.265 ;
     RECT  0.54 59.535 11.34 59.805 ;
     RECT  0.54 60.075 11.34 60.345 ;
     RECT  0.54 60.615 11.34 60.885 ;
     RECT  0.54 61.155 11.34 61.425 ;
     RECT  0.54 61.695 11.34 61.965 ;
     RECT  0.54 62.235 11.34 62.505 ;
     RECT  0.54 62.775 11.34 63.045 ;
     RECT  0.54 63.315 11.34 63.585 ;
     RECT  0.54 63.855 11.34 64.125 ;
     RECT  0.54 64.395 11.34 64.665 ;
     RECT  0.54 64.935 11.34 65.205 ;
     RECT  0.54 65.475 11.34 65.745 ;
     RECT  0.54 66.015 11.34 66.285 ;
     RECT  0.54 66.555 11.34 66.825 ;
     RECT  0.54 67.095 11.34 67.365 ;
     RECT  0.54 67.635 11.34 67.905 ;
     RECT  0.54 68.175 11.34 68.445 ;
     RECT  0.54 68.715 11.34 68.985 ;
     RECT  0.54 69.255 11.34 69.525 ;
     RECT  0.54 69.795 11.34 70.065 ;
     RECT  0.54 70.335 11.34 70.605 ;
     RECT  0.54 70.875 11.34 71.145 ;
     RECT  0.54 71.415 11.34 71.685 ;
     RECT  0.54 71.955 11.34 72.225 ;
     RECT  0.54 72.495 11.34 72.765 ;
     RECT  0.54 73.035 11.34 73.305 ;
     RECT  0.54 73.575 11.34 73.845 ;
     RECT  0.54 74.115 11.34 74.385 ;
     RECT  0.54 74.655 11.34 74.925 ;
     RECT  0.54 75.195 11.34 75.465 ;
     RECT  0.54 75.735 11.34 76.005 ;
     RECT  0.54 76.275 11.34 76.545 ;
     RECT  0.54 76.815 11.34 77.085 ;
     RECT  0.54 77.355 11.34 77.625 ;
     RECT  0.54 77.895 11.34 78.165 ;
     RECT  0.54 78.435 11.34 78.705 ;
     RECT  0.54 78.975 11.34 79.245 ;
     RECT  0.54 79.515 11.34 79.785 ;
     RECT  0.54 80.055 11.34 80.325 ;
     RECT  0.54 80.595 11.34 80.865 ;
     RECT  0.54 81.135 11.34 81.405 ;
     RECT  0.54 81.675 11.34 81.945 ;
     RECT  0.54 82.215 11.34 82.485 ;
     RECT  0.54 82.755 11.34 83.025 ;
     RECT  0.54 83.295 11.34 83.565 ;
     RECT  0.54 83.835 11.34 84.105 ;
     RECT  0.54 84.375 11.34 84.645 ;
     RECT  0.54 84.915 11.34 85.185 ;
     RECT  0.54 85.455 11.34 85.725 ;
     RECT  0.54 85.995 11.34 86.265 ;
     RECT  0.54 86.535 11.34 86.805 ;
     RECT  0.54 87.075 11.34 87.345 ;
     RECT  0.54 87.615 11.34 87.885 ;
     RECT  0.54 88.155 11.34 88.425 ;
     RECT  0.54 88.695 11.34 88.965 ;
     RECT  0.54 89.235 11.34 89.505 ;
     RECT  0.54 89.775 11.34 90.045 ;
     RECT  0.54 90.315 11.34 90.585 ;
     RECT  0.54 90.855 11.34 91.125 ;
     RECT  0.54 91.395 11.34 91.665 ;
     RECT  0.54 91.935 11.34 92.205 ;
     RECT  0.54 92.475 11.34 92.745 ;
     RECT  0.54 93.015 11.34 93.285 ;
     RECT  0.54 93.555 11.34 93.825 ;
     RECT  0.54 94.095 11.34 94.365 ;
     RECT  0.54 94.635 11.34 94.905 ;
     RECT  0.54 95.175 11.34 95.445 ;
     RECT  0.54 95.715 11.34 95.985 ;
     RECT  0.54 96.255 11.34 96.525 ;
     RECT  0.54 96.795 11.34 97.065 ;
     RECT  0.54 97.335 11.34 97.605 ;
     RECT  0.54 97.875 11.34 98.145 ;
     RECT  0.54 98.415 11.34 98.685 ;
     RECT  0.54 98.955 11.34 99.225 ;
     RECT  0.54 99.495 11.34 99.765 ;
     RECT  0.54 100.035 11.34 100.305 ;
     RECT  0.54 100.575 11.34 100.845 ;
     RECT  0.54 101.115 11.34 101.385 ;
     RECT  0.54 101.655 11.34 101.925 ;
     RECT  0.54 102.195 11.34 102.465 ;
     RECT  0.54 102.735 11.34 103.005 ;
     RECT  0.54 103.275 11.34 103.545 ;
     RECT  0.54 103.815 11.34 104.085 ;
     RECT  0.54 104.355 11.34 104.625 ;
     RECT  0.54 104.895 11.34 105.165 ;
    LAYER M1 ;
     RECT  0.54 0.531 11.34 105.309 ;
    LAYER M2 ;
     RECT  0.211 1.422 0.247 3.6 ;
     RECT  0.211 4.932 0.247 5.49 ;
     RECT  0.211 8.982 0.247 9.27 ;
     RECT  0.211 10.062 0.247 11.16 ;
     RECT  0.211 11.952 0.247 11.97 ;
     RECT  0.211 15.732 0.247 16.56 ;
     RECT  0.211 17.352 0.247 20.07 ;
     RECT  0.211 23.166 0.247 24.12 ;
     RECT  0.211 25.452 0.247 25.47 ;
     RECT  0.211 26.802 0.247 28.44 ;
     RECT  0.211 29.502 0.247 30.33 ;
     RECT  0.211 31.122 0.247 40.32 ;
     RECT  0.211 42.192 0.247 42.21 ;
     RECT  0.211 43.812 0.247 45.018 ;
     RECT  0.211 45.972 0.247 46.26 ;
     RECT  0.211 47.052 0.247 47.07 ;
     RECT  0.211 48.672 0.247 48.96 ;
     RECT  0.211 49.752 0.247 50.04 ;
     RECT  0.211 50.832 0.247 52.74 ;
     RECT  0.211 53.64 0.247 54.09 ;
     RECT  0.211 54.882 0.247 57.87 ;
     RECT  0.211 58.662 0.247 58.95 ;
     RECT  0.211 60.012 0.247 60.03 ;
     RECT  0.211 60.822 0.247 60.84 ;
     RECT  0.211 61.632 0.247 62.19 ;
     RECT  0.211 63.09 0.247 65.7 ;
     RECT  0.211 66.492 0.247 66.78 ;
     RECT  0.211 67.572 0.247 68.13 ;
     RECT  0.211 69.192 0.247 70.398 ;
     RECT  0.211 71.352 0.247 75.42 ;
     RECT  0.211 76.212 0.247 81.9 ;
     RECT  0.211 82.692 0.247 83.52 ;
     RECT  0.211 88.362 0.247 88.758 ;
     RECT  0.211 94.302 0.247 94.32 ;
     RECT  0.211 95.382 0.247 96.75 ;
     RECT  0.211 97.542 0.247 98.1 ;
     RECT  0.247 43.812 0.283 46.26 ;
     RECT  0.247 58.662 0.283 59.22 ;
     RECT  0.247 60.012 0.283 60.84 ;
     RECT  0.247 69.192 0.283 83.52 ;
     RECT  0.211 84.852 0.283 87.57 ;
     RECT  0.247 88.362 0.283 89.298 ;
     RECT  0.211 90.252 0.283 90.27 ;
     RECT  0.211 91.062 0.283 91.08 ;
     RECT  0.211 92.142 0.283 92.268 ;
     RECT  0.211 93.06 0.283 93.51 ;
     RECT  0.247 94.302 0.283 96.75 ;
     RECT  0.247 15.462 0.355 16.56 ;
     RECT  0.247 17.352 0.355 20.34 ;
     RECT  0.211 21.132 0.355 21.69 ;
     RECT  0.247 22.752 0.355 28.44 ;
     RECT  0.247 41.994 0.355 42.282 ;
     RECT  0.247 48.672 0.355 52.74 ;
     RECT  0.247 53.64 0.355 57.87 ;
     RECT  0.283 58.662 0.355 60.84 ;
     RECT  0.247 97.542 0.355 98.748 ;
     RECT  0.211 99.702 0.355 100.53 ;
     RECT  0.247 8.982 0.463 11.16 ;
     RECT  0.247 11.952 0.463 12.24 ;
     RECT  0.247 29.502 0.463 40.32 ;
     RECT  0.211 41.112 0.463 41.13 ;
     RECT  0.355 41.994 0.463 42.858 ;
     RECT  0.283 43.614 0.463 46.26 ;
     RECT  0.247 47.052 0.463 47.718 ;
     RECT  0.355 48.672 0.463 60.84 ;
     RECT  0.247 61.632 0.463 68.13 ;
     RECT  0.283 92.142 0.463 96.75 ;
     RECT  0.355 97.542 0.463 100.53 ;
     RECT  0.211 101.322 0.463 102.69 ;
     RECT  0.211 103.752 0.463 104.724 ;
     RECT  0.355 15.462 0.499 20.34 ;
     RECT  0.355 21.132 0.499 28.44 ;
     RECT  0.247 0.954 0.535 5.49 ;
     RECT  0.211 6.282 0.535 8.19 ;
     RECT  0.211 13.032 0.535 14.67 ;
     RECT  0.499 15.462 0.535 28.44 ;
     RECT  0.283 69.192 0.535 83.592 ;
     RECT  0.283 84.69 0.535 87.57 ;
     RECT  0.283 88.362 0.535 91.08 ;
     RECT  0.463 91.944 0.535 96.75 ;
     RECT  0.463 97.542 0.535 105.192 ;
     RECT  0.535 0.954 0.54 8.19 ;
     RECT  0.463 8.982 0.54 12.24 ;
     RECT  0.535 13.032 0.54 28.44 ;
     RECT  0.463 29.304 0.54 47.718 ;
     RECT  0.463 48.672 0.54 68.13 ;
     RECT  0.535 69.192 0.54 83.664 ;
     RECT  0.535 84.69 0.54 91.08 ;
     RECT  0.535 91.944 0.54 105.192 ;
     RECT  0.54 0.531 11.34 105.309 ;
     RECT  11.34 19.206 11.687 19.224 ;
     RECT  11.34 30.816 11.687 30.834 ;
     RECT  11.34 2.07 11.759 2.088 ;
     RECT  11.34 8.046 11.759 8.064 ;
     RECT  11.34 9.828 11.759 9.846 ;
     RECT  11.34 86.742 11.759 86.76 ;
    LAYER M3 ;
     RECT  1.224 0.379 1.242 0.523 ;
     RECT  0.795 0.523 1.242 0.571 ;
     RECT  4.572 0.571 4.59 0.607 ;
     RECT  0.216 0.571 1.314 0.643 ;
     RECT  2.376 0.607 2.466 0.643 ;
     RECT  3.672 0.607 3.69 0.679 ;
     RECT  4.536 0.607 4.59 0.679 ;
     RECT  0.216 0.643 2.646 0.715 ;
     RECT  3.672 0.679 4.59 0.715 ;
     RECT  6.195 0.523 6.285 0.751 ;
     RECT  10.836 0.379 10.854 0.763 ;
     RECT  5.616 0.751 6.285 0.793 ;
     RECT  10.368 0.763 10.854 0.955 ;
     RECT  8.496 0.571 8.514 0.985 ;
     RECT  0.216 0.715 4.698 1.021 ;
     RECT  5.616 0.793 6.477 1.021 ;
     RECT  8.496 0.985 9.162 1.021 ;
     RECT  8.496 1.021 9.522 1.049 ;
     RECT  8.712 1.049 9.522 1.139 ;
     RECT  0.216 1.021 6.477 1.147 ;
     RECT  7.416 0.751 7.434 1.147 ;
     RECT  0.216 1.147 7.434 1.219 ;
     RECT  10.368 0.955 11.034 1.291 ;
     RECT  10.26 1.291 11.034 1.373 ;
     RECT  10.476 1.373 11.034 1.409 ;
     RECT  9.144 1.139 9.486 1.709 ;
     RECT  9.468 1.709 9.486 1.985 ;
     RECT  10.476 1.409 10.854 2.057 ;
     RECT  0.216 1.219 7.902 2.065 ;
     RECT  11.664 2.059 11.754 2.093 ;
     RECT  11.664 2.093 11.682 2.141 ;
     RECT  10.476 2.057 10.818 2.371 ;
     RECT  10.26 2.371 10.818 2.525 ;
     RECT  0.216 2.065 7.938 2.641 ;
     RECT  0.216 2.641 8.082 2.731 ;
     RECT  10.656 2.525 10.818 2.759 ;
     RECT  0.216 2.731 8.478 2.765 ;
     RECT  8.244 2.765 8.478 2.803 ;
     RECT  8.244 2.803 8.622 2.861 ;
     RECT  0.216 2.765 7.362 3.029 ;
     RECT  0.216 3.029 7.182 3.065 ;
     RECT  0.216 3.065 6.894 3.293 ;
     RECT  10.836 2.875 10.854 3.643 ;
     RECT  10.836 3.643 10.926 3.811 ;
     RECT  10.8 3.811 10.926 3.869 ;
     RECT  0.216 3.293 6.858 3.875 ;
     RECT  8.244 2.861 8.298 3.931 ;
     RECT  9.468 3.883 9.486 3.955 ;
     RECT  10.836 3.869 10.926 3.991 ;
     RECT  10.836 3.991 10.998 4.027 ;
     RECT  9.324 3.955 9.486 4.219 ;
     RECT  9.324 4.219 9.882 4.261 ;
     RECT  7.884 3.931 8.298 4.507 ;
     RECT  7.884 4.507 8.334 4.649 ;
     RECT  10.836 4.027 11.214 4.649 ;
     RECT  9.324 4.261 10.026 4.765 ;
     RECT  10.836 4.649 11.034 4.765 ;
     RECT  7.884 4.649 8.262 4.801 ;
     RECT  9.324 4.765 11.034 4.801 ;
     RECT  9.288 4.801 11.034 4.919 ;
     RECT  9.288 4.919 10.89 5.027 ;
     RECT  9.468 5.027 10.89 5.117 ;
     RECT  7.56 4.801 8.262 5.179 ;
     RECT  7.488 5.179 8.262 5.297 ;
     RECT  8.028 5.297 8.262 5.369 ;
     RECT  10.188 5.117 10.89 5.405 ;
     RECT  8.604 5.467 8.622 5.501 ;
     RECT  10.188 5.405 10.854 5.639 ;
     RECT  7.236 5.707 7.254 5.999 ;
     RECT  0.216 3.875 6.477 6.043 ;
     RECT  10.224 5.639 10.854 6.365 ;
     RECT  10.8 6.365 10.854 6.557 ;
     RECT  10.8 6.557 10.818 7.099 ;
     RECT  0.216 6.043 6.858 7.231 ;
     RECT  10.764 7.099 10.818 7.291 ;
     RECT  10.656 7.291 10.818 7.321 ;
     RECT  9.036 7.321 9.054 7.339 ;
     RECT  0.216 7.231 7.002 7.387 ;
     RECT  10.584 7.321 10.926 7.393 ;
     RECT  8.892 7.339 9.054 7.421 ;
     RECT  10.116 7.393 10.926 7.517 ;
     RECT  8.892 7.421 8.91 7.579 ;
     RECT  10.116 7.517 10.278 7.619 ;
     RECT  8.316 7.579 8.91 7.663 ;
     RECT  0.216 7.387 7.362 7.861 ;
     RECT  8.172 7.663 8.91 7.889 ;
     RECT  10.26 7.619 10.278 7.889 ;
     RECT  0.216 7.861 7.434 7.961 ;
     RECT  11.736 8.011 11.754 8.041 ;
     RECT  11.664 8.041 11.754 8.069 ;
     RECT  11.664 8.069 11.682 8.093 ;
     RECT  7.416 7.961 7.434 8.311 ;
     RECT  8.892 7.889 8.91 8.311 ;
     RECT  10.8 8.251 10.818 8.339 ;
     RECT  8.892 8.311 9.234 8.573 ;
     RECT  7.416 8.311 8.118 8.609 ;
     RECT  9.36 8.635 9.666 8.699 ;
     RECT  7.308 8.731 7.326 8.771 ;
     RECT  8.1 8.609 8.118 9.121 ;
     RECT  0.216 7.961 6.477 9.211 ;
     RECT  10.836 8.437 10.854 9.211 ;
     RECT  10.836 9.211 10.926 9.245 ;
     RECT  0.216 9.211 6.606 9.589 ;
     RECT  10.836 9.245 10.854 9.589 ;
     RECT  10.656 9.589 10.854 9.629 ;
     RECT  8.1 9.121 8.262 9.643 ;
     RECT  9.36 8.699 9.558 9.677 ;
     RECT  9.36 9.677 9.378 9.779 ;
     RECT  0.216 9.589 7.002 9.787 ;
     RECT  7.884 9.643 8.262 9.787 ;
     RECT  0.216 9.787 8.406 9.821 ;
     RECT  11.664 9.787 11.682 9.823 ;
     RECT  11.664 9.823 11.754 9.851 ;
     RECT  11.736 9.851 11.754 9.869 ;
     RECT  0.216 9.821 7.794 10.049 ;
     RECT  10.8 9.629 10.854 10.049 ;
     RECT  9.072 9.835 9.126 10.109 ;
     RECT  9.072 10.109 9.09 10.121 ;
     RECT  7.416 10.049 7.794 10.555 ;
     RECT  7.416 10.555 8.586 10.589 ;
     RECT  10.836 10.049 10.854 10.589 ;
     RECT  10.908 10.741 10.926 10.781 ;
     RECT  0.216 10.049 6.606 10.795 ;
     RECT  7.416 10.589 7.722 10.795 ;
     RECT  8.568 10.589 8.586 10.829 ;
     RECT  9.576 10.939 9.594 11.101 ;
     RECT  0.216 10.795 7.722 11.165 ;
     RECT  0.216 11.165 6.498 11.357 ;
     RECT  7.524 11.165 7.722 11.371 ;
     RECT  9.576 11.101 9.666 11.371 ;
     RECT  9.576 11.371 9.702 11.405 ;
     RECT  0.216 11.357 5.382 11.435 ;
     RECT  10.836 11.407 10.854 11.551 ;
     RECT  10.548 11.551 10.854 11.641 ;
     RECT  7.524 11.371 8.19 11.659 ;
     RECT  9.468 11.407 9.558 11.659 ;
     RECT  10.548 11.641 10.926 11.669 ;
     RECT  7.524 11.659 9.558 11.741 ;
     RECT  8.46 11.741 9.558 11.813 ;
     RECT  10.908 11.669 10.926 11.821 ;
     RECT  10.908 11.821 11.214 11.933 ;
     RECT  7.524 11.741 7.542 11.939 ;
     RECT  6.195 11.357 6.498 11.947 ;
     RECT  0.216 11.435 5.238 12.217 ;
     RECT  0.216 12.217 5.346 12.361 ;
     RECT  10.908 11.933 11.106 12.451 ;
     RECT  8.46 11.813 8.73 12.509 ;
     RECT  0.216 12.361 5.418 12.523 ;
     RECT  6.195 11.947 7.254 12.523 ;
     RECT  10.836 12.451 11.106 12.631 ;
     RECT  10.728 12.631 11.106 12.667 ;
     RECT  0.216 12.523 7.254 12.749 ;
     RECT  10.728 12.667 11.214 12.749 ;
     RECT  10.728 12.749 10.998 12.797 ;
     RECT  10.728 12.797 10.926 12.929 ;
     RECT  0.216 12.749 7.218 13.037 ;
     RECT  8.46 12.509 8.622 13.037 ;
     RECT  8.46 13.037 8.478 13.085 ;
     RECT  0.216 13.037 7.002 13.091 ;
     RECT  10.728 12.929 10.89 13.441 ;
     RECT  10.188 13.441 10.89 13.867 ;
     RECT  0.216 13.091 6.858 13.981 ;
     RECT  9.9 13.867 10.89 13.981 ;
     RECT  9.792 13.981 10.89 14.011 ;
     RECT  9.792 14.011 10.926 14.099 ;
     RECT  0.216 13.981 7.29 14.203 ;
     RECT  0.216 14.203 7.722 14.251 ;
     RECT  0.216 14.251 7.938 14.441 ;
     RECT  7.488 14.441 7.938 14.443 ;
     RECT  7.488 14.443 8.37 14.549 ;
     RECT  7.488 14.549 7.83 14.639 ;
     RECT  0.216 14.441 6.534 14.675 ;
     RECT  7.488 14.639 7.506 14.675 ;
     RECT  10.224 14.099 10.854 14.917 ;
     RECT  9.9 14.917 10.854 15.151 ;
     RECT  9.648 15.151 10.854 15.259 ;
     RECT  9.576 15.259 10.854 15.389 ;
     RECT  0.252 14.675 6.534 15.601 ;
     RECT  7.38 15.163 7.47 15.601 ;
     RECT  10.836 15.389 10.854 15.601 ;
     RECT  0.252 15.601 7.47 15.629 ;
     RECT  6.156 15.629 7.47 15.719 ;
     RECT  0.252 15.629 5.382 15.727 ;
     RECT  6.156 15.719 6.642 15.773 ;
     RECT  10.836 15.601 10.89 15.965 ;
     RECT  9.576 15.389 9.594 16.123 ;
     RECT  9.576 16.123 9.666 16.169 ;
     RECT  6.195 15.773 6.642 16.459 ;
     RECT  7.74 16.231 7.758 16.459 ;
     RECT  9.216 16.375 9.234 16.459 ;
     RECT  0.216 15.727 5.382 16.501 ;
     RECT  6.195 16.459 7.758 16.501 ;
     RECT  9 16.459 9.234 16.501 ;
     RECT  8.856 16.501 9.234 16.541 ;
     RECT  0.216 16.501 7.758 16.589 ;
     RECT  10.908 16.231 11.142 16.699 ;
     RECT  10.764 16.699 11.142 16.799 ;
     RECT  6.195 16.589 7.758 16.807 ;
     RECT  10.8 16.799 11.142 16.891 ;
     RECT  6.195 16.807 8.082 16.915 ;
     RECT  9.144 16.541 9.234 17.041 ;
     RECT  9.144 17.041 9.378 17.069 ;
     RECT  10.8 16.891 11.214 17.069 ;
     RECT  9.216 17.069 9.378 17.117 ;
     RECT  10.8 17.069 11.142 17.117 ;
     RECT  0.216 16.589 5.454 17.311 ;
     RECT  6.195 16.915 8.154 17.311 ;
     RECT  9.216 17.117 9.234 17.375 ;
     RECT  10.8 17.117 10.854 17.887 ;
     RECT  9.144 17.959 9.162 18.031 ;
     RECT  10.116 17.887 10.854 18.043 ;
     RECT  0.216 17.311 8.154 18.059 ;
     RECT  8.136 18.059 8.154 18.121 ;
     RECT  9.072 18.031 9.162 18.149 ;
     RECT  10.116 18.043 10.926 18.149 ;
     RECT  8.136 18.121 8.298 18.173 ;
     RECT  8.136 18.173 8.154 18.185 ;
     RECT  0.216 18.059 7.29 18.221 ;
     RECT  9.144 18.149 9.162 18.221 ;
     RECT  6.12 18.221 6.786 18.419 ;
     RECT  6.12 18.419 6.57 18.455 ;
     RECT  10.116 18.149 10.35 18.523 ;
     RECT  9.576 18.523 10.35 18.931 ;
     RECT  0.216 18.221 5.31 19.039 ;
     RECT  6.12 18.455 6.477 19.039 ;
     RECT  9.576 18.931 10.386 19.111 ;
     RECT  9.576 19.111 10.854 19.201 ;
     RECT  11.664 18.619 11.682 19.229 ;
     RECT  9.504 19.201 10.854 19.337 ;
     RECT  0.216 19.039 6.477 19.499 ;
     RECT  0.216 19.499 5.454 19.535 ;
     RECT  10.224 19.337 10.854 20.111 ;
     RECT  10.224 20.111 10.602 20.191 ;
     RECT  8.388 20.191 8.406 20.251 ;
     RECT  8.388 20.251 8.766 20.281 ;
     RECT  8.028 20.281 8.766 20.309 ;
     RECT  8.028 20.309 8.046 20.333 ;
     RECT  9.684 20.191 10.602 20.453 ;
     RECT  8.892 20.461 8.91 20.525 ;
     RECT  0.216 19.535 5.202 20.551 ;
     RECT  9.684 20.453 9.702 20.573 ;
     RECT  7.344 20.491 7.362 20.579 ;
     RECT  6.195 19.499 6.477 20.587 ;
     RECT  6.195 20.587 7.182 20.621 ;
     RECT  0.216 20.551 5.418 20.965 ;
     RECT  6.195 20.621 6.966 20.965 ;
     RECT  10.836 20.923 10.854 21.115 ;
     RECT  10.836 21.115 10.998 21.271 ;
     RECT  9.324 20.731 9.486 21.299 ;
     RECT  10.764 21.271 10.998 21.307 ;
     RECT  7.992 21.271 8.01 21.355 ;
     RECT  9.468 21.299 9.486 21.389 ;
     RECT  10.368 21.307 10.998 21.389 ;
     RECT  7.992 21.355 8.694 21.397 ;
     RECT  0.216 20.965 6.966 21.499 ;
     RECT  7.812 21.397 8.694 21.499 ;
     RECT  9.648 21.433 9.738 21.533 ;
     RECT  0.216 21.499 8.694 21.677 ;
     RECT  10.692 21.389 10.998 21.725 ;
     RECT  9.648 21.533 9.666 22.109 ;
     RECT  10.764 21.725 10.998 22.301 ;
     RECT  0.216 21.677 8.442 22.621 ;
     RECT  0.216 22.621 8.586 22.781 ;
     RECT  10.764 22.301 10.854 22.783 ;
     RECT  10.26 22.783 10.854 22.877 ;
     RECT  9.36 23.035 9.378 23.081 ;
     RECT  0.216 22.781 8.298 23.279 ;
     RECT  0.216 23.279 6.894 23.315 ;
     RECT  8.136 23.279 8.154 23.357 ;
     RECT  0.216 23.315 6.858 23.549 ;
     RECT  6.195 23.549 6.858 23.585 ;
     RECT  10.548 22.877 10.854 23.611 ;
     RECT  10.116 23.611 10.854 23.657 ;
     RECT  10.26 23.657 10.854 23.791 ;
     RECT  10.26 23.791 10.89 24.269 ;
     RECT  10.836 24.269 10.89 24.571 ;
     RECT  9.36 24.511 9.378 24.629 ;
     RECT  10.836 24.571 10.926 24.629 ;
     RECT  0.216 23.549 5.454 24.709 ;
     RECT  6.195 23.585 6.477 24.709 ;
     RECT  0.216 24.709 6.477 24.715 ;
     RECT  7.524 24.619 7.542 24.715 ;
     RECT  0.216 24.715 7.542 24.749 ;
     RECT  5.904 24.749 7.542 24.781 ;
     RECT  9.468 24.745 9.486 24.781 ;
     RECT  9.468 24.781 9.666 24.845 ;
     RECT  9.648 24.845 9.666 24.899 ;
     RECT  5.904 24.781 8.586 24.935 ;
     RECT  6.12 24.935 8.586 24.941 ;
     RECT  6.195 24.941 8.586 24.971 ;
     RECT  8.568 24.971 8.586 25.079 ;
     RECT  10.836 24.629 10.854 25.141 ;
     RECT  6.195 24.971 7.326 25.169 ;
     RECT  6.195 25.169 7.11 25.205 ;
     RECT  10.8 25.141 10.854 25.313 ;
     RECT  8.712 25.483 8.73 25.517 ;
     RECT  9.9 25.531 9.918 25.619 ;
     RECT  9.648 25.681 9.666 25.757 ;
     RECT  7.884 25.861 7.902 26.087 ;
     RECT  10.836 25.313 10.854 26.107 ;
     RECT  0.216 24.749 5.13 26.131 ;
     RECT  9.468 26.221 9.486 26.321 ;
     RECT  6.195 25.205 6.93 26.401 ;
     RECT  10.8 26.107 10.854 26.401 ;
     RECT  6.012 26.401 7.326 26.519 ;
     RECT  8.28 26.365 8.298 26.527 ;
     RECT  8.28 26.527 8.37 26.635 ;
     RECT  0.216 26.131 5.166 26.671 ;
     RECT  8.28 26.635 8.694 26.671 ;
     RECT  6.195 26.519 7.326 26.789 ;
     RECT  10.26 26.401 10.854 26.909 ;
     RECT  8.28 26.671 8.91 27.067 ;
     RECT  11.196 27.067 11.214 27.101 ;
     RECT  8.208 27.067 8.91 27.175 ;
     RECT  0.216 26.671 5.238 27.211 ;
     RECT  7.812 27.175 8.91 27.337 ;
     RECT  10.26 26.909 10.35 27.337 ;
     RECT  7.812 27.337 8.982 27.341 ;
     RECT  0.216 27.211 5.418 27.355 ;
     RECT  6.195 26.789 6.93 27.355 ;
     RECT  8.208 27.341 8.982 27.437 ;
     RECT  10.224 27.337 10.35 27.485 ;
     RECT  10.44 27.643 10.674 27.835 ;
     RECT  8.208 27.437 8.622 27.869 ;
     RECT  9.648 27.751 9.666 27.869 ;
     RECT  10.44 27.835 11.214 27.869 ;
     RECT  0.216 27.355 6.93 27.877 ;
     RECT  0.216 27.877 7.29 27.917 ;
     RECT  8.532 27.869 8.622 27.917 ;
     RECT  10.44 27.869 10.926 28.061 ;
     RECT  8.532 27.917 8.55 28.139 ;
     RECT  10.44 28.061 10.854 28.291 ;
     RECT  0.216 27.917 7.218 28.445 ;
     RECT  10.188 28.291 10.854 28.445 ;
     RECT  7.38 28.795 7.398 28.831 ;
     RECT  7.38 28.831 7.902 28.939 ;
     RECT  0.468 28.445 6.534 28.949 ;
     RECT  7.38 28.939 8.19 28.949 ;
     RECT  7.56 28.949 8.19 28.985 ;
     RECT  6.195 28.949 6.534 29.263 ;
     RECT  0.468 28.949 5.382 29.371 ;
     RECT  9.108 29.179 9.126 29.371 ;
     RECT  10.224 28.445 10.854 29.371 ;
     RECT  10.224 29.371 10.998 29.405 ;
     RECT  6.195 29.263 6.57 29.489 ;
     RECT  8.964 29.371 9.126 29.489 ;
     RECT  10.764 29.405 10.998 29.563 ;
     RECT  10.764 29.563 11.214 29.597 ;
     RECT  9 29.489 9.126 29.605 ;
     RECT  0.216 29.371 5.382 29.755 ;
     RECT  6.195 29.489 6.534 29.755 ;
     RECT  7.56 28.985 7.578 29.755 ;
     RECT  10.764 29.597 10.998 29.789 ;
     RECT  7.38 29.755 7.578 29.795 ;
     RECT  9 29.605 9.27 29.933 ;
     RECT  10.764 29.789 10.926 29.981 ;
     RECT  9.144 29.933 9.27 30.029 ;
     RECT  7.524 29.795 7.578 30.077 ;
     RECT  0.216 29.755 6.534 30.173 ;
     RECT  7.632 30.181 7.65 30.187 ;
     RECT  9.36 30.145 9.666 30.221 ;
     RECT  7.632 30.187 7.758 30.299 ;
     RECT  10.764 29.981 10.854 30.331 ;
     RECT  0.216 30.173 6.477 30.371 ;
     RECT  10.656 30.331 10.854 30.451 ;
     RECT  9.36 30.221 9.378 30.479 ;
     RECT  0.216 30.371 5.382 30.569 ;
     RECT  6.156 30.371 6.477 30.569 ;
     RECT  5.112 30.569 5.382 30.605 ;
     RECT  5.112 30.605 5.274 30.713 ;
     RECT  11.664 30.715 11.682 30.839 ;
     RECT  6.195 30.569 6.477 30.991 ;
     RECT  8.064 30.847 8.082 31.081 ;
     RECT  10.44 30.451 10.854 31.081 ;
     RECT  7.956 31.081 8.082 31.261 ;
     RECT  10.368 31.081 10.854 31.261 ;
     RECT  10.368 31.261 11.034 31.325 ;
     RECT  5.148 30.713 5.274 31.351 ;
     RECT  7.956 31.261 8.226 31.379 ;
     RECT  6.195 30.991 6.534 31.387 ;
     RECT  5.148 31.351 5.418 31.531 ;
     RECT  6.195 31.387 6.894 31.531 ;
     RECT  5.148 31.531 6.894 31.723 ;
     RECT  9.432 31.723 9.45 31.829 ;
     RECT  0.216 30.569 4.338 31.915 ;
     RECT  5.112 31.723 6.894 31.915 ;
     RECT  0.216 31.915 6.894 31.919 ;
     RECT  8.352 31.801 8.37 31.919 ;
     RECT  10.368 31.325 10.818 31.927 ;
     RECT  6.156 31.919 6.894 32.071 ;
     RECT  9.648 31.927 10.818 32.099 ;
     RECT  10.26 32.099 10.818 32.161 ;
     RECT  10.26 32.161 10.854 32.285 ;
     RECT  6.156 32.071 6.966 32.341 ;
     RECT  6.156 32.341 7.362 32.459 ;
     RECT  8.712 32.431 8.73 32.611 ;
     RECT  7.236 32.459 7.254 32.729 ;
     RECT  10.26 32.285 10.818 32.729 ;
     RECT  8.712 32.611 9.162 32.845 ;
     RECT  8.1 32.845 9.162 32.873 ;
     RECT  10.26 32.729 10.458 32.881 ;
     RECT  8.1 32.873 8.838 32.999 ;
     RECT  8.712 32.999 8.838 33.035 ;
     RECT  11.196 33.007 11.214 33.053 ;
     RECT  0.216 31.919 5.346 33.067 ;
     RECT  6.156 32.459 6.477 33.067 ;
     RECT  8.712 33.035 8.802 33.071 ;
     RECT  8.712 33.071 8.73 33.305 ;
     RECT  0.216 33.067 6.477 33.421 ;
     RECT  9.648 32.881 10.458 33.511 ;
     RECT  0.216 33.421 6.966 33.547 ;
     RECT  0.216 33.547 7.074 33.683 ;
     RECT  9.648 33.511 10.494 33.821 ;
     RECT  10.476 33.821 10.494 33.979 ;
     RECT  7.704 33.961 7.722 34.079 ;
     RECT  9.648 33.821 9.666 34.205 ;
     RECT  0.216 33.683 6.477 34.465 ;
     RECT  8.208 34.219 8.226 34.465 ;
     RECT  9.108 34.321 9.126 34.465 ;
     RECT  8.208 34.465 9.126 34.529 ;
     RECT  10.476 33.979 10.854 34.589 ;
     RECT  0.216 34.465 7.398 34.889 ;
     RECT  10.656 34.589 10.854 34.939 ;
     RECT  8.208 34.529 8.406 35.069 ;
     RECT  10.656 34.939 11.034 35.159 ;
     RECT  0.216 34.889 7.038 35.213 ;
     RECT  10.656 35.159 10.854 35.311 ;
     RECT  10.368 35.311 10.854 35.357 ;
     RECT  8.316 35.069 8.406 35.429 ;
     RECT  0.216 35.213 5.418 35.453 ;
     RECT  10.404 35.357 10.854 36.077 ;
     RECT  10.8 36.077 10.854 36.121 ;
     RECT  0.216 35.453 5.058 36.283 ;
     RECT  6.195 35.213 7.038 36.283 ;
     RECT  7.884 35.941 7.902 36.283 ;
     RECT  0.216 36.283 7.902 36.427 ;
     RECT  8.928 36.085 9.09 36.427 ;
     RECT  0.216 36.427 9.09 36.461 ;
     RECT  9.288 36.859 9.666 36.895 ;
     RECT  9.288 36.895 9.738 37.021 ;
     RECT  0.216 36.461 8.514 37.049 ;
     RECT  9.288 37.021 9.846 37.049 ;
     RECT  10.8 36.121 11.214 37.049 ;
     RECT  0.216 37.049 8.37 37.193 ;
     RECT  7.956 37.193 8.37 37.229 ;
     RECT  7.956 37.229 7.974 37.319 ;
     RECT  9.36 37.049 9.846 37.427 ;
     RECT  0.216 37.193 6.858 37.469 ;
     RECT  9.576 37.427 9.846 37.589 ;
     RECT  9.648 37.589 9.846 37.625 ;
     RECT  9.828 37.625 9.846 37.853 ;
     RECT  10.8 37.049 10.854 38.011 ;
     RECT  0.216 37.469 6.477 38.039 ;
     RECT  10.368 38.011 10.854 38.045 ;
     RECT  10.44 38.045 10.854 38.201 ;
     RECT  10.656 38.201 10.854 38.237 ;
     RECT  10.728 38.237 10.854 38.371 ;
     RECT  0.216 38.039 5.13 38.435 ;
     RECT  7.38 38.371 7.398 38.491 ;
     RECT  9.216 38.587 9.234 38.641 ;
     RECT  7.308 38.491 7.398 38.683 ;
     RECT  9.216 38.641 9.594 38.717 ;
     RECT  10.728 38.371 10.926 38.911 ;
     RECT  0.216 38.435 4.878 39.047 ;
     RECT  6.156 38.039 6.477 39.055 ;
     RECT  10.728 38.911 11.034 39.055 ;
     RECT  6.012 39.055 6.477 39.091 ;
     RECT  7.308 38.683 7.974 39.091 ;
     RECT  9.216 38.717 9.45 39.209 ;
     RECT  9.432 39.209 9.45 39.341 ;
     RECT  6.012 39.091 7.974 39.403 ;
     RECT  6.012 39.403 8.478 39.479 ;
     RECT  10.44 39.055 11.034 39.547 ;
     RECT  6.012 39.479 7.65 39.595 ;
     RECT  8.46 39.479 8.478 39.629 ;
     RECT  5.58 39.595 7.65 39.785 ;
     RECT  9.648 39.739 9.666 39.785 ;
     RECT  5.58 39.785 7.218 39.821 ;
     RECT  8.604 39.631 8.622 39.857 ;
     RECT  0.216 39.047 4.842 39.865 ;
     RECT  5.58 39.821 7.146 39.865 ;
     RECT  10.44 39.547 11.214 39.901 ;
     RECT  0.216 39.865 7.146 40.019 ;
     RECT  0.216 40.019 7.074 40.091 ;
     RECT  0.216 40.091 6.786 40.349 ;
     RECT  9.972 39.901 11.214 40.397 ;
     RECT  10.368 40.397 11.214 40.541 ;
     RECT  0.468 40.349 6.786 40.559 ;
     RECT  7.956 40.801 7.974 40.945 ;
     RECT  0.468 40.559 5.238 41.083 ;
     RECT  0.216 41.083 5.238 41.135 ;
     RECT  7.956 40.945 8.37 41.369 ;
     RECT  6.195 40.559 6.786 41.405 ;
     RECT  10.368 40.541 10.854 41.485 ;
     RECT  8.244 41.369 8.37 41.647 ;
     RECT  9.972 41.485 10.854 41.659 ;
     RECT  8.244 41.647 8.622 41.791 ;
     RECT  9.972 41.659 10.89 41.791 ;
     RECT  8.244 41.791 10.89 41.909 ;
     RECT  9.756 41.909 10.89 42.043 ;
     RECT  0.216 41.135 4.986 42.061 ;
     RECT  0.216 42.061 5.166 42.151 ;
     RECT  6.195 41.405 6.477 42.151 ;
     RECT  8.244 41.909 8.91 42.179 ;
     RECT  9.756 42.043 11.214 42.179 ;
     RECT  0.216 42.151 6.477 42.215 ;
     RECT  0.252 42.215 6.477 42.235 ;
     RECT  7.236 42.091 7.254 42.235 ;
     RECT  0.252 42.235 7.254 42.287 ;
     RECT  0.36 42.287 7.254 42.427 ;
     RECT  0.36 42.427 7.434 42.457 ;
     RECT  9.756 42.179 10.818 42.461 ;
     RECT  8.424 42.179 8.442 42.485 ;
     RECT  9.756 42.461 9.81 42.691 ;
     RECT  9.576 42.691 9.81 42.791 ;
     RECT  9.792 42.791 9.81 42.845 ;
     RECT  10.728 42.461 10.818 43.141 ;
     RECT  10.728 43.141 10.998 43.195 ;
     RECT  0.36 42.457 7.47 43.259 ;
     RECT  8.928 43.141 9.054 43.259 ;
     RECT  10.656 43.195 10.998 43.259 ;
     RECT  6.084 43.259 7.47 43.295 ;
     RECT  10.728 43.259 10.998 43.295 ;
     RECT  10.836 43.295 10.998 43.303 ;
     RECT  0.36 43.259 5.274 43.387 ;
     RECT  6.156 43.295 7.47 43.529 ;
     RECT  10.836 43.303 11.214 43.805 ;
     RECT  9.252 43.681 9.27 43.807 ;
     RECT  9.252 43.807 9.45 43.843 ;
     RECT  9.252 43.843 9.594 43.901 ;
     RECT  10.836 43.805 10.854 44.059 ;
     RECT  7.596 43.867 7.794 44.069 ;
     RECT  0.216 43.387 5.274 44.107 ;
     RECT  6.156 43.529 6.858 44.107 ;
     RECT  7.596 44.069 7.614 44.141 ;
     RECT  0.216 44.107 6.858 44.339 ;
     RECT  9.036 44.221 9.054 44.339 ;
     RECT  10.008 44.059 10.854 44.573 ;
     RECT  10.368 44.573 10.854 44.731 ;
     RECT  10.368 44.731 10.926 44.789 ;
     RECT  0.216 44.339 6.477 45.301 ;
     RECT  10.368 44.789 10.89 45.307 ;
     RECT  0.216 45.301 6.678 45.391 ;
     RECT  9.432 45.301 9.45 45.391 ;
     RECT  9.288 45.391 9.45 45.527 ;
     RECT  0.216 45.391 6.858 45.547 ;
     RECT  0.216 45.547 7.146 45.599 ;
     RECT  10.26 45.307 10.89 45.599 ;
     RECT  9.108 45.535 9.126 45.689 ;
     RECT  10.656 45.599 10.89 45.883 ;
     RECT  8.568 46.075 8.586 46.111 ;
     RECT  8.424 46.111 8.586 46.139 ;
     RECT  8.424 46.139 8.442 46.157 ;
     RECT  0.216 45.599 7.11 46.229 ;
     RECT  0.216 46.229 6.894 46.265 ;
     RECT  9.9 45.835 9.918 46.309 ;
     RECT  9.36 46.309 9.918 46.409 ;
     RECT  10.656 45.883 10.926 46.459 ;
     RECT  10.656 46.459 11.106 46.471 ;
     RECT  10.08 46.471 11.106 46.499 ;
     RECT  10.08 46.499 10.854 46.541 ;
     RECT  10.224 46.541 10.854 46.589 ;
     RECT  0.216 46.265 6.822 47.191 ;
     RECT  8.964 47.119 8.982 47.191 ;
     RECT  0.216 47.191 7.254 47.281 ;
     RECT  8.964 47.191 9.126 47.345 ;
     RECT  0.216 47.281 7.326 47.425 ;
     RECT  0.216 47.425 7.398 47.731 ;
     RECT  0.216 47.731 7.974 47.849 ;
     RECT  8.712 47.803 8.73 47.849 ;
     RECT  8.568 47.851 8.586 47.885 ;
     RECT  10.26 46.589 10.854 48.001 ;
     RECT  0.216 47.849 7.506 48.155 ;
     RECT  10.224 48.001 10.854 48.187 ;
     RECT  10.224 48.187 11.214 48.199 ;
     RECT  9.936 48.199 11.214 48.227 ;
     RECT  7.344 48.155 7.506 48.365 ;
     RECT  0.216 48.155 6.606 48.389 ;
     RECT  9.936 48.227 10.854 48.389 ;
     RECT  10.224 48.389 10.854 48.425 ;
     RECT  7.344 48.365 7.362 48.659 ;
     RECT  8.388 48.763 8.406 48.901 ;
     RECT  8.388 48.901 8.91 48.929 ;
     RECT  8.892 48.929 8.91 48.941 ;
     RECT  10.44 48.425 10.854 49.279 ;
     RECT  0.216 48.389 6.57 49.351 ;
     RECT  0.216 49.351 6.858 49.469 ;
     RECT  9.72 49.279 10.854 49.469 ;
     RECT  5.652 49.469 6.858 49.505 ;
     RECT  9.792 49.469 10.854 49.505 ;
     RECT  9 49.711 9.018 49.891 ;
     RECT  8.676 49.891 9.018 50.009 ;
     RECT  5.688 49.505 6.858 50.081 ;
     RECT  10.188 49.505 10.854 50.141 ;
     RECT  8.208 50.203 8.226 50.279 ;
     RECT  0.216 49.469 4.806 50.395 ;
     RECT  5.688 50.081 6.75 50.395 ;
     RECT  10.332 50.141 10.854 50.431 ;
     RECT  10.332 50.431 11.034 50.525 ;
     RECT  0.216 50.395 6.75 50.549 ;
     RECT  10.332 50.525 10.854 50.549 ;
     RECT  9.324 50.203 9.342 50.585 ;
     RECT  5.652 50.549 6.75 50.621 ;
     RECT  0.216 50.549 4.842 50.717 ;
     RECT  9.468 50.683 9.486 50.729 ;
     RECT  5.796 50.621 6.75 50.819 ;
     RECT  7.884 50.683 7.902 50.819 ;
     RECT  5.832 50.819 6.75 50.861 ;
     RECT  7.704 50.827 7.722 50.861 ;
     RECT  5.868 50.861 6.75 51.019 ;
     RECT  5.868 51.019 6.858 51.355 ;
     RECT  7.596 51.241 7.614 51.355 ;
     RECT  8.532 51.241 8.55 51.359 ;
     RECT  0.216 50.717 4.698 51.395 ;
     RECT  10.44 50.549 10.854 51.451 ;
     RECT  10.368 51.451 10.854 51.475 ;
     RECT  10.188 51.475 10.854 51.737 ;
     RECT  5.868 51.355 7.614 51.809 ;
     RECT  10.8 51.737 10.854 51.835 ;
     RECT  10.8 51.835 10.926 51.899 ;
     RECT  7.524 51.809 7.614 51.907 ;
     RECT  5.868 51.809 6.57 52.051 ;
     RECT  7.524 51.907 8.118 52.079 ;
     RECT  7.524 52.079 7.866 52.169 ;
     RECT  10.8 51.899 10.89 52.253 ;
     RECT  0.216 51.395 4.518 52.321 ;
     RECT  5.292 52.051 6.57 52.321 ;
     RECT  7.524 52.169 7.83 52.397 ;
     RECT  7.524 52.397 7.758 52.439 ;
     RECT  10.8 52.253 10.818 52.445 ;
     RECT  9.432 52.321 9.45 52.475 ;
     RECT  10.44 52.591 10.674 52.603 ;
     RECT  0.216 52.321 6.57 52.745 ;
     RECT  8.82 52.681 8.838 52.781 ;
     RECT  0.36 52.745 6.57 52.795 ;
     RECT  7.524 52.439 7.686 52.795 ;
     RECT  10.224 52.603 10.674 52.829 ;
     RECT  10.224 52.829 10.386 52.861 ;
     RECT  9.576 52.861 10.386 53.015 ;
     RECT  10.224 53.015 10.386 53.021 ;
     RECT  0.36 52.795 7.686 53.365 ;
     RECT  0.36 53.365 7.938 53.401 ;
     RECT  0.36 53.401 8.082 53.501 ;
     RECT  0.36 53.501 8.046 53.555 ;
     RECT  10.368 53.021 10.386 53.597 ;
     RECT  0.36 53.555 6.858 53.635 ;
     RECT  7.92 53.555 8.046 53.933 ;
     RECT  8.964 53.941 8.982 54.095 ;
     RECT  0.216 53.635 6.858 54.167 ;
     RECT  7.992 53.933 8.046 54.301 ;
     RECT  7.992 54.301 8.226 54.473 ;
     RECT  10.8 53.755 10.926 54.557 ;
     RECT  0.216 54.167 5.094 54.653 ;
     RECT  5.976 54.167 6.858 55.021 ;
     RECT  9.684 54.211 9.702 55.111 ;
     RECT  10.8 54.557 10.89 55.111 ;
     RECT  5.904 55.021 6.858 55.139 ;
     RECT  9.684 55.111 10.89 55.175 ;
     RECT  7.992 54.473 8.19 55.211 ;
     RECT  6.195 55.139 6.858 55.387 ;
     RECT  0.216 54.653 4.95 55.483 ;
     RECT  8.784 55.483 8.802 55.589 ;
     RECT  10.116 55.175 10.89 55.867 ;
     RECT  0.216 55.483 5.202 55.915 ;
     RECT  6.195 55.387 7.65 55.915 ;
     RECT  10.116 55.867 10.926 55.949 ;
     RECT  10.116 55.949 10.89 56.059 ;
     RECT  10.008 56.059 10.89 56.263 ;
     RECT  9.36 56.263 10.89 56.291 ;
     RECT  9.36 56.291 10.242 56.335 ;
     RECT  9.216 56.335 10.242 56.381 ;
     RECT  0.216 55.915 7.65 56.395 ;
     RECT  9.36 56.381 10.242 56.429 ;
     RECT  0.216 56.395 7.794 56.497 ;
     RECT  0.216 56.497 8.154 56.867 ;
     RECT  9.648 56.429 10.242 56.867 ;
     RECT  10.224 56.867 10.242 57.053 ;
     RECT  11.196 57.211 11.214 57.299 ;
     RECT  0.216 56.867 7.506 57.569 ;
     RECT  9.108 57.541 9.126 57.641 ;
     RECT  7.38 57.569 7.506 57.811 ;
     RECT  0.216 57.569 6.477 57.875 ;
     RECT  10.836 57.403 10.854 57.979 ;
     RECT  7.38 57.811 8.118 57.991 ;
     RECT  10.656 57.979 10.854 58.027 ;
     RECT  7.38 57.991 8.694 58.109 ;
     RECT  10.008 58.027 10.854 58.117 ;
     RECT  9.648 58.117 10.854 58.157 ;
     RECT  9.684 58.157 10.854 58.171 ;
     RECT  7.38 58.109 8.514 58.181 ;
     RECT  7.38 58.181 8.298 58.379 ;
     RECT  7.38 58.379 8.118 58.541 ;
     RECT  9.684 58.171 11.214 58.649 ;
     RECT  5.04 57.875 6.477 58.685 ;
     RECT  8.1 58.541 8.118 58.685 ;
     RECT  9.684 58.649 10.098 58.685 ;
     RECT  10.836 58.649 10.998 58.685 ;
     RECT  0.216 57.875 4.302 58.693 ;
     RECT  5.04 58.685 5.346 58.693 ;
     RECT  9.684 58.685 9.99 58.721 ;
     RECT  9.684 58.721 9.702 58.781 ;
     RECT  0.216 58.693 5.346 58.955 ;
     RECT  6.156 58.685 6.477 59.269 ;
     RECT  0.252 58.955 5.346 59.419 ;
     RECT  0.252 59.419 5.418 59.611 ;
     RECT  6.156 59.269 6.858 59.611 ;
     RECT  10.836 58.685 10.89 59.611 ;
     RECT  8.208 59.611 8.37 59.701 ;
     RECT  0.252 59.611 6.858 59.707 ;
     RECT  10.836 59.611 11.214 59.741 ;
     RECT  8.208 59.701 8.55 59.803 ;
     RECT  8.208 59.803 8.946 59.837 ;
     RECT  10.548 59.809 10.566 59.933 ;
     RECT  0.216 59.707 6.858 59.995 ;
     RECT  7.74 59.851 7.758 59.995 ;
     RECT  8.532 59.837 8.55 59.999 ;
     RECT  0.216 59.995 7.758 60.035 ;
     RECT  10.26 60.091 10.278 60.179 ;
     RECT  7.596 60.035 7.758 60.269 ;
     RECT  7.596 60.269 7.614 60.317 ;
     RECT  11.196 60.475 11.214 60.539 ;
     RECT  9.828 60.277 9.918 60.655 ;
     RECT  0.216 60.035 6.858 60.907 ;
     RECT  9.036 60.655 9.918 60.941 ;
     RECT  9.432 60.941 9.918 60.961 ;
     RECT  9.432 60.961 10.854 61.115 ;
     RECT  0.216 60.907 7.146 61.147 ;
     RECT  7.956 61.051 7.974 61.147 ;
     RECT  0.216 61.147 7.974 61.181 ;
     RECT  5.904 61.181 7.974 61.187 ;
     RECT  9.576 61.115 10.854 61.385 ;
     RECT  10.224 61.385 10.854 61.469 ;
     RECT  8.208 61.771 8.226 61.805 ;
     RECT  0.216 61.181 5.13 61.963 ;
     RECT  5.904 61.187 7.47 61.963 ;
     RECT  0.216 61.963 7.47 62.033 ;
     RECT  10.692 61.469 10.854 62.069 ;
     RECT  0.216 62.033 7.11 62.195 ;
     RECT  10.836 62.069 10.854 62.671 ;
     RECT  8.604 62.635 8.622 62.731 ;
     RECT  10.836 62.671 11.214 62.813 ;
     RECT  0.252 62.195 5.382 63.085 ;
     RECT  6.195 62.195 7.11 63.085 ;
     RECT  6.195 63.085 7.434 63.211 ;
     RECT  8.46 62.731 8.622 63.211 ;
     RECT  8.46 63.211 9.162 63.275 ;
     RECT  10.836 62.813 11.034 63.389 ;
     RECT  0.216 63.085 5.382 63.391 ;
     RECT  6.195 63.211 7.686 63.391 ;
     RECT  9.036 63.275 9.162 63.481 ;
     RECT  0.216 63.391 7.686 63.509 ;
     RECT  0.216 63.509 7.506 63.545 ;
     RECT  9.036 63.481 9.666 63.589 ;
     RECT  9.036 63.589 10.026 63.661 ;
     RECT  9.036 63.661 10.098 63.823 ;
     RECT  10.836 63.389 10.854 63.823 ;
     RECT  9.036 63.823 10.854 64.021 ;
     RECT  8.712 64.021 10.854 64.291 ;
     RECT  8.712 64.291 11.142 64.349 ;
     RECT  8.712 64.349 9.45 64.471 ;
     RECT  10.224 64.349 11.142 64.541 ;
     RECT  8.568 64.471 9.45 64.589 ;
     RECT  10.224 64.541 10.926 64.589 ;
     RECT  0.216 63.545 7.29 64.625 ;
     RECT  6.048 64.625 7.29 64.705 ;
     RECT  10.368 64.589 10.926 64.733 ;
     RECT  6.048 64.705 7.506 64.741 ;
     RECT  8.568 64.589 8.73 64.741 ;
     RECT  6.048 64.741 8.73 64.859 ;
     RECT  6.048 64.859 8.586 65.003 ;
     RECT  10.368 64.733 10.89 65.117 ;
     RECT  6.048 65.003 8.37 65.129 ;
     RECT  0.216 64.625 5.238 65.309 ;
     RECT  6.195 65.129 8.37 65.309 ;
     RECT  10.368 65.117 10.818 65.851 ;
     RECT  10.224 65.851 10.818 66.043 ;
     RECT  6.195 65.309 7.65 66.139 ;
     RECT  9.612 66.043 10.818 66.181 ;
     RECT  9.612 66.181 10.854 66.479 ;
     RECT  9.612 66.479 9.774 66.595 ;
     RECT  10.836 66.479 10.854 66.619 ;
     RECT  6.12 66.139 7.65 66.667 ;
     RECT  9.576 66.595 9.774 66.701 ;
     RECT  0.216 65.309 5.13 66.757 ;
     RECT  6.12 66.667 8.118 66.757 ;
     RECT  0.216 66.757 8.118 66.797 ;
     RECT  8.352 66.859 8.37 66.901 ;
     RECT  10.836 66.619 11.214 66.901 ;
     RECT  8.352 66.901 8.622 67.171 ;
     RECT  9.576 66.701 9.666 67.171 ;
     RECT  8.352 67.171 9.666 67.469 ;
     RECT  9 67.469 9.666 67.595 ;
     RECT  0.216 66.797 7.326 67.603 ;
     RECT  10.836 66.901 11.25 67.613 ;
     RECT  0.216 67.603 7.866 67.709 ;
     RECT  9.108 67.595 9.666 67.711 ;
     RECT  7.812 67.709 7.866 67.739 ;
     RECT  0.216 67.709 6.534 67.853 ;
     RECT  9.108 67.711 9.882 67.963 ;
     RECT  10.656 67.771 10.674 67.963 ;
     RECT  6.012 67.853 6.534 68.099 ;
     RECT  7.848 67.739 7.866 68.099 ;
     RECT  6.084 68.099 6.534 68.135 ;
     RECT  0.216 67.853 5.274 68.141 ;
     RECT  9.108 67.963 10.674 68.341 ;
     RECT  9.108 68.341 10.854 68.369 ;
     RECT  9.576 68.369 10.854 68.405 ;
     RECT  10.26 68.405 10.854 68.573 ;
     RECT  6.195 68.135 6.534 68.881 ;
     RECT  6.195 68.881 7.254 68.923 ;
     RECT  8.532 68.881 8.694 68.957 ;
     RECT  8.532 68.957 8.55 69.005 ;
     RECT  6.195 68.923 7.362 69.061 ;
     RECT  10.836 68.573 10.854 69.115 ;
     RECT  6.195 69.061 8.406 69.151 ;
     RECT  5.4 69.151 8.406 69.245 ;
     RECT  9.54 69.295 9.558 69.331 ;
     RECT  9.54 69.331 9.702 69.341 ;
     RECT  9.684 69.341 9.702 69.389 ;
     RECT  10.836 69.115 10.926 69.493 ;
     RECT  7.632 69.245 8.406 69.521 ;
     RECT  7.632 69.521 7.65 69.533 ;
     RECT  10.8 69.493 10.926 69.533 ;
     RECT  5.4 69.245 6.75 69.547 ;
     RECT  0.216 68.141 4.626 69.601 ;
     RECT  5.364 69.547 6.75 69.601 ;
     RECT  11.088 69.691 11.106 69.725 ;
     RECT  8.388 69.521 8.406 69.989 ;
     RECT  10.224 69.601 10.242 70.267 ;
     RECT  10.224 70.267 10.854 70.493 ;
     RECT  10.476 70.493 10.854 70.645 ;
     RECT  0.216 69.601 6.75 70.681 ;
     RECT  7.92 70.411 8.01 70.681 ;
     RECT  8.784 70.645 8.802 70.685 ;
     RECT  10.476 70.645 11.214 70.685 ;
     RECT  0.216 70.681 8.01 70.747 ;
     RECT  0.216 70.747 8.694 70.799 ;
     RECT  7.992 70.799 8.01 70.871 ;
     RECT  0.216 70.799 7.218 70.877 ;
     RECT  10.476 70.685 10.854 71.069 ;
     RECT  0.216 70.877 7.002 71.213 ;
     RECT  10.008 71.581 10.026 71.755 ;
     RECT  9.756 71.755 10.026 71.761 ;
     RECT  10.836 71.069 10.854 71.761 ;
     RECT  9.612 71.761 10.026 71.789 ;
     RECT  9.612 71.789 9.63 71.837 ;
     RECT  10.836 71.761 11.106 71.837 ;
     RECT  7.956 71.755 7.974 71.995 ;
     RECT  7.812 71.995 7.974 72.029 ;
     RECT  9.144 71.995 9.162 72.283 ;
     RECT  0.216 71.213 6.786 72.301 ;
     RECT  8.748 72.283 9.162 72.391 ;
     RECT  0.216 72.301 7.434 72.455 ;
     RECT  8.496 72.391 9.162 72.491 ;
     RECT  10.368 72.121 10.386 72.571 ;
     RECT  10.368 72.571 10.674 72.661 ;
     RECT  0.216 72.455 6.57 72.689 ;
     RECT  7.344 72.455 7.362 72.689 ;
     RECT  0.216 72.689 6.477 72.761 ;
     RECT  10.368 72.661 10.926 72.763 ;
     RECT  9.144 72.491 9.162 72.811 ;
     RECT  10.368 72.763 11.214 72.811 ;
     RECT  9.144 72.811 11.214 72.959 ;
     RECT  9.144 72.959 10.998 72.995 ;
     RECT  9.144 72.995 10.926 73.181 ;
     RECT  0.216 72.761 5.382 73.229 ;
     RECT  0.216 73.229 4.266 73.265 ;
     RECT  9.144 73.181 9.594 73.409 ;
     RECT  10.728 73.181 10.926 73.565 ;
     RECT  5.112 73.229 5.382 73.651 ;
     RECT  6.156 72.761 6.477 73.651 ;
     RECT  9 73.651 9.018 73.841 ;
     RECT  10.728 73.565 10.854 73.949 ;
     RECT  0.216 73.265 4.23 74.011 ;
     RECT  5.112 73.651 6.477 74.011 ;
     RECT  7.272 73.885 7.29 74.011 ;
     RECT  0.216 74.011 6.477 74.045 ;
     RECT  8.604 74.011 8.622 74.047 ;
     RECT  7.272 74.011 7.326 74.083 ;
     RECT  8.46 74.047 8.622 74.093 ;
     RECT  5.22 74.045 6.477 74.107 ;
     RECT  7.272 74.083 7.434 74.107 ;
     RECT  5.22 74.107 7.434 74.345 ;
     RECT  9.072 74.731 9.09 74.779 ;
     RECT  10.044 74.011 10.242 74.779 ;
     RECT  9.072 74.779 10.242 74.849 ;
     RECT  9.828 74.849 10.242 74.993 ;
     RECT  10.476 75.001 10.71 75.067 ;
     RECT  0.216 74.045 4.338 75.091 ;
     RECT  5.22 74.345 6.477 75.091 ;
     RECT  7.704 75.127 7.722 75.163 ;
     RECT  8.604 75.001 8.838 75.197 ;
     RECT  10.476 75.067 10.926 75.259 ;
     RECT  10.476 75.259 11.214 75.389 ;
     RECT  10.548 75.389 11.214 75.541 ;
     RECT  7.344 75.163 7.722 75.631 ;
     RECT  8.604 75.197 8.658 75.631 ;
     RECT  7.344 75.631 8.658 75.677 ;
     RECT  10.548 75.541 11.25 75.677 ;
     RECT  0.216 75.091 6.477 75.691 ;
     RECT  7.344 75.677 7.398 75.691 ;
     RECT  8.136 75.677 8.658 75.725 ;
     RECT  8.64 75.725 8.658 75.929 ;
     RECT  10.548 75.677 11.214 76.199 ;
     RECT  10.548 76.199 10.854 76.235 ;
     RECT  8.784 76.081 8.802 76.397 ;
     RECT  10.8 76.235 10.854 76.445 ;
     RECT  9.072 76.411 9.09 76.469 ;
     RECT  0.216 75.691 7.398 76.541 ;
     RECT  9.144 76.549 9.774 76.637 ;
     RECT  9.144 76.637 9.666 76.649 ;
     RECT  0.216 76.541 6.786 76.739 ;
     RECT  9.216 76.649 9.666 76.739 ;
     RECT  6.156 76.739 6.786 76.781 ;
     RECT  7.524 76.747 8.046 76.781 ;
     RECT  0.216 76.739 5.418 76.811 ;
     RECT  6.156 76.781 6.714 77.009 ;
     RECT  9.648 76.739 9.666 77.021 ;
     RECT  6.195 77.009 6.534 77.045 ;
     RECT  7.524 76.781 7.542 77.165 ;
     RECT  10.836 76.445 10.854 77.371 ;
     RECT  10.836 77.371 10.926 77.459 ;
     RECT  0.216 76.811 5.346 77.899 ;
     RECT  6.195 77.045 6.477 77.899 ;
     RECT  10.836 77.459 10.854 78.331 ;
     RECT  10.332 78.331 10.854 78.365 ;
     RECT  9.108 78.235 9.126 78.395 ;
     RECT  7.344 78.241 7.362 78.403 ;
     RECT  7.344 78.403 7.65 78.511 ;
     RECT  10.548 78.365 10.854 78.557 ;
     RECT  7.344 78.511 8.262 78.629 ;
     RECT  10.836 78.557 10.854 78.637 ;
     RECT  0.216 77.899 6.477 78.781 ;
     RECT  7.344 78.629 8.118 78.781 ;
     RECT  9.252 78.667 9.27 79.051 ;
     RECT  10.836 78.637 11.214 79.133 ;
     RECT  9.252 79.051 9.45 79.213 ;
     RECT  0.216 78.781 8.118 79.241 ;
     RECT  9.252 79.213 9.81 79.321 ;
     RECT  9.108 79.321 9.81 79.325 ;
     RECT  9.108 79.325 9.27 79.439 ;
     RECT  8.1 79.241 8.118 79.447 ;
     RECT  9.108 79.439 9.126 79.447 ;
     RECT  10.836 79.133 11.034 79.483 ;
     RECT  8.1 79.447 9.126 79.547 ;
     RECT  8.1 79.547 8.658 79.583 ;
     RECT  10.764 79.483 11.034 79.709 ;
     RECT  10.764 79.709 10.926 79.717 ;
     RECT  8.136 79.583 8.658 79.757 ;
     RECT  8.244 79.757 8.658 79.979 ;
     RECT  10.224 79.717 10.926 79.979 ;
     RECT  0.216 79.241 7.074 80.095 ;
     RECT  8.244 79.979 8.262 80.123 ;
     RECT  0.216 80.095 7.218 80.249 ;
     RECT  0.216 80.249 6.858 80.285 ;
     RECT  0.216 80.285 6.477 80.519 ;
     RECT  10.584 79.979 10.854 80.827 ;
     RECT  10.332 80.827 10.854 81.019 ;
     RECT  10.332 81.019 10.998 81.059 ;
     RECT  9.072 80.671 9.09 81.175 ;
     RECT  9.072 81.175 9.486 81.211 ;
     RECT  7.956 80.761 8.154 81.239 ;
     RECT  6.012 80.519 6.477 81.245 ;
     RECT  9.072 81.211 9.666 81.245 ;
     RECT  6.195 81.245 6.477 81.301 ;
     RECT  9.648 81.245 9.666 81.329 ;
     RECT  0.216 80.519 5.238 81.365 ;
     RECT  7.812 81.403 7.83 81.473 ;
     RECT  6.195 81.301 6.858 81.481 ;
     RECT  6.195 81.481 7.146 81.533 ;
     RECT  8.604 81.301 8.838 81.635 ;
     RECT  10.836 81.059 10.854 81.841 ;
     RECT  0.216 81.365 5.058 82.291 ;
     RECT  6.195 81.533 7.002 82.363 ;
     RECT  10.836 81.841 10.89 82.363 ;
     RECT  6.195 82.363 7.038 82.409 ;
     RECT  10.584 82.363 10.89 82.409 ;
     RECT  6.195 82.409 6.966 82.517 ;
     RECT  6.195 82.517 6.822 82.679 ;
     RECT  10.836 82.409 10.89 82.781 ;
     RECT  6.195 82.679 6.477 82.795 ;
     RECT  0.216 82.291 5.166 83.065 ;
     RECT  6.084 82.795 6.477 83.065 ;
     RECT  10.836 82.781 10.854 83.131 ;
     RECT  10.656 83.131 10.854 83.191 ;
     RECT  7.632 83.179 7.65 83.219 ;
     RECT  10.44 83.191 10.854 83.291 ;
     RECT  8.424 83.371 8.442 83.461 ;
     RECT  8.424 83.461 8.658 83.489 ;
     RECT  0.216 83.065 6.477 83.549 ;
     RECT  9.648 83.497 9.666 83.549 ;
     RECT  8.532 83.489 8.658 83.569 ;
     RECT  0.252 83.549 6.477 83.611 ;
     RECT  7.488 83.335 7.542 83.641 ;
     RECT  10.656 83.291 10.854 83.731 ;
     RECT  8.532 83.569 9.126 83.759 ;
     RECT  10.656 83.731 10.926 83.767 ;
     RECT  0.252 83.611 6.534 83.803 ;
     RECT  7.452 83.641 7.542 83.803 ;
     RECT  0.252 83.803 7.542 83.885 ;
     RECT  8.532 83.759 8.982 84.029 ;
     RECT  8.964 84.029 8.982 84.137 ;
     RECT  6.156 83.885 7.542 84.181 ;
     RECT  6.156 84.181 7.578 84.271 ;
     RECT  6.156 84.271 8.19 84.317 ;
     RECT  10.656 83.767 11.214 84.343 ;
     RECT  6.156 84.317 6.642 84.365 ;
     RECT  7.416 84.317 8.046 84.365 ;
     RECT  10.656 84.343 11.25 84.509 ;
     RECT  6.156 84.365 6.477 84.649 ;
     RECT  0.252 83.885 5.274 84.667 ;
     RECT  10.656 84.509 11.214 84.811 ;
     RECT  10.584 84.811 11.214 84.893 ;
     RECT  0.216 84.667 5.274 84.991 ;
     RECT  6.084 84.649 6.477 84.991 ;
     RECT  10.836 84.893 11.214 85.109 ;
     RECT  9.216 85.225 9.234 85.261 ;
     RECT  9.216 85.261 9.378 85.277 ;
     RECT  9.36 85.277 9.378 85.379 ;
     RECT  0.216 84.991 6.477 85.387 ;
     RECT  7.416 84.365 7.542 85.387 ;
     RECT  0.216 85.387 7.614 85.435 ;
     RECT  0.216 85.435 7.794 85.657 ;
     RECT  0.216 85.657 7.866 85.685 ;
     RECT  0.216 85.685 6.858 85.757 ;
     RECT  10.836 85.109 10.854 86.395 ;
     RECT  7.848 85.685 7.866 86.431 ;
     RECT  10.368 86.395 10.854 86.459 ;
     RECT  7.848 86.431 8.046 86.467 ;
     RECT  0.216 85.757 6.477 86.491 ;
     RECT  7.596 86.467 8.298 86.639 ;
     RECT  11.736 86.731 11.754 86.737 ;
     RECT  11.664 86.737 11.754 86.765 ;
     RECT  11.664 86.765 11.682 86.813 ;
     RECT  10.584 86.459 10.854 87.005 ;
     RECT  0.216 86.491 6.786 87.007 ;
     RECT  8.928 87.115 8.946 87.149 ;
     RECT  0.216 87.007 6.858 87.151 ;
     RECT  7.596 86.639 8.118 87.151 ;
     RECT  10.8 87.005 10.854 87.151 ;
     RECT  10.8 87.151 11.034 87.197 ;
     RECT  0.216 87.151 8.118 87.269 ;
     RECT  10.8 87.197 10.854 87.719 ;
     RECT  0.216 87.269 7.434 87.809 ;
     RECT  7.2 87.809 7.434 88.051 ;
     RECT  8.172 87.421 8.19 88.051 ;
     RECT  10.836 87.719 10.854 88.051 ;
     RECT  9.144 87.511 9.162 88.195 ;
     RECT  7.2 88.051 8.19 88.231 ;
     RECT  7.2 88.231 8.334 88.267 ;
     RECT  9.144 88.195 9.27 88.267 ;
     RECT  7.2 88.267 9.27 88.315 ;
     RECT  7.2 88.315 9.414 88.349 ;
     RECT  10.836 88.051 10.926 88.541 ;
     RECT  0.216 87.809 6.477 88.699 ;
     RECT  7.2 88.349 8.01 88.699 ;
     RECT  0.216 88.699 8.01 88.925 ;
     RECT  7.992 88.925 8.01 89.069 ;
     RECT  10.836 88.541 10.89 89.275 ;
     RECT  0.216 88.925 6.858 89.309 ;
     RECT  10.8 89.275 10.89 89.401 ;
     RECT  8.784 89.401 8.802 89.453 ;
     RECT  0.252 89.309 6.858 89.501 ;
     RECT  10.8 89.401 10.926 89.581 ;
     RECT  10.44 89.581 10.926 89.699 ;
     RECT  9.144 89.581 9.234 89.969 ;
     RECT  9.972 89.851 9.99 89.969 ;
     RECT  7.776 89.851 7.794 89.977 ;
     RECT  0.288 89.501 6.858 90.235 ;
     RECT  9.648 90.211 9.666 90.269 ;
     RECT  10.8 89.699 10.926 90.347 ;
     RECT  0.216 90.235 6.858 90.391 ;
     RECT  7.596 89.977 8.046 90.391 ;
     RECT  0.216 90.391 8.046 90.557 ;
     RECT  8.028 90.557 8.046 90.571 ;
     RECT  8.028 90.571 8.406 90.617 ;
     RECT  10.836 90.347 10.926 90.653 ;
     RECT  8.028 90.617 8.298 90.689 ;
     RECT  0.216 90.557 7.11 91.085 ;
     RECT  9.18 91.243 9.198 91.291 ;
     RECT  9.18 91.291 9.342 91.319 ;
     RECT  10.836 90.653 10.854 91.387 ;
     RECT  10.692 91.387 10.854 91.471 ;
     RECT  10.692 91.471 11.214 91.499 ;
     RECT  0.252 91.085 7.11 91.579 ;
     RECT  8.028 90.689 8.154 91.579 ;
     RECT  9.324 91.319 9.342 91.589 ;
     RECT  10.836 91.499 11.214 91.613 ;
     RECT  0.252 91.579 8.154 91.963 ;
     RECT  10.836 91.613 10.89 92.347 ;
     RECT  0.216 91.963 8.154 92.471 ;
     RECT  10.836 92.347 10.926 92.669 ;
     RECT  9 92.551 9.018 92.677 ;
     RECT  9.864 92.641 9.882 92.677 ;
     RECT  9 92.677 9.882 92.705 ;
     RECT  9.144 92.705 9.882 92.765 ;
     RECT  9.144 92.765 9.63 92.777 ;
     RECT  7.236 92.471 8.154 92.923 ;
     RECT  9.144 92.777 9.45 92.939 ;
     RECT  0.216 92.471 6.477 92.957 ;
     RECT  9.216 92.939 9.45 92.975 ;
     RECT  10.836 92.669 10.89 93.091 ;
     RECT  10.656 93.091 10.89 93.149 ;
     RECT  9.36 92.975 9.45 93.209 ;
     RECT  6.195 92.957 6.477 93.217 ;
     RECT  7.236 92.923 8.226 93.217 ;
     RECT  6.195 93.217 8.226 93.317 ;
     RECT  9.432 93.209 9.45 93.317 ;
     RECT  7.92 93.317 8.226 93.361 ;
     RECT  10.836 93.149 10.89 93.451 ;
     RECT  7.92 93.361 8.37 93.479 ;
     RECT  6.195 93.317 7.038 93.485 ;
     RECT  10.836 93.451 11.214 93.533 ;
     RECT  7.92 93.479 8.154 94.019 ;
     RECT  0.216 92.957 5.454 94.027 ;
     RECT  6.195 93.485 6.858 94.027 ;
     RECT  8.136 94.019 8.154 94.061 ;
     RECT  10.836 93.533 10.926 94.109 ;
     RECT  0.216 94.027 6.858 94.261 ;
     RECT  0.216 94.261 7.038 94.325 ;
     RECT  10.836 94.109 10.854 94.441 ;
     RECT  0.252 94.325 7.038 94.711 ;
     RECT  10.512 94.441 10.854 94.837 ;
     RECT  9.684 94.795 9.702 94.865 ;
     RECT  10.512 94.837 11.214 94.877 ;
     RECT  10.512 94.877 10.998 94.981 ;
     RECT  9.864 94.981 10.998 95.099 ;
     RECT  9.864 95.099 10.89 95.165 ;
     RECT  0.252 94.711 7.146 95.227 ;
     RECT  0.216 95.227 7.146 95.251 ;
     RECT  10.584 95.165 10.89 95.261 ;
     RECT  0.216 95.251 7.218 95.467 ;
     RECT  7.956 95.131 7.974 95.467 ;
     RECT  10.836 95.261 10.89 95.645 ;
     RECT  0.216 95.467 7.974 95.693 ;
     RECT  8.028 95.881 8.046 95.933 ;
     RECT  0.216 95.693 6.858 96.017 ;
     RECT  9.684 96.061 9.702 96.221 ;
     RECT  10.836 95.645 10.854 96.571 ;
     RECT  9.144 96.565 9.666 96.605 ;
     RECT  10.764 96.571 10.854 96.629 ;
     RECT  7.632 96.601 7.65 96.719 ;
     RECT  0.216 96.017 6.477 97.003 ;
     RECT  9.54 96.605 9.666 97.141 ;
     RECT  0.216 97.003 6.678 97.259 ;
     RECT  9.54 97.141 9.918 97.295 ;
     RECT  10.836 96.629 10.854 97.411 ;
     RECT  10.836 97.411 10.89 97.565 ;
     RECT  9.648 97.295 9.666 97.757 ;
     RECT  10.836 97.565 10.854 98.107 ;
     RECT  9.792 98.149 9.81 98.189 ;
     RECT  0.216 97.259 6.477 98.221 ;
     RECT  8.46 98.059 8.478 98.221 ;
     RECT  10.656 98.107 10.854 98.339 ;
     RECT  8.136 98.221 8.622 98.419 ;
     RECT  7.884 98.419 8.622 98.539 ;
     RECT  10.836 98.339 10.854 98.581 ;
     RECT  7.884 98.539 9.342 98.587 ;
     RECT  7.632 98.587 9.342 98.609 ;
     RECT  0.216 98.221 6.606 98.635 ;
     RECT  0.216 98.635 6.894 98.681 ;
     RECT  7.632 98.609 8.118 98.683 ;
     RECT  10.836 98.581 11.214 98.915 ;
     RECT  9.18 98.609 9.342 98.995 ;
     RECT  9.18 98.995 9.558 99.031 ;
     RECT  9.18 99.031 9.702 99.053 ;
     RECT  9.468 99.053 9.702 99.101 ;
     RECT  7.416 98.683 8.118 99.185 ;
     RECT  9.684 99.101 9.702 99.197 ;
     RECT  0.216 98.681 6.477 99.427 ;
     RECT  10.836 98.915 10.854 99.571 ;
     RECT  10.44 99.571 10.854 99.643 ;
     RECT  7.992 99.185 8.118 99.689 ;
     RECT  10.44 99.643 11.214 99.689 ;
     RECT  8.496 99.691 8.514 99.725 ;
     RECT  0.216 99.427 7.218 99.869 ;
     RECT  9.036 100.111 9.054 100.315 ;
     RECT  9.9 99.931 9.918 100.315 ;
     RECT  10.764 99.689 10.854 100.603 ;
     RECT  7.416 100.111 7.578 100.651 ;
     RECT  9.036 100.315 9.918 100.651 ;
     RECT  10.764 100.603 10.926 100.651 ;
     RECT  9.036 100.651 10.926 100.679 ;
     RECT  9.036 100.679 10.854 100.741 ;
     RECT  7.416 100.651 7.902 100.769 ;
     RECT  8.892 100.741 10.854 100.769 ;
     RECT  7.416 100.769 7.722 100.795 ;
     RECT  8.892 100.769 9.666 100.829 ;
     RECT  10.548 100.769 10.854 100.829 ;
     RECT  7.236 100.795 7.722 100.877 ;
     RECT  8.712 100.843 8.73 100.877 ;
     RECT  9.54 100.829 9.666 100.877 ;
     RECT  10.548 100.829 10.566 101.021 ;
     RECT  0.216 99.869 6.477 101.035 ;
     RECT  7.236 100.877 7.254 101.035 ;
     RECT  0.216 101.035 7.254 101.039 ;
     RECT  0.216 101.039 7.074 101.075 ;
     RECT  9.648 100.877 9.666 101.417 ;
     RECT  8.64 101.587 8.658 101.623 ;
     RECT  8.388 101.623 8.658 101.695 ;
     RECT  8.244 101.695 8.658 101.731 ;
     RECT  8.244 101.731 9.198 101.741 ;
     RECT  10.188 101.551 10.35 101.755 ;
     RECT  8.388 101.741 9.198 101.759 ;
     RECT  8.388 101.759 8.406 101.849 ;
     RECT  9.18 101.759 9.198 101.849 ;
     RECT  0.216 101.075 6.678 101.929 ;
     RECT  0.216 101.929 6.966 101.947 ;
     RECT  10.188 101.755 10.674 102.125 ;
     RECT  10.44 102.125 10.674 102.271 ;
     RECT  10.44 102.271 10.854 102.425 ;
     RECT  10.8 102.425 10.854 102.523 ;
     RECT  10.8 102.523 10.926 102.569 ;
     RECT  0.216 101.947 7.146 102.667 ;
     RECT  0.216 102.667 7.47 102.695 ;
     RECT  10.8 102.569 10.854 102.749 ;
     RECT  0.468 102.695 7.47 103.109 ;
     RECT  9.684 103.081 9.702 103.133 ;
     RECT  8.712 103.351 8.73 103.441 ;
     RECT  8.712 103.441 9.234 103.621 ;
     RECT  10.8 102.749 10.818 103.621 ;
     RECT  0.468 103.109 6.858 103.675 ;
     RECT  7.596 103.243 7.614 103.675 ;
     RECT  10.224 103.621 10.818 103.675 ;
     RECT  7.596 103.675 7.65 103.723 ;
     RECT  8.532 103.621 9.234 103.723 ;
     RECT  7.596 103.723 9.234 103.739 ;
     RECT  10.224 103.675 11.214 103.739 ;
     RECT  9.072 103.739 9.234 103.757 ;
     RECT  10.224 103.739 10.854 103.775 ;
     RECT  10.476 103.775 10.854 103.901 ;
     RECT  0.216 103.675 6.858 104.011 ;
     RECT  7.596 103.739 8.154 104.011 ;
     RECT  0.216 104.011 8.154 104.045 ;
     RECT  0.216 104.045 7.254 104.279 ;
     RECT  10.656 103.901 10.854 104.285 ;
     RECT  8.136 104.045 8.154 104.315 ;
     RECT  10.656 104.285 10.674 104.477 ;
     RECT  9.648 103.981 9.666 104.669 ;
     RECT  0.216 104.279 6.966 104.729 ;
     RECT  0.468 104.729 6.966 104.819 ;
     RECT  0.468 104.819 6.477 105.047 ;
     RECT  0.468 105.047 6.285 105.125 ;
     RECT  0.468 105.125 1.242 105.197 ;
     RECT  3.06 105.125 3.078 105.197 ;
     RECT  5.508 105.125 6.285 105.233 ;
     RECT  3.96 105.125 3.978 105.269 ;
     RECT  0.795 105.197 0.885 105.317 ;
     RECT  6.195 105.233 6.285 105.317 ;
    LAYER M4 ;
     RECT  0.085 62.496 0.156 62.52 ;
     RECT  0.085 63.84 0.156 63.864 ;
     RECT  0.156 0.384 0.788 104.664 ;
     RECT  0.788 0.384 0.892 105.312 ;
     RECT  0.892 0.384 1.084 105.042 ;
     RECT  1.084 0.384 1.253 104.904 ;
     RECT  1.253 0.72 2.513 104.904 ;
     RECT  2.513 0.96 2.819 104.904 ;
     RECT  2.819 55.152 2.867 104.904 ;
     RECT  2.819 0.96 2.909 54.12 ;
     RECT  2.867 55.248 3.013 104.904 ;
     RECT  3.013 55.248 3.233 104.952 ;
     RECT  3.233 55.68 3.443 104.952 ;
     RECT  2.909 0.96 3.635 53.64 ;
     RECT  3.635 0.96 3.773 42.888 ;
     RECT  3.773 0.96 3.781 42.792 ;
     RECT  3.443 64.848 3.845 104.952 ;
     RECT  3.781 0.768 3.949 42.792 ;
     RECT  3.845 69.36 4.061 104.952 ;
     RECT  3.949 0.72 4.097 42.792 ;
     RECT  4.097 0.72 4.133 40.104 ;
     RECT  3.443 55.68 4.169 63.864 ;
     RECT  3.635 44.064 4.201 53.64 ;
     RECT  4.169 55.68 4.205 63.192 ;
     RECT  4.133 0.72 4.211 33.144 ;
     RECT  4.205 55.68 4.237 63.096 ;
     RECT  4.133 34.128 4.277 40.104 ;
     RECT  4.211 26.64 4.403 33.144 ;
     RECT  4.237 55.248 4.529 63.096 ;
     RECT  4.097 41.376 4.547 42.792 ;
     RECT  4.201 44.064 4.597 53.784 ;
     RECT  4.403 26.736 4.601 33.144 ;
     RECT  4.597 43.92 4.669 53.784 ;
     RECT  4.211 0.72 4.709 25.56 ;
     RECT  4.529 55.248 4.813 56.52 ;
     RECT  4.277 34.128 4.817 40.008 ;
     RECT  4.817 34.128 4.931 38.136 ;
     RECT  4.817 39.216 4.931 40.008 ;
     RECT  4.709 1.056 4.997 25.56 ;
     RECT  4.669 43.92 5.065 54.168 ;
     RECT  4.813 55.152 5.065 56.52 ;
     RECT  4.931 34.128 5.069 37.656 ;
     RECT  4.547 41.376 5.069 42.456 ;
     RECT  4.061 69.36 5.069 104.904 ;
     RECT  5.065 43.92 5.101 56.52 ;
     RECT  5.101 43.824 5.123 56.52 ;
     RECT  5.069 90 5.123 104.904 ;
     RECT  5.123 43.824 5.171 51.384 ;
     RECT  4.529 57.504 5.317 63.096 ;
     RECT  5.317 57.504 5.389 63.768 ;
     RECT  5.069 69.36 5.605 88.968 ;
     RECT  3.845 64.848 5.653 68.232 ;
     RECT  5.605 69.216 5.653 88.968 ;
     RECT  5.123 52.464 5.677 56.52 ;
     RECT  5.389 57.504 5.677 63.864 ;
     RECT  5.677 52.464 5.701 63.864 ;
     RECT  5.653 64.848 5.701 88.968 ;
     RECT  4.601 26.736 5.749 33.048 ;
     RECT  5.069 41.376 5.749 42.264 ;
     RECT  4.931 39.216 6.001 39.816 ;
     RECT  5.749 41.136 6.037 42.264 ;
     RECT  4.997 1.056 6.188 25.512 ;
     RECT  5.749 26.736 6.188 33.096 ;
     RECT  5.069 34.128 6.188 37.608 ;
     RECT  6.001 39.072 6.188 39.816 ;
     RECT  6.037 41.136 6.188 42.792 ;
     RECT  5.171 44.064 6.188 51.384 ;
     RECT  5.701 52.464 6.188 88.968 ;
     RECT  5.123 90 6.188 104.808 ;
     RECT  6.188 0.528 6.292 105.312 ;
     RECT  6.292 0.798 6.484 105.042 ;
     RECT  6.484 4.656 6.545 30.072 ;
     RECT  6.484 58.464 6.545 79.704 ;
     RECT  6.545 70.656 6.581 79.704 ;
     RECT  6.545 4.656 6.611 25.944 ;
     RECT  6.484 38.496 6.653 57.192 ;
     RECT  6.611 4.656 6.659 23.64 ;
     RECT  6.484 34.656 6.689 37.464 ;
     RECT  6.653 38.496 6.689 54.12 ;
     RECT  6.689 38.496 6.761 53.496 ;
     RECT  6.545 58.464 6.797 69.576 ;
     RECT  6.545 27.024 6.803 30.072 ;
     RECT  6.484 93.456 6.851 97.08 ;
     RECT  6.689 34.752 6.869 37.464 ;
     RECT  6.581 70.752 6.869 79.704 ;
     RECT  6.484 31.392 6.905 32.472 ;
     RECT  6.611 24.624 6.941 25.944 ;
     RECT  6.869 34.752 6.977 37.416 ;
     RECT  6.761 50.832 6.977 53.496 ;
     RECT  6.659 20.112 7.085 23.64 ;
     RECT  6.484 98.16 7.085 104.04 ;
     RECT  6.869 70.752 7.091 79.56 ;
     RECT  6.484 81.408 7.091 86.76 ;
     RECT  6.761 38.496 7.139 49.752 ;
     RECT  7.139 41.472 7.187 49.752 ;
     RECT  6.797 66.24 7.193 69.576 ;
     RECT  6.797 58.464 7.229 65.016 ;
     RECT  7.091 70.752 7.229 77.16 ;
     RECT  6.977 34.752 7.235 34.776 ;
     RECT  7.229 71.76 7.235 77.16 ;
     RECT  6.803 27.648 7.301 30.072 ;
     RECT  7.235 73.92 7.301 74.04 ;
     RECT  6.659 4.656 7.337 18.552 ;
     RECT  6.977 36.288 7.337 37.416 ;
     RECT  7.139 38.496 7.379 40.008 ;
     RECT  7.301 28.8 7.409 30.072 ;
     RECT  7.187 47.664 7.409 49.752 ;
     RECT  7.187 41.472 7.445 44.712 ;
     RECT  7.085 101.952 7.445 104.04 ;
     RECT  6.977 52.32 7.475 53.496 ;
     RECT  6.484 88.272 7.477 92.28 ;
     RECT  6.851 93.456 7.477 94.296 ;
     RECT  6.653 55.392 7.517 57.192 ;
     RECT  7.477 88.272 7.523 94.296 ;
     RECT  7.337 9.648 7.553 18.552 ;
     RECT  6.941 24.624 7.553 25.512 ;
     RECT  7.235 75.168 7.553 77.16 ;
     RECT  7.091 78.24 7.553 79.224 ;
     RECT  7.091 83.184 7.573 86.76 ;
     RECT  7.475 52.32 7.625 52.392 ;
     RECT  7.517 55.392 7.625 56.616 ;
     RECT  7.229 58.464 7.625 61.176 ;
     RECT  7.573 83.184 7.625 87.144 ;
     RECT  7.445 101.952 7.625 103.752 ;
     RECT  7.379 38.688 7.661 39.768 ;
     RECT  7.229 62.64 7.661 65.016 ;
     RECT  7.625 83.184 7.661 86.76 ;
     RECT  7.409 28.944 7.729 30.072 ;
     RECT  7.625 58.464 7.729 59.88 ;
     RECT  6.977 50.832 7.733 50.856 ;
     RECT  7.729 58.128 7.769 59.88 ;
     RECT  7.301 27.648 7.801 27.672 ;
     RECT  7.625 52.368 7.841 52.392 ;
     RECT  6.484 1.152 7.873 3.288 ;
     RECT  7.337 4.656 7.873 8.568 ;
     RECT  7.409 47.808 7.873 49.752 ;
     RECT  6.851 95.472 7.945 97.08 ;
     RECT  7.625 55.392 7.981 56.424 ;
     RECT  7.661 83.616 8.003 86.76 ;
     RECT  7.523 88.272 8.051 94.056 ;
     RECT  8.003 83.952 8.057 84.36 ;
     RECT  8.003 85.44 8.057 86.76 ;
     RECT  8.051 89.424 8.057 94.056 ;
     RECT  7.945 95.136 8.057 97.08 ;
     RECT  7.085 98.16 8.089 98.712 ;
     RECT  7.085 99.696 8.089 100.872 ;
     RECT  7.475 53.472 8.093 53.496 ;
     RECT  7.091 81.408 8.125 81.528 ;
     RECT  8.057 90.576 8.165 94.056 ;
     RECT  6.905 31.728 8.197 32.472 ;
     RECT  7.625 60.912 8.197 61.176 ;
     RECT  7.661 62.64 8.197 64.056 ;
     RECT  7.729 28.944 8.201 30.216 ;
     RECT  8.057 83.952 8.201 84.312 ;
     RECT  8.089 98.16 8.233 100.872 ;
     RECT  7.625 101.952 8.233 102.408 ;
     RECT  8.197 60.912 8.243 64.056 ;
     RECT  7.553 18.144 8.309 18.552 ;
     RECT  7.337 36.912 8.341 37.416 ;
     RECT  7.445 41.472 8.341 42.12 ;
     RECT  8.305 35.328 8.387 35.352 ;
     RECT  7.193 66.624 8.387 69.576 ;
     RECT  7.873 47.808 8.417 50.712 ;
     RECT  8.387 68.208 8.417 69.576 ;
     RECT  7.301 74.016 8.449 74.04 ;
     RECT  8.233 98.16 8.449 102.408 ;
     RECT  7.553 9.648 8.483 17.112 ;
     RECT  7.873 1.152 8.485 8.568 ;
     RECT  8.197 31.296 8.485 32.472 ;
     RECT  7.769 58.128 8.485 59.832 ;
     RECT  7.661 38.688 8.489 39.624 ;
     RECT  8.449 98.064 8.525 102.408 ;
     RECT  8.197 34.224 8.531 34.248 ;
     RECT  8.489 38.688 8.531 39.432 ;
     RECT  7.981 55.008 8.531 56.424 ;
     RECT  8.341 65.28 8.531 65.304 ;
     RECT  8.387 66.624 8.531 66.888 ;
     RECT  8.125 79.728 8.531 79.752 ;
     RECT  7.445 43.872 8.533 44.712 ;
     RECT  8.525 100.368 8.579 102.408 ;
     RECT  7.801 27.312 8.593 27.672 ;
     RECT  8.417 47.808 8.597 47.88 ;
     RECT  8.485 31.296 8.627 32.664 ;
     RECT  8.485 0.576 8.633 8.568 ;
     RECT  8.483 9.648 8.633 13.896 ;
     RECT  8.243 62.64 8.633 64.056 ;
     RECT  8.593 27.312 8.665 27.912 ;
     RECT  7.553 75.168 8.665 76.824 ;
     RECT  7.553 78.24 8.677 78.6 ;
     RECT  7.229 70.752 8.705 70.776 ;
     RECT  8.665 26.64 8.723 27.912 ;
     RECT  8.449 74.016 8.723 74.088 ;
     RECT  8.341 40.992 8.737 42.12 ;
     RECT  8.633 9.648 8.741 12.792 ;
     RECT  8.597 47.808 8.741 47.832 ;
     RECT  8.125 80.832 8.809 81.528 ;
     RECT  8.531 55.488 8.813 56.424 ;
     RECT  8.057 89.424 8.813 89.448 ;
     RECT  8.737 40.992 8.819 42.168 ;
     RECT  8.057 86.736 8.917 86.76 ;
     RECT  8.819 41.472 8.921 42.12 ;
     RECT  8.417 48.912 8.921 50.712 ;
     RECT  8.341 36.432 8.957 37.416 ;
     RECT  8.485 58.032 8.957 59.832 ;
     RECT  8.921 49.728 9.029 50.712 ;
     RECT  8.633 6.144 9.061 8.568 ;
     RECT  8.741 9.648 9.061 11.688 ;
     RECT  8.665 75.12 9.061 76.824 ;
     RECT  9.061 6.144 9.065 11.688 ;
     RECT  7.625 103.584 9.097 103.752 ;
     RECT  8.723 27.648 9.107 27.912 ;
     RECT  9.061 74.784 9.107 76.824 ;
     RECT  8.917 86.736 9.133 87.144 ;
     RECT  8.051 88.272 9.133 88.344 ;
     RECT  9.065 7.872 9.137 11.688 ;
     RECT  8.201 29.184 9.137 30.216 ;
     RECT  8.677 78.24 9.137 78.696 ;
     RECT  8.417 68.208 9.155 69.384 ;
     RECT  8.773 70.656 9.155 70.68 ;
     RECT  8.809 80.832 9.155 81.624 ;
     RECT  8.243 60.912 9.169 61.08 ;
     RECT  8.627 31.728 9.173 32.664 ;
     RECT  8.633 63.216 9.173 64.056 ;
     RECT  8.531 38.688 9.205 39.336 ;
     RECT  8.057 85.44 9.205 85.656 ;
     RECT  8.165 90.576 9.205 93.912 ;
     RECT  8.057 95.136 9.205 95.16 ;
     RECT  9.205 89.616 9.251 95.16 ;
     RECT  9.137 78.672 9.281 78.696 ;
     RECT  8.201 83.952 9.347 83.976 ;
     RECT  9.205 85.248 9.347 85.656 ;
     RECT  9.133 86.736 9.347 88.344 ;
     RECT  8.483 14.928 9.389 17.112 ;
     RECT  8.533 43.824 9.461 44.712 ;
     RECT  8.633 3.264 9.497 5.112 ;
     RECT  8.579 100.368 9.529 100.872 ;
     RECT  7.235 71.76 9.565 72.84 ;
     RECT  9.529 100.32 9.587 100.872 ;
     RECT  8.531 66.624 9.601 66.696 ;
     RECT  9.461 43.872 9.605 44.712 ;
     RECT  7.085 20.112 9.637 21.672 ;
     RECT  7.085 22.656 9.637 23.64 ;
     RECT  7.553 24.816 9.637 25.512 ;
     RECT  9.205 38.592 9.637 39.336 ;
     RECT  8.813 56.352 9.637 56.424 ;
     RECT  9.173 63.552 9.637 64.056 ;
     RECT  9.155 68.208 9.637 68.232 ;
     RECT  9.107 76.608 9.637 76.824 ;
     RECT  8.057 96.576 9.637 97.08 ;
     RECT  8.525 98.064 9.637 99.192 ;
     RECT  9.587 100.656 9.637 100.872 ;
     RECT  8.579 101.952 9.637 102.408 ;
     RECT  9.097 103.488 9.637 103.752 ;
     RECT  9.637 96.576 9.673 99.192 ;
     RECT  9.637 100.656 9.673 102.408 ;
     RECT  9.637 103.488 9.673 104.664 ;
     RECT  9.137 29.616 9.677 30.216 ;
     RECT  9.137 10.944 9.713 11.4 ;
     RECT  9.155 69.312 9.713 69.384 ;
     RECT  9.673 96.192 9.713 99.192 ;
     RECT  9.673 100.656 9.713 104.664 ;
     RECT  9.601 66.048 9.785 66.696 ;
     RECT  8.309 18.528 9.817 18.552 ;
     RECT  8.957 37.056 9.817 37.416 ;
     RECT  9.637 38.592 9.817 39.768 ;
     RECT  9.169 60.864 9.817 61.08 ;
     RECT  8.921 41.472 9.925 41.496 ;
     RECT  9.781 42.816 9.925 42.84 ;
     RECT  9.637 56.352 9.997 56.856 ;
     RECT  9.565 71.76 9.997 73.368 ;
     RECT  9.637 68.16 10.033 68.232 ;
     RECT  9.997 71.616 10.033 73.368 ;
     RECT  9.107 74.784 10.033 74.904 ;
     RECT  9.997 56.064 10.141 56.856 ;
     RECT  9.065 6.144 10.177 6.744 ;
     RECT  9.029 50.208 10.177 50.712 ;
     RECT  8.633 13.872 10.213 13.896 ;
     RECT  9.389 14.928 10.213 16.152 ;
     RECT  9.637 20.112 10.213 23.64 ;
     RECT  9.107 27.648 10.213 27.672 ;
     RECT  10.141 55.296 10.213 56.856 ;
     RECT  9.817 60.288 10.213 61.08 ;
     RECT  9.785 66.048 10.213 66.456 ;
     RECT  8.633 0.576 10.249 2.088 ;
     RECT  9.497 3.264 10.249 4.536 ;
     RECT  10.177 5.568 10.249 6.744 ;
     RECT  9.137 7.872 10.249 9.864 ;
     RECT  9.817 18.528 10.249 18.84 ;
     RECT  10.213 19.968 10.249 23.64 ;
     RECT  9.637 24.816 10.249 25.752 ;
     RECT  10.213 27.456 10.249 27.672 ;
     RECT  9.173 31.728 10.249 32.088 ;
     RECT  9.637 33.408 10.249 34.2 ;
     RECT  9.605 44.064 10.249 44.712 ;
     RECT  7.187 45.84 10.249 46.584 ;
     RECT  10.177 50.112 10.249 50.712 ;
     RECT  10.213 60.288 10.249 61.464 ;
     RECT  10.033 67.968 10.249 68.232 ;
     RECT  9.781 79.296 10.321 79.32 ;
     RECT  9.155 81.216 10.321 81.624 ;
     RECT  10.249 18.24 10.357 18.84 ;
     RECT  10.249 19.968 10.357 27.672 ;
     RECT  10.249 31.728 10.357 34.2 ;
     RECT  9.925 41.472 10.357 42.84 ;
     RECT  10.249 44.064 10.357 47.448 ;
     RECT  10.249 49.344 10.357 50.712 ;
     RECT  10.213 52.608 10.357 53.016 ;
     RECT  9.637 63.552 10.357 64.344 ;
     RECT  10.213 65.856 10.357 66.456 ;
     RECT  9.347 85.44 10.357 85.656 ;
     RECT  9.347 86.736 10.357 86.76 ;
     RECT  10.357 44.064 10.429 47.64 ;
     RECT  10.357 49.344 10.429 53.592 ;
     RECT  10.357 18.24 10.465 27.672 ;
     RECT  10.213 28.992 10.465 29.4 ;
     RECT  10.357 30.528 10.465 34.2 ;
     RECT  10.357 35.328 10.465 35.352 ;
     RECT  9.817 37.056 10.465 39.768 ;
     RECT  10.357 40.896 10.465 42.84 ;
     RECT  10.213 69.888 10.465 70.488 ;
     RECT  10.033 71.616 10.465 74.904 ;
     RECT  8.957 58.032 10.537 58.968 ;
     RECT  10.249 60.096 10.537 61.464 ;
     RECT  10.465 30.528 10.573 35.352 ;
     RECT  10.321 78.336 10.573 79.32 ;
     RECT  10.321 80.832 10.573 81.624 ;
     RECT  10.357 85.44 10.573 86.76 ;
     RECT  9.347 87.744 10.573 88.344 ;
     RECT  9.251 93.888 10.573 95.16 ;
     RECT  9.713 96.192 10.573 99.096 ;
     RECT  10.465 18.24 10.645 29.4 ;
     RECT  10.573 30.528 10.645 35.928 ;
     RECT  10.465 37.056 10.645 42.84 ;
     RECT  10.429 44.064 10.645 53.592 ;
     RECT  10.213 55.296 10.645 57.048 ;
     RECT  10.537 58.032 10.645 61.464 ;
     RECT  10.249 67.968 10.645 68.568 ;
     RECT  10.573 78.336 10.645 82.392 ;
     RECT  9.637 83.52 10.645 83.544 ;
     RECT  10.573 84.864 10.645 88.344 ;
     RECT  9.251 92.736 10.645 92.76 ;
     RECT  10.573 93.888 10.645 99.096 ;
     RECT  10.645 55.296 10.681 61.464 ;
     RECT  9.251 90.24 10.681 91.224 ;
     RECT  10.465 69.888 10.717 74.904 ;
     RECT  9.637 76.608 10.717 77.016 ;
     RECT  10.213 13.872 10.753 16.152 ;
     RECT  9.713 100.992 10.753 104.664 ;
     RECT  10.249 5.568 10.789 9.864 ;
     RECT  9.713 10.944 10.789 11.352 ;
     RECT  8.741 12.768 10.789 12.792 ;
     RECT  10.753 13.872 10.789 16.728 ;
     RECT  10.645 18.24 10.789 35.928 ;
     RECT  10.645 37.056 10.789 53.592 ;
     RECT  10.681 55.296 10.789 62.04 ;
     RECT  10.645 67.776 10.789 68.568 ;
     RECT  10.717 69.888 10.789 77.016 ;
     RECT  10.645 78.336 10.789 88.344 ;
     RECT  10.681 90.24 10.789 91.416 ;
     RECT  10.753 100.416 10.789 104.664 ;
     RECT  10.249 0.576 10.825 4.536 ;
     RECT  10.789 5.568 10.825 11.352 ;
     RECT  10.789 12.768 10.825 62.04 ;
     RECT  10.357 63.552 10.825 66.456 ;
     RECT  10.789 67.776 10.825 77.016 ;
     RECT  10.789 78.336 10.825 91.416 ;
     RECT  10.645 92.736 10.825 99.096 ;
     RECT  10.789 100.224 10.825 104.664 ;
     RECT  10.825 0.384 11.724 104.664 ;
     RECT  11.724 2.064 11.765 2.088 ;
     RECT  11.724 8.016 11.765 8.04 ;
     RECT  11.724 9.84 11.765 9.864 ;
     RECT  11.724 86.736 11.765 86.76 ;
    LAYER M5 ;
     RECT  5.904 0.144 5.928 0.517 ;
     RECT  0.78 0.517 0.9 0.787 ;
     RECT  5.904 0.517 6.3 0.787 ;
     RECT  3.792 0.757 4.344 0.997 ;
     RECT  5.904 0.787 6.492 1.045 ;
     RECT  2.496 0.997 4.344 1.093 ;
     RECT  5.376 1.045 6.492 1.093 ;
     RECT  0.78 0.787 1.092 1.381 ;
     RECT  0.78 1.381 1.464 1.525 ;
     RECT  2.496 1.093 6.492 1.525 ;
     RECT  0.78 1.525 6.492 1.909 ;
     RECT  0.528 1.909 6.492 2.339 ;
     RECT  8.496 1.669 8.52 2.725 ;
     RECT  8.16 2.725 8.52 2.771 ;
     RECT  8.16 2.771 8.184 3.443 ;
     RECT  0.78 2.339 6.492 4.213 ;
     RECT  0.288 4.213 6.492 4.691 ;
     RECT  0.288 4.691 1.704 5.171 ;
     RECT  8.208 5.029 8.232 5.701 ;
     RECT  8.208 5.701 8.376 5.747 ;
     RECT  0.288 5.171 1.656 6.181 ;
     RECT  3.024 4.691 6.492 6.181 ;
     RECT  0.288 6.181 6.492 6.323 ;
     RECT  8.352 5.747 8.376 7.619 ;
     RECT  0.78 6.323 6.492 7.861 ;
     RECT  0.672 7.861 6.492 8.485 ;
     RECT  0.624 8.485 6.492 8.629 ;
     RECT  0.432 8.629 6.492 9.397 ;
     RECT  0.192 9.397 6.492 9.923 ;
     RECT  9.072 8.533 9.096 10.549 ;
     RECT  8.496 10.549 9.096 10.595 ;
     RECT  8.496 10.595 8.52 11.699 ;
     RECT  0.624 9.923 6.492 12.469 ;
     RECT  0.192 12.469 6.492 12.611 ;
     RECT  0.78 12.611 6.492 13.621 ;
     RECT  0.672 13.621 6.648 14.197 ;
     RECT  8.448 13.045 8.472 14.243 ;
     RECT  0.672 14.197 7.416 14.867 ;
     RECT  0.672 14.867 1.092 14.963 ;
     RECT  2.064 14.867 7.416 15.011 ;
     RECT  2.112 15.011 7.416 16.115 ;
     RECT  0.78 14.963 1.092 16.117 ;
     RECT  2.112 16.115 4.824 16.117 ;
     RECT  5.904 16.115 7.416 17.075 ;
     RECT  0.78 16.117 4.824 17.605 ;
     RECT  5.904 17.075 6.648 17.605 ;
     RECT  0.78 17.605 6.648 17.989 ;
     RECT  0.672 17.989 6.648 18.037 ;
     RECT  0.288 18.037 6.648 18.805 ;
     RECT  0.192 18.805 6.648 18.947 ;
     RECT  0.288 18.947 4.68 19.571 ;
     RECT  0.576 19.571 4.68 19.667 ;
     RECT  5.904 18.947 6.648 20.389 ;
     RECT  5.664 20.389 6.648 21.155 ;
     RECT  0.624 19.667 4.68 21.203 ;
     RECT  8.88 16.501 8.904 21.395 ;
     RECT  5.904 21.155 6.6 22.165 ;
     RECT  0.78 21.203 4.68 22.645 ;
     RECT  0.192 22.645 4.68 22.741 ;
     RECT  0.192 22.741 4.728 22.789 ;
     RECT  5.904 22.165 6.648 22.789 ;
     RECT  0.192 22.789 6.648 22.931 ;
     RECT  0.192 22.931 4.728 23.171 ;
     RECT  5.904 22.931 6.648 23.317 ;
     RECT  0.384 23.171 4.728 24.131 ;
     RECT  0.384 24.131 4.488 24.181 ;
     RECT  0.192 24.181 4.488 24.659 ;
     RECT  8.16 23.317 8.184 24.805 ;
     RECT  8.16 24.805 8.712 24.851 ;
     RECT  5.904 23.317 6.888 25.955 ;
     RECT  0.192 24.659 4.344 26.629 ;
     RECT  0.192 26.629 4.392 26.819 ;
     RECT  0.24 26.819 4.392 27.205 ;
     RECT  8.688 24.851 8.712 27.347 ;
     RECT  0.24 27.205 4.488 27.395 ;
     RECT  0.624 27.395 4.488 27.829 ;
     RECT  0.624 27.829 4.536 28.931 ;
     RECT  0.624 28.931 4.344 28.981 ;
     RECT  5.904 25.955 6.792 29.123 ;
     RECT  9.072 27.877 9.096 29.219 ;
     RECT  0.192 28.981 4.344 29.747 ;
     RECT  0.192 29.747 4.248 29.891 ;
     RECT  0.288 29.891 4.248 30.899 ;
     RECT  0.672 30.899 4.248 31.427 ;
     RECT  5.904 29.123 6.6 31.525 ;
     RECT  5.808 31.525 6.6 31.861 ;
     RECT  5.232 31.861 6.6 31.907 ;
     RECT  0.78 31.427 4.248 32.051 ;
     RECT  8.592 29.893 8.616 32.629 ;
     RECT  8.496 32.629 8.616 32.675 ;
     RECT  0.78 32.051 4.056 32.821 ;
     RECT  0.192 32.821 4.056 33.013 ;
     RECT  0.192 33.013 4.2 33.155 ;
     RECT  0.78 33.155 4.2 34.117 ;
     RECT  5.235 31.907 6.6 34.117 ;
     RECT  0.78 34.117 6.6 34.165 ;
     RECT  8.496 32.675 8.52 34.259 ;
     RECT  0.192 34.165 6.6 34.499 ;
     RECT  0.78 34.499 6.6 34.741 ;
     RECT  8.352 35.317 8.376 36.467 ;
     RECT  0.78 34.741 7.224 37.333 ;
     RECT  0.672 37.333 7.224 38.485 ;
     RECT  0.672 38.485 7.368 38.725 ;
     RECT  0.288 38.725 7.368 39.253 ;
     RECT  8.496 37.189 8.52 39.443 ;
     RECT  0.192 39.253 7.368 39.971 ;
     RECT  0.576 39.971 7.368 40.019 ;
     RECT  0.576 40.019 7.128 40.499 ;
     RECT  8.448 39.589 8.472 40.981 ;
     RECT  8.448 40.981 8.808 41.027 ;
     RECT  0.78 40.499 7.128 41.651 ;
     RECT  0.78 41.651 3.432 43.285 ;
     RECT  4.464 41.651 7.128 43.285 ;
     RECT  8.784 41.027 8.808 43.813 ;
     RECT  8.544 43.813 8.808 43.859 ;
     RECT  0.672 43.285 7.176 44.917 ;
     RECT  0.192 44.917 7.176 45.251 ;
     RECT  0.672 45.251 7.176 47.075 ;
     RECT  0.672 47.075 6.888 47.699 ;
     RECT  0.672 47.699 6.792 48.371 ;
     RECT  0.672 48.371 6.648 48.949 ;
     RECT  0.192 48.949 6.648 49.043 ;
     RECT  0.192 49.043 1.092 49.091 ;
     RECT  2.256 49.043 6.648 49.667 ;
     RECT  0.78 49.091 1.092 50.101 ;
     RECT  2.256 49.667 2.904 50.101 ;
     RECT  8.544 43.859 8.568 50.243 ;
     RECT  0.78 50.101 2.904 50.965 ;
     RECT  3.888 49.667 6.648 50.965 ;
     RECT  0.78 50.965 6.648 51.059 ;
     RECT  0.78 51.059 6.492 52.021 ;
     RECT  0.288 52.021 6.492 52.067 ;
     RECT  5.088 52.067 6.492 52.309 ;
     RECT  0.288 52.067 3.912 52.499 ;
     RECT  0.288 52.499 3.192 53.557 ;
     RECT  0.192 53.557 3.192 53.699 ;
     RECT  5.088 52.309 7.464 54.179 ;
     RECT  0.78 53.699 3.192 54.661 ;
     RECT  5.568 54.179 7.464 55.427 ;
     RECT  0.288 54.661 3.192 56.677 ;
     RECT  0.288 56.677 3.24 56.917 ;
     RECT  0.288 56.917 3.96 57.013 ;
     RECT  0.192 57.013 3.96 57.155 ;
     RECT  0.288 57.155 3.96 57.157 ;
     RECT  5.568 55.427 6.492 57.157 ;
     RECT  0.288 57.157 4.488 57.493 ;
     RECT  5.568 57.157 6.6 57.493 ;
     RECT  0.288 57.493 6.6 57.683 ;
     RECT  0.288 57.683 3.192 58.211 ;
     RECT  0.528 58.211 3.192 58.403 ;
     RECT  0.528 58.403 2.76 58.739 ;
     RECT  0.78 58.739 2.76 59.797 ;
     RECT  0.78 59.797 3.096 60.325 ;
     RECT  4.464 57.683 6.6 60.851 ;
     RECT  8.496 54.997 8.52 60.949 ;
     RECT  8.208 60.949 8.52 60.995 ;
     RECT  0.672 60.325 3.096 61.237 ;
     RECT  0.192 61.237 3.096 61.333 ;
     RECT  0.192 61.333 3.192 61.525 ;
     RECT  5.568 60.851 6.6 62.437 ;
     RECT  0.192 61.525 3.24 62.485 ;
     RECT  0.096 62.485 3.24 62.581 ;
     RECT  0.096 62.581 3.336 62.725 ;
     RECT  4.464 60.851 4.488 62.771 ;
     RECT  8.208 60.995 8.232 62.771 ;
     RECT  0.096 62.725 3.384 63.109 ;
     RECT  5.568 62.437 6.888 63.781 ;
     RECT  0.096 63.109 3.432 63.875 ;
     RECT  0.192 63.875 3.432 64.451 ;
     RECT  0.624 64.451 3.432 64.643 ;
     RECT  0.78 64.643 3.432 64.837 ;
     RECT  5.568 63.781 6.936 65.027 ;
     RECT  0.78 64.837 3.96 65.509 ;
     RECT  0.78 65.509 4.344 66.133 ;
     RECT  5.568 65.027 6.492 66.133 ;
     RECT  0.78 66.133 6.492 66.275 ;
     RECT  0.78 66.275 3.912 66.755 ;
     RECT  8.496 65.269 8.52 66.899 ;
     RECT  0.78 66.755 3.816 67.475 ;
     RECT  0.78 67.475 2.664 67.907 ;
     RECT  4.896 66.275 6.492 67.907 ;
     RECT  0.78 67.907 2.28 68.725 ;
     RECT  5.568 67.907 6.492 68.917 ;
     RECT  8.352 67.429 8.376 68.965 ;
     RECT  8.352 68.965 9.144 69.011 ;
     RECT  3.792 67.475 3.816 69.493 ;
     RECT  0.432 68.725 2.28 69.587 ;
     RECT  5.568 68.917 7.272 69.587 ;
     RECT  0.432 69.587 1.092 69.877 ;
     RECT  0.288 69.877 1.092 70.261 ;
     RECT  0.192 70.261 1.092 70.403 ;
     RECT  2.256 69.587 2.28 70.501 ;
     RECT  0.432 70.403 1.092 70.645 ;
     RECT  2.256 70.501 2.616 70.645 ;
     RECT  0.432 70.645 2.616 70.693 ;
     RECT  3.792 69.493 3.96 70.693 ;
     RECT  0.432 70.693 3.96 71.221 ;
     RECT  0.432 71.221 4.2 71.459 ;
     RECT  9.12 69.011 9.144 71.797 ;
     RECT  0.78 71.459 4.2 71.843 ;
     RECT  9.12 71.797 9.672 72.323 ;
     RECT  0.78 71.843 3.96 72.995 ;
     RECT  5.568 69.587 6.492 73.525 ;
     RECT  9.648 72.323 9.672 74.053 ;
     RECT  5.568 73.525 7.224 74.147 ;
     RECT  0.78 72.995 3.432 74.485 ;
     RECT  8.688 74.053 9.672 74.819 ;
     RECT  6.048 74.147 7.224 75.011 ;
     RECT  6.048 75.011 7.08 75.109 ;
     RECT  0.78 74.485 4.008 75.157 ;
     RECT  0.78 75.157 4.488 75.781 ;
     RECT  0.288 75.781 4.488 76.357 ;
     RECT  8.688 74.819 9.096 76.451 ;
     RECT  0.288 76.357 4.536 77.027 ;
     RECT  0.672 77.027 4.536 77.555 ;
     RECT  5.712 75.109 7.08 78.565 ;
     RECT  0.672 77.555 3.864 78.707 ;
     RECT  8.688 76.451 8.712 78.707 ;
     RECT  5.328 78.565 7.08 79.475 ;
     RECT  0.78 78.707 3.864 79.621 ;
     RECT  0.78 79.621 3.96 80.149 ;
     RECT  0.78 80.149 4.152 80.341 ;
     RECT  8.496 79.717 8.52 80.821 ;
     RECT  8.496 80.821 9.144 80.867 ;
     RECT  0.78 80.341 4.488 81.205 ;
     RECT  6.048 79.475 7.08 81.205 ;
     RECT  0.78 81.205 7.08 81.445 ;
     RECT  0.288 81.445 7.08 82.115 ;
     RECT  0.288 82.115 4.536 82.211 ;
     RECT  6.048 82.115 7.08 82.403 ;
     RECT  0.78 82.211 4.536 83.363 ;
     RECT  2.64 83.363 4.536 83.605 ;
     RECT  0.78 83.363 1.656 83.749 ;
     RECT  6.048 82.403 6.84 83.843 ;
     RECT  9.12 80.867 9.144 83.941 ;
     RECT  9.12 83.941 9.336 83.987 ;
     RECT  6.048 83.843 6.648 84.277 ;
     RECT  0.672 83.749 1.656 84.325 ;
     RECT  2.64 83.605 4.68 84.325 ;
     RECT  0.672 84.325 4.68 84.901 ;
     RECT  5.664 84.277 6.648 84.901 ;
     RECT  0.672 84.901 6.648 86.005 ;
     RECT  0.624 86.005 6.648 86.099 ;
     RECT  7.968 83.605 7.992 86.099 ;
     RECT  6.18 86.099 6.648 87.109 ;
     RECT  9.312 83.987 9.336 87.109 ;
     RECT  9.216 87.109 9.336 87.155 ;
     RECT  0.624 86.099 5.16 87.589 ;
     RECT  0.576 87.589 5.16 87.925 ;
     RECT  0.288 87.925 5.16 89.123 ;
     RECT  6.18 87.109 7.608 89.173 ;
     RECT  6.18 89.173 8.04 89.219 ;
     RECT  0.576 89.123 5.16 89.747 ;
     RECT  0.672 89.747 5.16 90.469 ;
     RECT  6.18 89.219 6.792 90.469 ;
     RECT  0.672 90.469 6.792 91.141 ;
     RECT  8.016 89.219 8.04 91.235 ;
     RECT  0.288 91.141 6.792 91.331 ;
     RECT  7.968 91.429 7.992 92.339 ;
     RECT  0.288 91.331 4.248 92.435 ;
     RECT  0.576 92.435 4.248 92.629 ;
     RECT  5.232 91.331 6.792 92.629 ;
     RECT  0.576 92.629 6.792 92.821 ;
     RECT  0.576 92.821 7.512 94.307 ;
     RECT  0.576 94.307 6.84 94.691 ;
     RECT  0.576 94.691 6.792 96.181 ;
     RECT  0.192 96.181 6.792 96.467 ;
     RECT  0.192 96.467 4.2 96.515 ;
     RECT  5.232 96.467 6.792 96.515 ;
     RECT  0.576 96.515 4.2 96.707 ;
     RECT  5.232 96.515 6.492 97.235 ;
     RECT  0.576 96.707 4.104 97.525 ;
     RECT  0.192 97.525 4.104 98.149 ;
     RECT  0.192 98.149 4.344 98.485 ;
     RECT  9.216 87.155 9.24 98.579 ;
     RECT  5.76 97.235 6.492 99.155 ;
     RECT  0.192 98.485 4.488 99.203 ;
     RECT  0.576 99.203 4.488 99.539 ;
     RECT  0.624 99.539 4.488 100.261 ;
     RECT  6.18 99.155 6.492 100.261 ;
     RECT  9.552 99.013 9.576 100.355 ;
     RECT  6.18 100.261 6.6 100.693 ;
     RECT  0.624 100.261 4.536 100.789 ;
     RECT  0.288 100.789 4.536 100.885 ;
     RECT  5.76 100.693 6.6 100.885 ;
     RECT  0.288 100.885 6.6 102.037 ;
     RECT  0.192 102.037 6.6 102.085 ;
     RECT  0.192 102.085 6.84 102.179 ;
     RECT  0.576 102.179 6.84 102.227 ;
     RECT  0.672 102.227 6.84 102.659 ;
     RECT  0.672 102.659 4.536 102.707 ;
     RECT  5.76 102.659 6.84 103.235 ;
     RECT  8.544 100.837 8.568 103.763 ;
     RECT  5.76 103.235 6.492 103.907 ;
     RECT  0.78 102.707 4.536 104.149 ;
     RECT  0.78 104.149 5.112 104.339 ;
     RECT  0.78 104.339 3.96 104.915 ;
     RECT  5.088 104.339 5.112 104.915 ;
     RECT  3.024 104.915 3.048 104.963 ;
     RECT  0.78 104.915 1.092 105.053 ;
     RECT  6.18 103.907 6.492 105.053 ;
     RECT  0.78 105.053 0.9 105.323 ;
     RECT  6.18 105.053 6.3 105.323 ;
    LAYER M6 ;
     RECT  0.54 0.996 11.34 1.86 ;
     RECT  0.54 6.396 11.34 7.26 ;
     RECT  0.54 11.796 11.34 12.66 ;
     RECT  0.54 17.196 11.34 18.06 ;
     RECT  0.54 22.596 11.34 23.46 ;
     RECT  0.54 27.996 11.34 28.86 ;
     RECT  0.54 33.396 11.34 34.26 ;
     RECT  0.54 38.796 11.34 39.66 ;
     RECT  0.54 44.196 11.34 45.06 ;
     RECT  0.54 49.596 11.34 50.46 ;
     RECT  0.54 54.996 11.34 55.86 ;
     RECT  0.54 60.396 11.34 61.26 ;
     RECT  0.54 65.796 11.34 66.66 ;
     RECT  0.54 71.196 11.34 72.06 ;
     RECT  0.54 76.596 11.34 77.46 ;
     RECT  0.54 81.996 11.34 82.86 ;
     RECT  0.54 87.396 11.34 88.26 ;
     RECT  0.54 92.796 11.34 93.66 ;
     RECT  0.54 98.196 11.34 99.06 ;
     RECT  0.54 103.596 11.34 104.46 ;
  END
END ot_attn_bank_ew544
END LIBRARY
